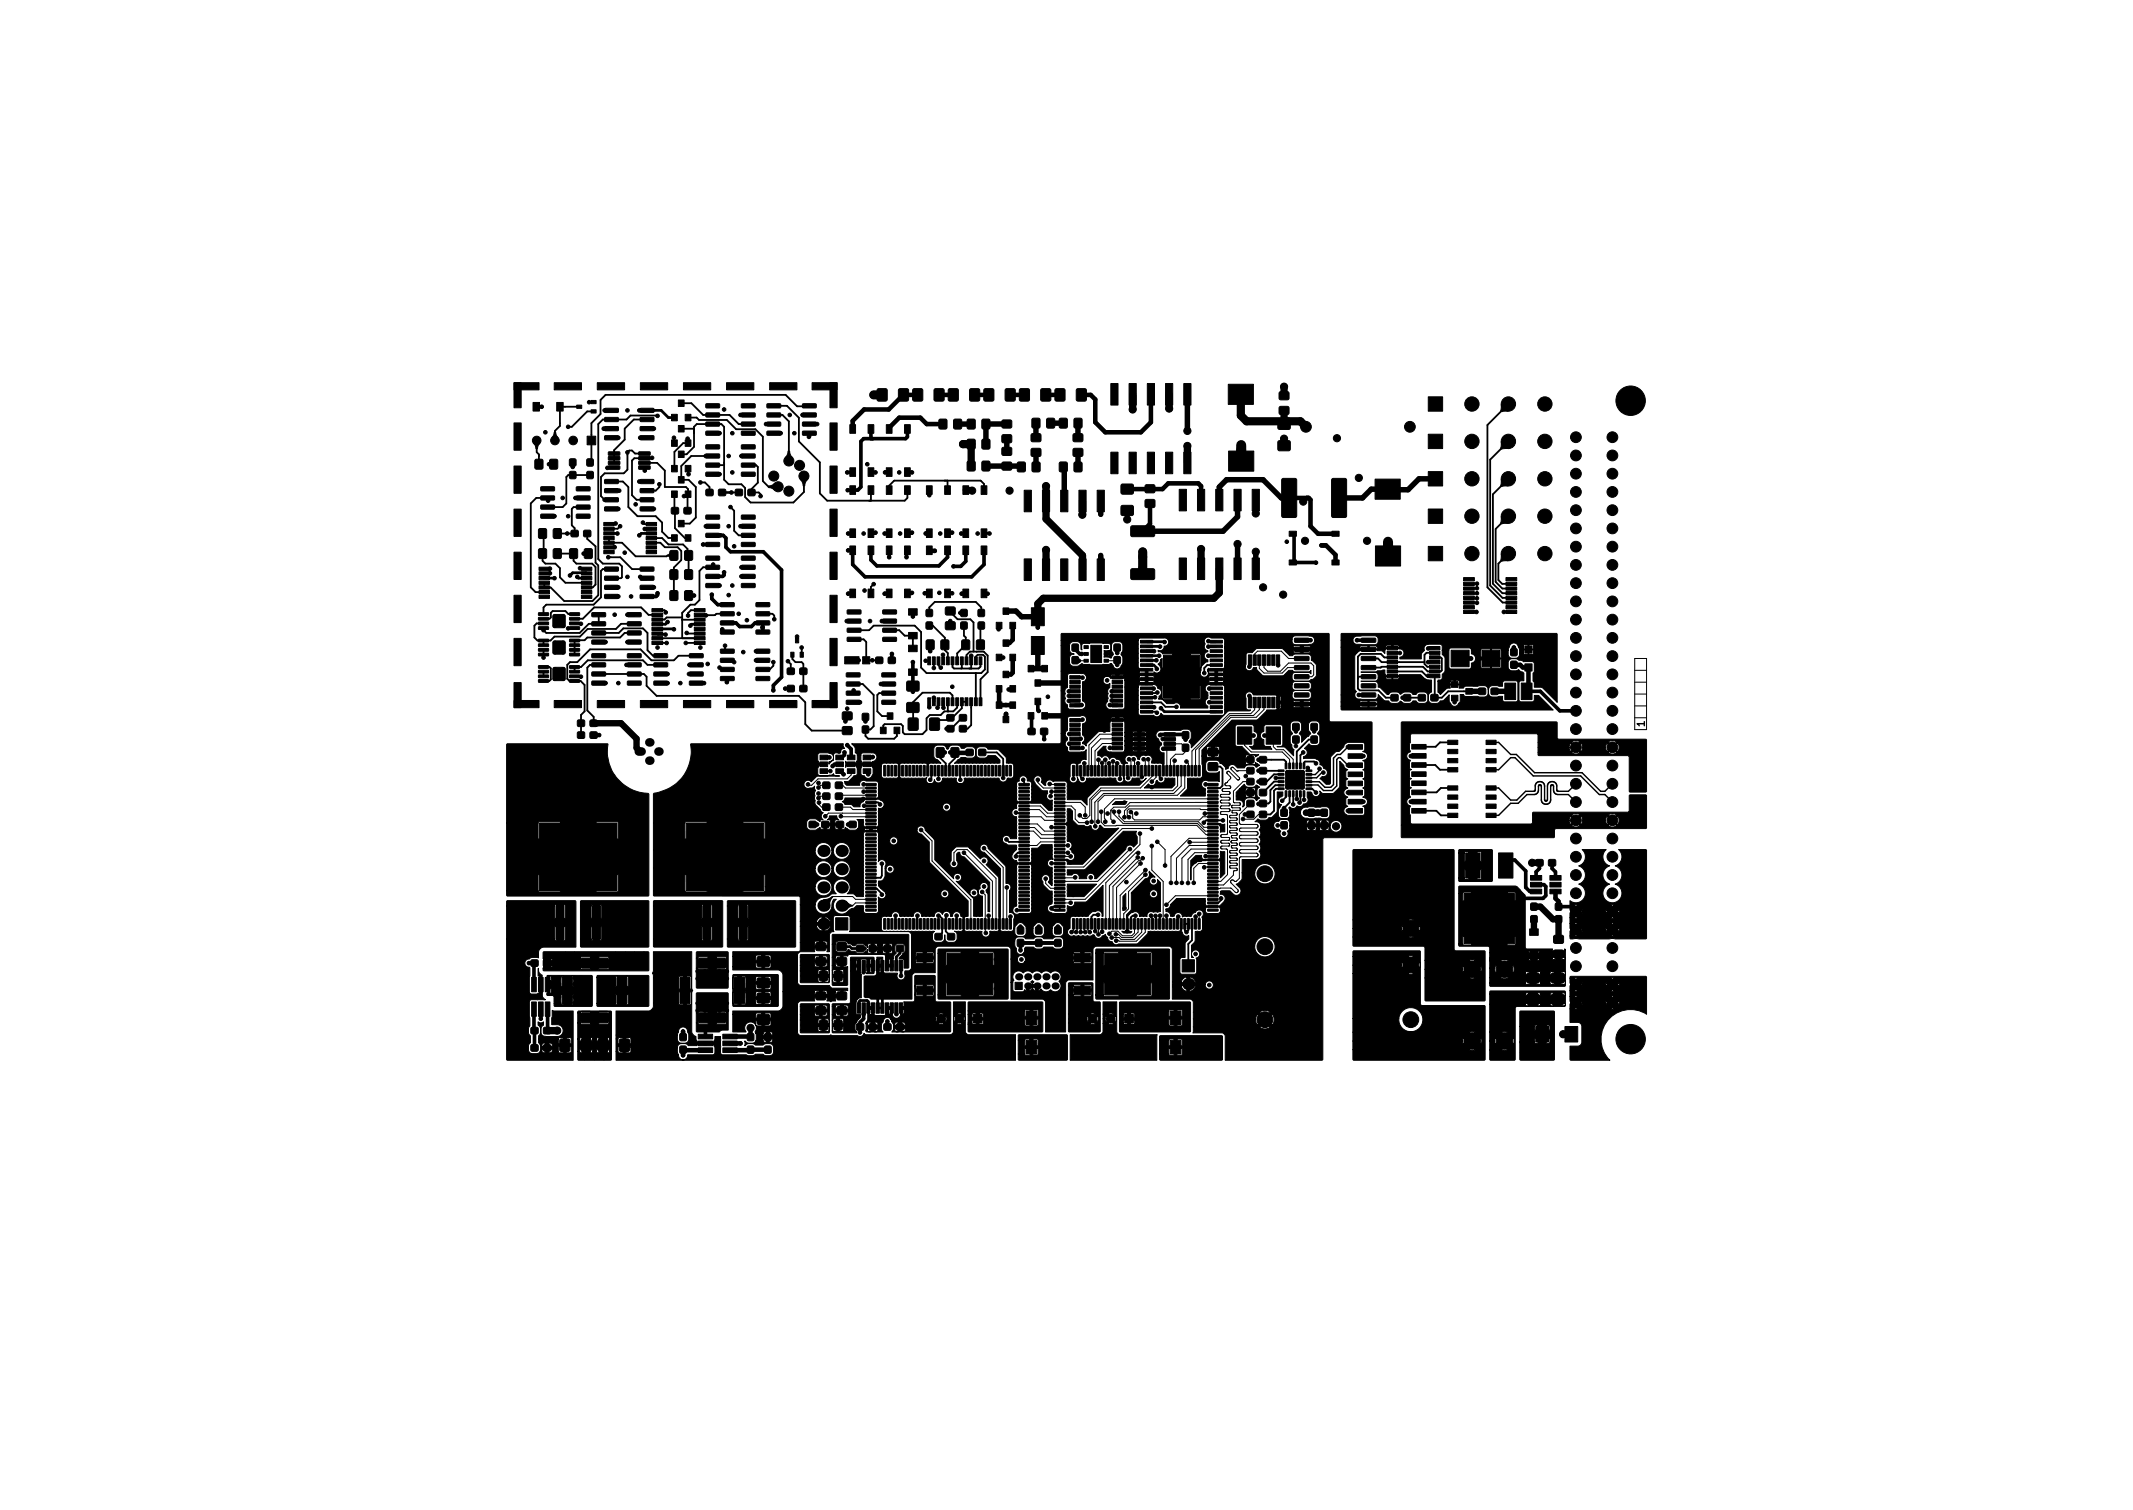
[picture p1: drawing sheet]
<svg xmlns="http://www.w3.org/2000/svg" width="297mm" height="210mm" viewBox="0 0 297 210" stroke-linecap="round" stroke-linejoin="round" font-family="sans-serif">
<defs><g id="words">
<text font-size="1.4" x="229" y="101.2" transform="rotate(-90 229 101.2)">1</text>
</g></defs>
<g fill="#000" stroke="#000" stroke-width=".14">
<path d="M71.6 53.3h1v3.5h-1zM74.2 56h.9v1.2h-.9zM71.6 53.3h3.5v1h-3.5zM77.5 56h.9v1.2h-.9zM77.2 53.3h3.8v1h-3.8zM80.3 56.4h.7v.5h-.7zM82.3 55.8h.7v.4h-.7zM82.3 57.1h.7v.4h-.7zM84.2 59.4h1.8l.1 .1v.4l-.1 .1h-1.7l-.1-.2zM84.2 58.2l1.8-.1 .1 .1v.4l-.1 .1h-1.7l-.1-.1zM84.2 56.9l1.8-.1 .1 .2v.3l-.1 .1h-1.7l-.1-.1zM83.2 53.3h3.8v1h-3.8z"/>
<path d="M89.2 56.9l1.8-.1 .1 .2v.3l-.2 .1h-1.6l-.2-.1zM89.2 58.2l1.8-.1 .1 .1v.4l-.2 .1h-1.6l-.2-.1zM89.2 59.4h1.8l.1 .1v.4l-.2 .1h-1.6l-.2-.2zM89.2 53.3h3.8v1h-3.8zM93.5 57.7h.8v.9h-.8zM94.5 55.7h.8v.9h-.8zM95.4 57.7h.8v.9h-.8zM95.2 53.3h3.8v1h-3.8zM98.3 58.8h1.8l.1 .1v.3l-.1 .1h-1.7l-.1-.1zM98.3 57.5h1.8l.1 .1v.4l-.1 .1h-1.7l-.1-.2zM98.3 56.3l1.8-.1 .1 .1v.4l-.1 .1h-1.7l-.1-.1zM101.2 53.3h3.8v1h-3.8z"/>
<path d="M103.3 56.3l1.8-.1 .1 .1v.4l-.2 .1h-1.7l-.1-.1zM103.3 57.5h1.8l.1 .1v.4l-.2 .1h-1.7l-.1-.2zM103.3 58.8h1.8l.1 .1v.3l-.2 .1h-1.7l-.1-.1zM106.8 58.8h1.8l.1 .1v.3l-.1 .1h-1.7l-.1-.1zM106.8 57.5h1.8l.1 .1v.4l-.1 .1h-1.7l-.1-.2zM106.8 56.3l1.8-.1 .1 .1v.4l-.1 .1h-1.7l-.1-.1zM107.2 53.3h3.8v1h-3.8zM111.8 56.3l1.8-.1 .1 .1v.4l-.1 .1h-1.7l-.2-.1zM111.8 57.5h1.8l.1 .1v.4l-.1 .1h-1.7l-.2-.2zM111.8 58.8h1.8l.1 .1v.3l-.1 .1h-1.7l-.2-.1zM115.6 53.3h1v3.5h-1zM113.1 53.3h3.5v1h-3.5z"/>
<path d="M122.2 54.2l1.1-.1 .2 .1 .1 1.4-.1 .2-1.1 .1-.2-.1-.1-1.4zM125.2 54.2l1.1-.1 .2 .1v1.4l-.1 .2-1 .1-.2-.1-.1-1.4zM127.2 54.2l1.1-.1 .2 .1v1.4l-.1 .2-1.1 .1-.2-.1v-1.4zM130.1 54.2l1.1-.1 .2 .1 .1 1.4-.1 .2-1.1 .1-.2-.1v-1.4zM130.8 58.4l.8-.1 .2 .1 .1 1.1-.1 .2h-.8h-.2l-.1-1.1zM132.1 54.2l1.1-.1 .2 .1 .1 1.4-.1 .2-1.1 .1-.2-.1-.1-1.4zM132.9 58.4l.8-.1 .2 .1v1.1l-.1 .2h-.8h-.2v-1.1zM134.7 58.4l.9-.1 .2 .1v1.1l-.1 .2h-.8h-.2v-1.1zM135.1 54.2l1.1-.1 .2 .1v1.4l-.1 .2-1 .1-.2-.1-.1-1.4zM136.8 58.4l.8-.1 .2 .1 .1 1.1-.1 .2h-.8h-.2l-.1-1.1zM137.1 54.2l1.1-.1 .2 .1v1.4l-.1 .2-1.1 .1-.2-.1v-1.4zM139.6 58.5h.2h1l.1 .2v.8l-.2 .1h-1.1l-.1-.2z"/>
<path d="M140 54.2l1.1-.1 .2 .1 .1 1.4-.1 .2-1.1 .1-.2-.1v-1.4zM142 54.2l1.1-.1 .2 .1 .1 1.4-.1 .2-1.1 .1-.2-.1-.1-1.4zM143.8 58.3l.8-.1 .2 .1v1.1l-.1 .2h-.8l-.2-.1v-1zM145 54.2l1.1-.1 .2 .1v1.4v.2l-1.1 .1-.2-.1-.1-1.4zM145.8 58.3l.8-.1 .2 .1 .1 1.1-.1 .2h-.8l-.2-.1-.1-1zM147 54.2l1.1-.1 .2 .1v1.4l-.1 .2-1.1 .1-.1-.1-.1-1.4zM147.6 58.3l.8-.1 .2 .1v1.1v.2h-.9l-.1-.1-.1-1zM149.6 58.3l.8-.1 .2 .1 .1 1.1-.1 .2h-.8l-.2-.1-.1-1zM149.9 54.2l1.1-.1 .2 .1 .1 1.4-.1 .2-1.1 .1-.2-.1v-1.4zM154.7 53.4h1v3h-1zM157.2 53.4h1v3h-1zM159.8 53.4h1v3h-1z"/>
<path d="M162.3 53.4h1v3h-1zM164.9 53.4h1v3h-1zM171 53.5h3.5v2.8h-3.5zM178.2 54.6l.2-.1 1 .1 .1 .2v.8l-.2 .1-1.1-.1-.1-.2zM178.2 56.7l.2-.1h1l.1 .2v.8l-.2 .1h-1.1l-.1-.2zM178 58.4h.2h1.4l.1 .2-.1 1.1-.2 .1-1.4-.1-.1-.2zM198.9 55.3h2v2h-2zM209.1 56.3l1.3-.4-.4 1.3-.9 .1-.1-.1zM71.6 58.9h1v3.8h-1zM71.6 64.9h1v3.8h-1zM71.6 70.9h1v3.8h-1zM75.1 79h1.4v.4h-1.4z"/>
<path d="M74.7 61.1l.4 .7-.2 .3v.4h-.3v-.4l-.3-.3zM74.5 64l.9-.1 .2 .1v1.1l-.1 .2h-.8l-.2-.1v-1zM75.1 73.7l.8-.1 .2 .1v1l-.1 .2-.8 .1-.2-.1v-1.1zM75.1 76.5l.8-.1 .2 .1v1l-.1 .2-.8 .1-.2-.1v-1.1zM75.3 71.6h1.8l.1 .1v.4l-.1 .1h-1.7l-.1-.2zM75.3 70.4l1.8-.1 .1 .1v.4l-.1 .1h-1.7l-.1-.1zM75.3 69.1l1.8-.1 .1 .2v.3l-.1 .1h-1.7l-.1-.1zM75.3 67.8h1.8l.1 .1v.3l-.1 .2h-1.7l-.1-.2zM77.2 60.2h.2l.1 .4 .2 .3-.4 .7-.4-.7 .2-.3zM76.6 64l.8-.1 .2 .1 .1 1.1-.1 .2h-.8l-.2-.1-.1-1zM77.1 73.7l.8-.1 .2 .1 .1 1-.1 .2-.8 .1-.2-.1-.1-1.1zM77.1 76.5l.8-.1 .2 .1 .1 1-.1 .2-.8 .1-.2-.1-.1-1.1z"/>
<path d="M79.4 63.9h.6l.2 .1v.7l-.1 .2h-.6l-.2-.1zM79.4 65.7l.6-.1 .2 .1v.7l-.1 .2-.6 .1-.2-.1zM79.4 76.5l.8-.1 .2 .1v1v.2l-.9 .1-.1-.1-.1-1.1zM79.6 73.9h.9v.2v.6l-.2 .1-.7-.1-.1-.2zM81 79h1.4v.4h-1.4zM80.3 67.8h1.8l.1 .1v.3l-.1 .2h-1.7l-.2-.2zM80.3 69.1l1.8-.1 .1 .2v.3l-.1 .1h-1.7l-.2-.1zM80.3 70.4l1.8-.1 .1 .1v.4l-.1 .1h-1.7l-.2-.1zM80.3 71.6h1.8l.1 .1v.4l-.1 .1h-1.7l-.2-.2zM81.3 73.9h.9l.1 .2-.1 .6-.1 .1-.8-.1-.1-.2zM81.4 76.5l.8-.1 .2 .1 .1 1-.1 .2-.8 .1-.2-.1-.1-1.1zM81.8 63.9h.6l.2 .1v.7v.2h-.7l-.2-.1z"/>
<path d="M81.8 65.7l.6-.1 .2 .1v.7v.2l-.7 .1-.2-.1zM81.8 60.7h1.2v1.2h-1.2zM84.1 76.6h1.4v.5h-1.4zM84.1 76h1.4v.4h-1.4zM84.1 75.3h1.4v.5h-1.4zM84.1 74.7h1.4v.4h-1.4zM84.1 74h1.4v.5h-1.4zM84.1 73.4h1.4v.4h-1.4zM84.1 72.7h1.4v.5h-1.4zM84.2 79l1.8-.1 .1 .2v.3l-.1 .1h-1.7l-.1-.1zM84.2 70.6h1.8l.1 .1v.3l-.1 .2h-1.7l-.1-.2zM84.2 69.3h1.8l.1 .1v.4l-.1 .1h-1.7l-.1-.1z"/>
<path d="M84.2 68.1l1.8-.1 .1 .1v.4l-.1 .1h-1.7l-.1-.1zM84.2 66.8h1.8l.1 .1v.3l-.1 .1h-1.7l-.1-.1zM84.2 60.7h1.8l.1 .1v.3l-.1 .2h-1.7l-.1-.2zM84.7 64.9h1.5h.1v.4l-.1 .1h-1.4l-.1-.2zM84.7 64.2h1.5l.1 .1v.3l-.1 .1h-1.4l-.1-.1zM84.7 63.6h1.5h.1v.4l-.1 .1h-1.4l-.1-.2zM84.7 62.9h1.5l.1 .1v.3l-.1 .1h-1.4l-.1-.1zM90 72.7h1.4v.5h-1.4zM90 73.4h1.4v.4h-1.4zM90 74h1.4v.5h-1.4zM90 74.7h1.4v.4h-1.4zM90 75.3h1.4v.5h-1.4z"/>
<path d="M90 76h1.4v.4h-1.4zM90 76.6h1.4v.5h-1.4zM89 62.9h1.5v.1l.1 .3-.2 .1h-1.4l-.1-.1zM89 63.6h1.5l.1 .4-.2 .1h-1.4l-.1-.2zM89 64.2h1.5v.1l.1 .3-.2 .1h-1.4l-.1-.1zM89 64.9h1.5l.1 .4-.2 .1h-1.4l-.1-.2zM89.2 79l1.8-.1 .1 .2v.3l-.2 .1h-1.6l-.2-.1zM89.2 66.8h1.8l.1 .1v.3l-.2 .1h-1.6l-.2-.1zM89.2 68.1l1.8-.1 .1 .1v.4l-.2 .1h-1.6l-.2-.1zM89.2 69.3h1.8l.1 .1v.4l-.2 .1h-1.6l-.2-.1zM89.2 70.6h1.8l.1 .1v.3l-.2 .2h-1.6l-.2-.2zM89.2 60.7h1.8l.1 .1v.3l-.2 .2h-1.6l-.2-.2z"/>
<path d="M93.3 76.7l.9-.1 .2 .1v1.1l-.1 .2h-.8l-.2-.1v-1zM93.3 79.4l.9-.1 .2 .1v1.1l-.1 .1-.8 .1-.2-.1v-1zM93.5 70.7h.9l.1 .2v.6l-.2 .1-.7-.1-.1-.1zM93.5 68.4h.8v.9h-.8zM93.5 64.8h.8v.9h-.8zM93.5 74.5h.8v.9h-.8zM93.5 61.3h.8v.9h-.8zM94.5 66.4h.8v.9h-.8zM94.5 62.8h.8v.9h-.8zM94.5 72.5h.8v.9h-.8zM94.5 59.3h.8v.9h-.8zM95.3 70.7h.9l.1 .2-.1 .6-.2 .1-.7-.1-.1-.1z"/>
<path d="M95.4 68.4h.8v.9h-.8zM95.4 64.8h.8v.9h-.8zM95.4 74.5h.8v.9h-.8zM95.4 61.3h.8v.9h-.8zM95.4 76.7l.8-.1 .2 .1 .1 1.1-.1 .2h-.8l-.2-.1-.1-1zM95.4 79.4l.8-.1 .2 .1 .1 1.1-.1 .1-.8 .1-.2-.1-.1-1zM98.4 68.2h.8l.1 .1v.7h-.2h-.7l-.1-.2zM98.3 65.8l1.8-.1 .1 .2v.3l-.1 .1h-1.7l-.1-.1zM98.3 64.5h1.8l.1 .1v.3l-.1 .2h-1.7l-.1-.2zM98.3 63.2h1.8l.1 .1v.4l-.1 .1h-1.7l-.1-.1zM98.3 62l1.8-.1 .1 .1v.4l-.1 .1h-1.7l-.1-.1zM98.3 60.1l1.8-.1 .1 .1v.4l-.1 .1h-1.7l-.1-.1z"/>
<path d="M98.3 80h1.8l.1 .1v.3l-.1 .2h-1.7l-.1-.2zM98.3 78.7h1.8l.1 .1v.4l-.1 .1h-1.7l-.1-.1zM98.3 77.5l1.8-.1 .1 .1v.4l-.1 .1h-1.7l-.1-.1zM98.3 75.6l1.8-.1 .1 .1v.4l-.1 .1h-1.7l-.1-.1zM98.3 74.3l1.8-.1 .1 .2v.3l-.1 .1h-1.7l-.1-.1zM98.3 73h1.8l.1 .1v.4l-.1 .1h-1.7l-.1-.2zM98.3 71.7h1.8l.1 .1v.4l-.1 .1h-1.7l-.1-.1zM100.1 68.2h.9l.1 .1-.1 .7h-.2h-.7l-.1-.2zM102.4 68.2h.9l.1 .1v.7h-.2h-.7l-.1-.2zM104.2 68.2h.9l.1 .1-.1 .7h-.2h-.7l-.1-.2zM103.3 62l1.8-.1 .1 .1v.4l-.2 .1h-1.7l-.1-.1zM103.3 63.2h1.8l.1 .1v.4l-.2 .1h-1.7l-.1-.1z"/>
<path d="M103.3 64.5h1.8l.1 .1v.3l-.2 .2h-1.7l-.1-.2zM103.3 65.8l1.8-.1 .1 .2v.3l-.2 .1h-1.7l-.1-.1zM103.3 60.1l1.8-.1 .1 .1v.4l-.2 .1h-1.7l-.1-.1zM103.3 77.5l1.8-.1 .1 .1v.4l-.2 .1h-1.7l-.1-.1zM103.3 78.7h1.8l.1 .1v.4l-.2 .1h-1.7l-.1-.1zM103.3 80h1.8l.1 .1v.3l-.2 .2h-1.7l-.1-.2zM103.3 71.7h1.8l.1 .1v.4l-.2 .1h-1.7l-.1-.1zM103.3 73h1.8l.1 .1v.4l-.2 .1h-1.7l-.1-.2zM103.3 74.3l1.8-.1 .1 .2v.3l-.2 .1h-1.7l-.1-.1zM103.3 75.6l1.8-.1 .1 .1v.4l-.2 .1h-1.7l-.1-.1zM106.8 60.1l1.8-.1 .1 .1v.4l-.1 .1h-1.7l-.1-.1zM107 67.7l.5-.1 .4-.3 .8 .5-.8 .5-.4-.3-.5-.1z"/>
<path d="M109.7 62.8h.3l.1 .5 .2 .4-.4 .8-.5-.8 .2-.4zM112 66l.4 .8-.2 .4-.1 .5h-.3l-.1-.5-.2-.4zM111.8 60.1l1.8-.1 .1 .1v.4l-.1 .1h-1.7l-.2-.1zM115.6 58.9h1v3.8h-1zM115.6 70.9h1v3.8h-1zM115.6 64.9h1v3.8h-1zM118.3 76h.8v1.2h-.8zM118.3 67.6h.8v1.2h-.8zM118.3 73.6h.8v1.2h-.8zM118.3 59.1h.8v1.2h-.8zM118.3 65.1h.8v1.2h-.8zM120.9 76h.8v1.2h-.8z"/>
<path d="M120.9 67.6h.8v1.2h-.8zM120.9 73.6h.8v1.2h-.8zM120.9 59.1h.8v1.2h-.8zM120.9 65.1h.8v1.2h-.8zM123.4 76h.8v1.2h-.8zM123.4 67.6h.8v1.2h-.8zM123.4 73.6h.8v1.2h-.8zM123.4 59.1h.8v1.2h-.8zM123.4 65.1h.8v1.2h-.8zM126 76h.8v1.2h-.8zM126 67.6h.8v1.2h-.8zM126 73.6h.8v1.2h-.8z"/>
<path d="M126 59.1h.8v1.2h-.8zM126 65.1h.8v1.2h-.8zM129 67.6h.8v1.2h-.8zM129 73.6h.8v1.2h-.8zM129 76h.8v1.2h-.8zM131.6 67.6h.8v1.2h-.8zM131.6 73.6h.8v1.2h-.8zM131.6 76h.8v1.2h-.8zM134.1 67.6h.8v1.2h-.8zM134.1 73.6h.8v1.2h-.8zM134.1 76h.8v1.2h-.8zM134.7 61.2l.9-.1 .2 .1v1.1l-.1 .2h-.8h-.2v-1.1z"/>
<path d="M134.7 64.3l.9-.1 .2 .1v1l-.1 .2-.8 .1-.2-.1v-1.1zM136.6 67.6h.8v1.2h-.8zM136.6 73.6h.8v1.2h-.8zM136.6 76h.8v1.2h-.8zM136.8 61.2l.8-.1 .2 .1 .1 1.1-.1 .2h-.8h-.2l-.1-1.1zM136.8 64.3l.8-.1 .2 .1 .1 1-.1 .2-.8 .1-.2-.1-.1-1.1zM139.6 60.6l.2-.1 1 .1 .1 .2v.8l-.2 .1-1.1-.1-.1-.2zM139.6 64.4l.2-.1 1 .1 .1 .2v.8l-.2 .1-1.1-.1-.1-.2zM139.6 62.3h.2h1l.1 .2v.8l-.2 .1h-1.1l-.1-.2zM141.7 64.4l.9-.1 .1 .1 .1 1.1-.1 .2h-.8l-.2-.1v-1zM142.6 77.8h1v3h-1zM142.6 68.3h1v3h-1z"/>
<path d="M143.8 64.4l.8-.1 .2 .1 .1 1.1-.1 .2h-.8l-.2-.1-.1-1zM143.6 60.4h.2h1.1l.1 .2-.1 .8-.2 .1h-1l-.1-.2zM143.6 62.5l.2-.1 1.1 .1 .1 .2-.1 .8-.2 .1-1-.1-.1-.2zM145.2 77.8h1v3h-1zM145.2 68.3h1v3h-1zM147.6 64.4l.8-.1 .2 .1v1.1v.2h-.9l-.1-.1-.1-1zM147.7 77.8h1v3h-1zM147.7 68.3h1v3h-1zM149.6 64.4l.8-.1 .2 .1 .1 1.1-.1 .2h-.8l-.2-.1-.1-1zM149.5 62.5l.2-.1 1 .1 .1 .2v.8l-.2 .1-1.1-.1-.1-.2zM149.5 60.4h.2h1l.1 .2v.8l-.2 .1h-1.1l-.1-.2zM150.2 77.8h1v3h-1z"/>
<path d="M150.2 68.3h1v3h-1zM152.8 77.8h1v3h-1zM152.8 68.3h1v3h-1zM154.7 63h1v3h-1zM156.2 67.5l.1-.1h1.5v.2v1.1l-.2 .1h-1.4l-.1-.2zM156.2 70.4h.1h1.5v.2v1.1l-.2 .1-1.4-.1-.1-.2zM157.2 63h1v3h-1zM157.5 79.3l.2-.1h3l.1 .2v1.2l-.2 .1h-3l-.1-.2zM157.5 73.3l.2-.1h3l.1 .2v1.2l-.2 .1h-3l-.1-.2zM159.5 69.6l.2-.1 1.1 .1v.2v.8l-.2 .1-1.1-.1-.1-.2zM159.5 67.6l.2-.1h1.1v.2v.8l-.2 .1h-1.1l-.1-.2zM159.8 63h1v3h-1z"/>
<path d="M162.3 63h1v3h-1zM164.2 77.7h1v3h-1zM164.2 68.1h1v3h-1zM164.9 63h1v3h-1zM166.8 77.7h1v3h-1zM166.8 68.1h1v3h-1zM169.3 77.7h1v3h-1zM169.3 68.1h1v3h-1zM171.1 62.8h3.5v2.8h-3.5zM171.8 77.7h1v3h-1zM171.8 68.1h1v3h-1zM174.4 77.7h1v3h-1z"/>
<path d="M174.4 68.1h1v3h-1zM178 61.4l.2-.1 1.4 .1 .1 .2-.1 1.1-.2 .1-1.4-.1-.1-.2zM179.5 78h1v.7h-1zM179.5 74h1v.7h-1zM178.6 66.7l1.8-.1 .2 .2v5l-.2 .3h-1.7l-.2-.2v-5zM185.5 74h1v.7h-1zM185.5 78h1v.7h-1zM185.5 66.7l1.8-.1 .2 .2v5l-.1 .3h-1.7l-.3-.2v-5zM191.5 66.7h3.5v2.8h-3.5zM191.5 76h3.5v2.8h-3.5zM198.9 76.1h2v2h-2zM198.9 70.9h2v2h-2z"/>
<path d="M198.9 65.7h2v2h-2zM198.9 60.5h2v2h-2zM209.1 61.5l1.3-.4-.4 1.3-.9 .1-.1-.1zM209.1 66.7l1.3-.4-.4 1.4h-.9l-.1-.1zM209.1 71.9l1.3-.4-.4 1.4h-.9l-.1-.1zM209.1 77.1l1.3-.4-.4 1.4-.9 .1-.1-.2zM71.6 95h1v3.5h-1zM71.6 82.9h1v3.8h-1zM71.6 88.9h1v3.8h-1zM71.6 76.9h1v3.8h-1zM75.1 82.9h1.4v.4h-1.4zM75.1 82.2h1.4v.5h-1.4z"/>
<path d="M75.1 81.6h1.4v.4h-1.4zM75.1 80.9h1.4v.5h-1.4zM75.1 80.3h1.4v.4h-1.4zM75.1 79.6h1.4v.5h-1.4zM71.6 97.5h3.5v1h-3.5zM75 91l1.3-.1 .1 .4h-.1h-1.2zM75 90.3h1.3l.1 .3-.1 .1h-1.2zM75 89.7l1.3-.1 .1 .4h-.1h-1.2zM75 89h1.3l.1 .3-.1 .1h-1.2zM75 94.7l1.3-.1 .1 .3-.1 .1h-1.2zM75 94h1.3l.1 .3-.1 .1h-1.2zM75 93.4l1.3-.1 .1 .3-.1 .1h-1.2z"/>
<path d="M75 92.7h1.3l.1 .3-.1 .1h-1.2zM75 87.3h1.3l.1 .3-.1 .1h-1.2zM75 86.6h1.3l.1 .3-.1 .1h-1.2zM75 86h1.3l.1 .3-.1 .1h-1.2zM75 85.3h1.3l.1 .3-.1 .1h-1.2zM77.1 89.3l.1-.1 1.4 .1 .1 .2-.1 1.5-.1 .1-1.4-.1-.1-.2zM77.1 93l.1-.1 1.4 .1 .1 .2-.1 1.5-.1 .1-1.4-.1-.1-.2zM77.1 85.6h.1h1.4l.1 .2-.1 1.5-.1 .1-1.4-.1-.1-.1zM79.3 89h1.3l.1 .3-.1 .1h-1.2zM79.3 89.7l1.3-.1 .1 .4h-.1h-1.2zM79.3 90.3h1.3l.1 .3-.1 .1h-1.2zM79.3 91l1.3-.1 .1 .4h-.1h-1.2z"/>
<path d="M79.3 92.7h1.3l.1 .3-.1 .1h-1.2zM79.3 93.4l1.3-.1 .1 .3-.1 .1h-1.2zM79.3 94h1.3l.1 .3-.1 .1h-1.2zM79.3 94.7l1.3-.1 .1 .3-.1 .1h-1.2zM79.3 85.3h1.3l.1 .3-.1 .1h-1.2zM79.3 86h1.3l.1 .3-.1 .1h-1.2zM79.3 86.6h1.3l.1 .3-.1 .1h-1.2zM79.3 87.3h1.3l.1 .3-.1 .1h-1.2zM81 79.6h1.4v.5h-1.4zM81 80.3h1.4v.4h-1.4zM81 80.9h1.4v.5h-1.4zM81 81.6h1.4v.4h-1.4z"/>
<path d="M81 82.2h1.4v.5h-1.4zM81 82.9h1.4v.4h-1.4zM77.2 97.5h3.8v1h-3.8zM82.4 89.1h1.8l.1 .1v.4l-.1 .1h-1.7l-.1-.1zM82.4 87.9l1.8-.1 .1 .2v.3l-.1 .1h-1.7l-.1-.1zM82.4 86.6h1.8l.1 .1v.3l-.1 .2h-1.7l-.1-.2zM82.4 85.3h1.8l.1 .1v.4l-.1 .1h-1.7l-.1-.1zM82.4 94.9l1.8-.1 .1 .1v.4l-.1 .1h-1.7l-.1-.1zM82.4 93.6h1.8l.1 .1v.3l-.1 .1h-1.7l-.1-.1zM82.4 92.3h1.8l.1 .1v.4l-.1 .1h-1.7l-.1-.2zM82.4 91.1l1.8-.1 .1 .1v.4l-.1 .1h-1.7l-.1-.1zM84.2 82.8h1.8l.1 .1v.3l-.1 .2-1.7-.1-.1-.1z"/>
<path d="M84.2 81.5h1.8l.1 .1v.4l-.1 .1h-1.7l-.1-.2zM84.2 80.3l1.8-.1 .1 .1v.4l-.1 .1h-1.7l-.1-.1zM83.2 97.5h3.8v1h-3.8zM87.4 85.3h1.8l.1 .1v.4l-.1 .1h-1.7l-.1-.1zM87.4 86.6h1.8l.1 .1v.3l-.1 .2h-1.7l-.1-.2zM87.4 87.9l1.8-.1 .1 .2v.3l-.1 .1h-1.7l-.1-.1zM87.4 89.1h1.8l.1 .1v.4l-.1 .1h-1.7l-.1-.1zM87.4 91.1l1.8-.1 .1 .1v.4l-.1 .1h-1.7l-.1-.1zM87.4 92.3h1.8l.1 .1v.4l-.1 .1h-1.7l-.1-.2zM87.4 93.6h1.8l.1 .1v.3l-.1 .1h-1.7l-.1-.1zM87.4 94.9l1.8-.1 .1 .1v.4l-.1 .1h-1.7l-.1-.1zM90.8 89.3h1.5v.4h-1.5z"/>
<path d="M90.8 88.6h1.5v.5h-1.5zM90.8 88h1.5v.4h-1.5zM90.8 87.3h1.5v.5h-1.5zM90.8 86.7h1.5v.4h-1.5zM90.8 86h1.5v.5h-1.5zM90.8 85.4h1.5v.4h-1.5zM90.8 84.7h1.5v.5h-1.5zM89.2 80.3l1.8-.1 .1 .1v.4l-.2 .1h-1.6l-.2-.1zM89.2 81.5h1.8l.1 .1v.4l-.2 .1h-1.6l-.2-.2zM89.2 82.8h1.8l.1 .1v.3l-.2 .2-1.6-.1-.2-.1zM91.1 94.9l1.8-.1 .1 .1v.4l-.1 .1h-1.7l-.2-.1zM91.1 93.6h1.8l.1 .1v.3l-.1 .1h-1.7l-.2-.1z"/>
<path d="M91.1 92.3h1.8l.1 .1v.4l-.1 .1h-1.7l-.2-.2zM91.1 91.1l1.8-.1 .1 .1v.4l-.1 .1h-1.7l-.2-.1zM89.2 97.5h3.8v1h-3.8zM93.3 82.3l.9-.1 .2 .1v1.1l-.1 .2h-.8l-.2-.1v-1zM95.4 82.3l.8-.1 .2 .1 .1 1.1-.1 .2h-.8l-.2-.1-.1-1zM96.7 84.7h1.5v.5h-1.5zM96.7 85.4h1.5v.4h-1.5zM96.7 86h1.5v.5h-1.5zM96.7 86.7h1.5v.4h-1.5zM96.7 87.3h1.5v.5h-1.5zM96.7 88h1.5v.4h-1.5zM96.7 88.6h1.5v.5h-1.5z"/>
<path d="M96.7 89.3h1.5v.4h-1.5zM96 91.1l1.8-.1 .1 .1v.4l-.1 .1h-1.7l-.1-.1zM96 92.3h1.8l.1 .1v.4l-.1 .1h-1.7l-.1-.2zM96 93.6h1.8l.1 .1v.3l-.1 .1h-1.7l-.1-.1zM96 94.9l1.8-.1 .1 .1v.4l-.1 .1h-1.7l-.1-.1zM95.2 97.5h3.8v1h-3.8zM98.3 81.3l1.8-.1 .1 .1v.4l-.1 .1h-1.7l-.1-.1zM100.4 87.7h1.7l.2 .1v.4l-.2 .1h-1.7l-.1-.1zM100.4 86.5l1.7-.1 .2 .2v.3l-.2 .1h-1.7l-.1-.1zM100.4 85.2h1.7l.2 .1v.3l-.2 .2h-1.7l-.1-.2zM100.4 83.9h1.7l.2 .1v.4l-.2 .1h-1.7l-.1-.1zM100.4 94.2h1.7l.2 .1v.4l-.2 .1h-1.7l-.1-.2z"/>
<path d="M100.4 93l1.7-.1 .2 .1v.4l-.2 .1h-1.7l-.1-.1zM100.4 91.7l1.7-.1 .2 .2v.3l-.2 .1h-1.7l-.1-.1zM100.4 90.4h1.7l.2 .1v.4l-.2 .1h-1.7l-.1-.2zM101.2 97.5h3.8v1h-3.8zM103.3 81.3l1.8-.1 .1 .1v.4l-.2 .1h-1.7l-.1-.1zM105.3 83.9h1.8l.1 .1v.4l-.1 .1h-1.7l-.1-.1zM105.3 85.2h1.8l.1 .1v.3l-.1 .2h-1.7l-.1-.2zM105.3 86.5l1.8-.1 .1 .2v.3l-.1 .1h-1.7l-.1-.1zM105.3 87.7h1.8l.1 .1v.4l-.1 .1h-1.7l-.1-.1zM105.3 90.4h1.8l.1 .1v.4l-.1 .1h-1.7l-.1-.2zM105.3 91.7l1.8-.1 .1 .2v.3l-.1 .1h-1.7l-.1-.1zM105.3 93l1.8-.1 .1 .1v.4l-.1 .1h-1.7l-.1-.1z"/>
<path d="M105.3 94.2h1.8l.1 .1v.4l-.1 .1h-1.7l-.1-.2zM110.1 90.8h.5v.7h-.5zM109.7 93.1l.9-.1v.2v.7h-.2h-.7l-.1-.2zM109.7 95.5h.9v.1v.7l-.2 .1-.7-.1-.1-.2zM110.8 88.8h.4v.7h-.4zM107.2 97.5h3.8v1h-3.8zM111.4 90.8h.5v.7h-.5zM111.4 93.1l.9-.1 .1 .2-.1 .7h-.1h-.8l-.1-.2zM111.4 95.5h.9l.1 .1-.1 .7-.1 .1-.8-.1-.1-.2zM115.6 82.9h1v3.8h-1zM115.6 76.9h1v3.8h-1zM115.6 88.9h1v3.8h-1z"/>
<path d="M115.6 95h1v3.5h-1zM113.1 97.5h3.5v1h-3.5zM117.6 91.4h2v1h-2zM118.3 82h.8v1.2h-.8zM117.4 99.2l.1-.1 1.1 .1 .1 .2-.1 .8-.2 .1-1-.1-.1-.2zM117.9 97.5h1.8l.1 .1v.4l-.2 .1h-1.6l-.2-.2zM117.9 96.3l1.8-.1 .1 .1v.4l-.2 .1h-1.6l-.2-.1zM117.9 95l1.8-.1 .1 .2v.3l-.2 .1h-1.6l-.2-.1zM117.9 93.7h1.8l.1 .1v.4l-.2 .1h-1.6l-.2-.2zM118 88.8l1.8-.1 .1 .1v.4l-.1 .1h-1.7l-.1-.1zM118 87.5h1.8l.1 .1v.3l-.1 .2-1.7-.1-.1-.1zM118 86.2h1.8l.1 .1v.4l-.1 .1h-1.7l-.1-.2z"/>
<path d="M118 85l1.8-.1 .1 .1v.4l-.1 .1h-1.7l-.1-.1zM120.1 91.4h1v1h-1zM120.1 99.4l.7-.1 .1 .1 .1 .7-.1 .2-.6 .1-.2-.1zM120.9 82h.8v1.2h-.8zM122 91.5h.9l.1 .2-.1 .6-.2 .1h-.7l-.1-.2zM123.4 82h.8v1.2h-.8zM123.7 91.5h.9l.1 .2v.6l-.2 .1h-.7l-.1-.2zM122.8 93.7h1.8l.1 .1v.4l-.1 .1h-1.7l-.1-.2zM122.8 95l1.8-.1 .1 .2v.3l-.1 .1h-1.7l-.1-.1zM122.8 96.3l1.8-.1 .1 .1v.4l-.1 .1h-1.7l-.1-.1zM122.8 97.5h1.8l.1 .1v.4l-.1 .1h-1.7l-.1-.2zM123 85l1.7-.1 .2 .1v.4l-.2 .1h-1.7l-.1-.1z"/>
<path d="M123 86.2h1.7l.2 .1v.4l-.2 .1h-1.7l-.1-.2zM123 87.5h1.7l.2 .1v.3l-.2 .2-1.7-.1-.1-.1zM123 88.8l1.7-.1 .2 .1v.4l-.2 .1h-1.7l-.1-.1zM126 82h.8v1.2h-.8zM126.5 88.1h1.2v.9h-1.2zM126.5 84.8h1.2v.9h-1.2zM126.5 100h1.1h.2l.1 1.5-.1 .2h-1.1l-.2-.1v-1.4zM126.5 89.8h1.2v.9h-1.2zM126.5 93.1h1.2v.9h-1.2zM126.3 97.9l.2-.1 1.4 .1 .1 .1-.1 1.1-.1 .1h-1.5v-.2zM126.3 94.9l.2-.1 1.4 .1 .1 .2-.1 1.1h-.1h-1.5v-.2zM129 82h.8v1.2h-.8z"/>
<path d="M129.2 91.5h.4v1.1h-.4zM129.2 97.2h.4v1.1h-.4zM129 84.9l.7-.1 .1 .1 .1 .7-.1 .2-.6 .1-.2-.1zM129 86.6h.7l.1 .1 .1 .7-.1 .2h-.6l-.2-.1zM129 89.2l.9-.1 .1 .1 .1 1-.1 .2-.8 .1-.2-.1v-1.1zM129.8 91.5h.4v1.1h-.4zM129.8 97.2h.4v1.1h-.4zM129.5 100h1.1h.2l.1 1.5-.1 .2h-1.1l-.2-.1-.1-1.4zM130.5 91.5h.4v1.1h-.4zM130.5 97.2h.4v1.1h-.4zM131.1 91.5h.4v1.1h-.4zM131.1 97.2h.4v1.1h-.4z"/>
<path d="M131.6 82h.8v1.2h-.8zM131.1 89.2l.8-.1 .2 .1 .1 1-.1 .2-.8 .1-.2-.1-.1-1.1zM131.8 91.5h.4v1.1h-.4zM131.8 97.2h.4v1.1h-.4zM131.9 99.5h.9l.1 .2-.1 .6-.2 .1h-.7l-.1-.2zM131.7 84.6l.2-.1 1 .1 .1 .2v.8l-.2 .1-1.1-.1-.1-.2zM131.7 86.6h.2h1l.1 .2v.8l-.2 .1-1.1-.1-.1-.1zM132.4 91.5h.4v1.1h-.4zM132.4 97.2h.4v1.1h-.4zM133.1 91.5h.4v1.1h-.4zM133.1 97.2h.4v1.1h-.4zM134.1 82h.8v1.2h-.8z"/>
<path d="M133.7 91.5h.4v1.1h-.4zM133.7 97.2h.4v1.1h-.4zM133.6 99.5h.9l.1 .2v.6l-.2 .1h-.7l-.1-.2zM133.8 84.9l.7-.1 .2 .1v.7l-.1 .2-.6 .1-.2-.1zM133.8 86.6h.7l.2 .1v.7l-.1 .2h-.6l-.2-.1zM134.4 91.5h.4v1.1h-.4zM134.4 97.2h.4v1.1h-.4zM134 89.2l.8-.1 .2 .1 .1 1-.1 .2-.8 .1-.2-.1-.1-1.1zM135 91.5h.4v1.1h-.4zM135 97.2h.4v1.1h-.4zM135.7 91.5h.4v1.1h-.4zM135.7 97.2h.4v1.1h-.4z"/>
<path d="M136.6 82h.8v1.2h-.8zM136.3 91.5h.4v1.1h-.4zM136.3 97.2h.4v1.1h-.4zM136 89.2l.9-.1 .2 .1v1l-.1 .2-.8 .1-.2-.1v-1.1zM136.2 86.6h.7l.2 .1v.7l-.1 .2h-.6l-.2-.1zM136.2 84.9l.7-.1 .2 .1v.7l-.1 .2-.6 .1-.2-.1zM138.7 97.7h.8v.9h-.8zM138.7 86.7h.8v.9h-.8zM138.7 91.1h.8v.9h-.8zM138.7 95.5h.8v.9h-.8zM139.7 99.7h.8v.9h-.8zM139.7 84.7h.8v.9h-.8z"/>
<path d="M139.7 89.1h.8v.9h-.8zM139.7 93.5h.8v.9h-.8zM140.6 97.7h.8v.9h-.8zM140.6 86.7h.8v.9h-.8zM140.6 91.1h.8v.9h-.8zM140.6 95.5h.8v.9h-.8zM143.2 92.7h.8v.9h-.8zM144.1 94.7h.8v.9h-.8zM144.1 97.2h.8v.9h-.8zM145.1 92.7h.8v.9h-.8zM143.6 84.6h1.8v2.5h-1.8zM143.6 88.6h1.8v2.5h-1.8z"/>
<path d="M149.3 91.5l.7-.1 .2 .1v.7l-.1 .2-.6 .1-.2-.1zM149.3 89.7h.7h.2v.8l-.1 .1-.6 .1-.2-.1zM149 98h1.4v.4h-1.4zM149 97.3h1.4v.5h-1.4zM149 96.7h1.4v.4h-1.4zM149 96h1.4v.5h-1.4zM149 95.4h1.4v.4h-1.4zM149 94.7h1.4v.5h-1.4zM149 94.1h1.4v.4h-1.4zM151 91.8h.6v.4h-.6zM151 90.9h.6v.4h-.6zM151 89.9h.6v.4h-.6z"/>
<path d="M151.9 89.9h1.5v2.4h-1.5zM153.8 89.9h.6v.4h-.6zM153.8 90.9h.6v.4h-.6zM153.8 91.8h.6v.4h-.6zM155.2 91.5l.6-.1 .2 .1v.7v.2l-.7 .1-.1-.1zM155.2 89.7h.6h.2v.8v.1l-.7 .1-.1-.1zM154.9 94.1h1.4v.4h-1.4zM154.9 94.7h1.4v.5h-1.4zM154.9 95.4h1.4v.4h-1.4zM154.9 96h1.4v.5h-1.4zM154.9 96.7h1.4v.4h-1.4zM154.9 97.3h1.4v.5h-1.4z"/>
<path d="M154.9 98h1.4v.4h-1.4zM158.8 98.9h1.7v.4h-1.7zM158.8 98.3h1.7v.3h-1.7zM158.8 97.6h1.7v.4h-1.7zM158.8 97h1.7v.3h-1.7zM158.8 96.3h1.7v.4h-1.7zM158.8 95.7h1.7v.3h-1.7zM158.8 95h1.7v.4h-1.7zM158.8 94.4h1.7v.3h-1.7zM158.8 93.7h1.7v.4h-1.7zM158.8 93.1h1.7v.3h-1.7zM158.8 92.4h1.7v.4h-1.7z"/>
<path d="M158.8 91.8h1.7v.3h-1.7zM158.8 91.1h1.7v.4h-1.7zM158.8 90.5h1.7v.3h-1.7zM158.8 89.8h1.7v.4h-1.7zM158.8 89.2h1.7v.3h-1.7zM162 91.2h5v6h-5zM168.5 97.6h1.7v.4h-1.7zM168.5 91.1h1.7v.4h-1.7zM168.5 89.2h1.7v.3h-1.7zM168.5 95.7h1.7v.3h-1.7zM168.5 96.3h1.7v.4h-1.7zM168.5 98.9h1.7v.4h-1.7z"/>
<path d="M168.5 91.8h1.7v.3h-1.7zM168.5 90.5h1.7v.3h-1.7zM168.5 98.3h1.7v.3h-1.7zM168.5 97h1.7v.3h-1.7zM168.5 93.1h1.7v.3h-1.7zM168.5 94.4h1.7v.3h-1.7zM168.5 92.4h1.7v.4h-1.7zM168.5 93.7h1.7v.4h-1.7zM168.5 89.8h1.7v.4h-1.7zM168.5 95h1.7v.4h-1.7zM173.8 91.2h.5v1.4h-.5zM173.8 97.1h.5v1.4h-.5z"/>
<path d="M174.5 91.2h.4v1.4h-.4zM174.5 97.1h.4v1.4h-.4zM175.1 91.2h.5v1.4h-.5zM175.1 97.1h.5v1.4h-.5zM175.8 91.2h.4v1.4h-.4zM175.8 97.1h.4v1.4h-.4zM176.4 91.2h.5v1.4h-.5zM176.4 97.1h.5v1.4h-.5zM177.1 91.2h.4v1.4h-.4zM177.1 97.1h.4v1.4h-.4zM177.7 91.2h.5v1.4h-.5zM177.7 97.1h.5v1.4h-.5z"/>
<path d="M180.3 97.8l1.9-.1 .1 .2v.3l-.1 .1h-1.8l-.1-.1zM180.3 96.5h1.9l.1 .1v.3l-.1 .2h-1.8l-.1-.2zM180.3 95.2h1.9l.1 .1v.4l-.1 .1h-1.8l-.1-.1zM180.3 94l1.9-.1 .1 .1v.4l-.1 .1h-1.8l-.1-.1zM180.3 92.7h1.9l.1 .1v.3l-.1 .2h-1.8l-.1-.2zM180.3 91.4h1.9l.1 .1v.4l-.1 .1h-1.8l-.1-.1zM180.3 90.2l1.9-.1 .1 .1v.4l-.1 .1h-1.8l-.1-.1zM180.3 88.9h1.9l.1 .1v.3l-.1 .1h-1.8l-.1-.1zM96.2 103.6h21.2v.3l.2 .3a.57 .57 0 0 0-.6 .6l-.8 .1-.1 .2v.8l-.7 .5 .1-.4a.6 .6 0 0 0 .6-.6 .6 .6 0 0 0-.7-.5l-1.3-.1-.2 .2v.8l.1 .4h.9v.4l-.9 .1-.1 .3v.8l.2 .2h1.2l.5-.1 .3-.2 .2 .3 .6 .1h-3.1l-.8 .8a.57 .57 0 0 0-.8-.2 .57 .57 0 0 0-.2 .8 .57 .57 0 0 0 .8 .2h.4l.3-.2-.1 .3 .2 .3a.67 .67 0 0 0-.1 .8l-.1 .3 .1 .3a.62 .62 0 0 0 .3 .8l.4 .4 .2 .3 .3 .2a.57 .57 0 0 0-.1 .9l-.3 .1-.1 .2-.6-.4h-.7a.56 .56 0 0 0-.6 .6l.1 .7 .4 .3h.8l.6-.4 .1 .2 .4 .1v-.5h.4l.1 .5h.3l.1-.2h.7l.1 .2h.3l.1-.5h-.5v.3h-.7v-.3h-.9v-.4h.9v-.4l-.4-.1 .2-.2 .1-.3h1l.1 .3 .2 .3h-.5v.4h.9v.9l.4-.1 .1-.2 .7 .4h.7l.4-.2h.9v.2h.7v-.3h.4v.3h.7v-.1h5.5a.57 .57 0 0 0 .6 .6l1.1 1.1 .1 2.9 5.3 5.3v2.2h-.4l-.2 .3 .1 1.6 .3 .2h1.9h.2a.57 .57 0 0 0 .6 .8 .57 .57 0 0 0 .5-.8h1.1l.3-.3-.1-7.1-.1-.3-1.7-1.6a.57 .57 0 0 0 .1-.9 .57 .57 0 0 0-.9 .1l-1.5-1.6h1.5a.57 .57 0 0 0 .6 .7l2.2 2.2-.1 8.5 .4 .3h1a.45 .45 0 0 0 .6-.4h.1v.5a.56 .56 0 0 0 .6 .6h.6l.2-.2 .2-.3v-.6h1v.5a.56 .56 0 0 0 .5 .6h.6l.3-.2 .1-.3v-.6h1.1v.5a.56 .56 0 0 0 .6 .6h.6l.3-.2 .1-.3v-.6a.83 .83 0 0 0-1.1-.7l-.4 .4-.1 .3h-1.1a.83 .83 0 0 0-1.1-.7l-.3 .4-.1 .3h-1a.83 .83 0 0 0-1.1-.7l-.4 .4-.1 .3h-.1v-1.3a.57 .57 0 0 0 0-.7 .57 .57 0 0 0-.6-.2v-.4h.4a.57 .57 0 0 0 .3 .5 .57 .57 0 0 0 .7 0h1.4a.61 .61 0 0 0 .3-.8v-5.7l-.1-.3-.3-.1h-1.4l-.3 .3v5.6a.57 .57 0 0 0-.6 .5h-.4v-2.7a.57 .57 0 0 0 .1-.7 .57 .57 0 0 0-.6-.3v-2.4l-2.5-2.6a.57 .57 0 0 0-.6-.5 .57 .57 0 0 0-.5 .5h-1.5l-.3-.1h-1.6l-.6 .7v1.2a.57 .57 0 0 0-.1 .9 .57 .57 0 0 0 .9 0 .57 .57 0 0 0-.1-.9v-.9l.2-.2h.3a.57 .57 0 0 0 .6 .6l3.5 3.6v4.1l-.2-.1v-2.3l-.1-.2a.38 .38 0 0 1 0-.7 .57 .57 0 0 0-.5-.8 .57 .57 0 0 0-.5 .8 .58 .58 0 0 0-.3 .7 .58 .58 0 0 0 .6 .4v2.8h-1.2v-2.4l-.9-.9h.4v.1a.57 .57 0 0 0 .8 .4 .57 .57 0 0 0 0-1 .57 .57 0 0 0-.8 .5h-.4l-1.5-1.6a.57 .57 0 0 0 .7-.5 .57 .57 0 0 0-.6-.6 .57 .57 0 0 0-.5 .8l-2.6-2.7v-2.6l-.1-.3h9.5v.1a.99 .99 0 0 0 .6 .7l.3 .1h1.1v.6l-.4 .4a.67 .67 0 0 0-.3 .7 .67 .67 0 0 0 .7 .5l.3 .3 1.6-.1 .2-.3v-1.7h.8l.6-.5h1.4l.1 2.1a.57 .57 0 0 0-.7 .5 .57 .57 0 0 0 .6 .6v2.5l-.5-.5a.57 .57 0 0 0 0-.9 .57 .57 0 0 0-.8 0 .57 .57 0 0 0 0 .9l.1 .5 .8 .7 .4 .1 .1 1.4a.36 .36 0 0 1-.4 .5 .6 .6 0 0 0-.3 .6 .6 .6 0 0 0 .5 .5l.5 .1h1.4a.61 .61 0 0 0 .3-.8l.1-.3a.57 .57 0 0 0 .7 .1 .57 .57 0 0 0 .3-.6l1.6-.1 2.3-2.2v4.3h-.2a.57 .57 0 0 0-.2-.7 .57 .57 0 0 0-.6 0l-.5 .1-.4 .4a.47 .47 0 0 1-.6 .2h-1.5a.45 .45 0 0 0-.6 .4v1.3a.59 .59 0 0 0-.2 .8 .59 .59 0 0 0 .8 .2l.3 .1 .3-.1 .4 .1 .2-.1 .4 .1 .2-.1a.71 .71 0 0 0 .9-.1h.1a.59 .59 0 0 0 .5 .5 .59 .59 0 0 0 .6-.4l.4-.2 .3 .4a.65 .65 0 0 0 .7 .6 .68 .68 0 0 0 1 .3h2.5l1.4-1.3 .1-.4h4.3l.3-.3v-1v1a.77 .77 0 0 0 1 .9v.4l-.5 .7v1.9h-.5l-.2 .3v1.7l.1 .3 .2 .1h1.7l.3-.1 .1-.3v-1.7l-.1-.2a.57 .57 0 0 0 .4-.8 .57 .57 0 0 0-.9-.2 .57 .57 0 0 0 .1 .9h-.3v-1.6h8.8v.3a1.42 1.42 0 0 0 2.2 1 1.42 1.42 0 0 0 0-2.4 1.42 1.42 0 0 0-2.2 1.1h-8.8l.5-.7v-1.3h.4a.47 .47 0 0 0 .7-.4l-.1-1.5a.61 .61 0 0 0 .1-.8 .61 .61 0 0 0-.8-.3l-.2 .4a.59 .59 0 0 0-.6 .5h-1l-.2 .1a.57 .57 0 0 0-.6-.6 .57 .57 0 0 0-.6 .5h-.5a.57 .57 0 0 0-.6-.7v-.2h5.4a.43 .43 0 0 0 .4 .5h1.4a.48 .48 0 0 0 .4-.5 .48 .48 0 0 0-.4-.4h-1.4l-.3 .1-.1 .3h-5.4v-.2a.57 .57 0 0 0 .6-.6l.8-.8h4.1v.9l.1 .1 .2 .1h1.4l.3-.1 .5-.5a.64 .64 0 0 0 .2-.7 .64 .64 0 0 0-.7-.4l.1-.4 .1-.1h1.2l.6 .6h.6l.3-.3v-.4l-.7-.8 .4-.1 .4-.6 .1-.9h1.7v.3a1.42 1.42 0 0 0 2.2 1.1 1.42 1.42 0 0 0 0-2.4 1.42 1.42 0 0 0-2.2 1h-1.7v-1.8l2.2-.1 .4-.4-.1-.5a.19 .19 0 0 1-.2-.2 .19 .19 0 0 1 .2-.1l.1-.4-.1-.3a.28 .28 0 0 1 0-.5v-.5a.28 .28 0 0 1 0-.5v-.5a.28 .28 0 0 1 0-.5l.1-.3h1.8v.1a.64 .64 0 0 0 .7 .5l.3 .2a.57 .57 0 0 0 0 .8 .57 .57 0 0 0 .8 0 .57 .57 0 0 0 .1-.8l.3-.3h2.4l.1 .2h.3v-.5h.4l.1 .5h.3l.1-.2h.4l.2 .2h.3v-.5h.4v.5h.4l.1-.2-.1-.3h-1.2l-.1 .3h-.4l-.1-.3h-1.2v.3h-2.4v-.4h5.6a.82 .82 0 0 0 1.1 .8 .82 .82 0 0 0 .3-1.3 .82 .82 0 0 0-1.3 .3l-.1 .2h-5.6v-.6h2.4v.3h.4v-.5h.4v.5h.4l.1-.3h.4l.1 .3h.4v-.5h.4v.5h.4l.1-.3-.2-.2h-1l-.2 .2h-.4l-.2-.2h-1l-.1 .2h-2.4l-.3-.3h-.7l-.6 .3a.57 .57 0 0 0-.6 .5h-1.8l-.4-.4-.4-.1 .4-.4 .3 .2h.8l.4-.4 .5-.1 .7-.7v-2.7h.7v.5l-.2 .2a.57 .57 0 0 0-.4 .5 .57 .57 0 0 0 .5 .6l-.5 .7v.8l.4 .4h.7a.63 .63 0 0 0 .5-.8h1.5v.1a.92 .92 0 0 0 1.1 .7l1.7-.1 .7 .1a.56 .56 0 0 0 .6-.5v-.8l-.3-.3-2.5-.1-.3 .1a.8 .8 0 0 0-1 .8h-1.5v-.4l-.1-.3 .1-.1a.57 .57 0 0 0 1-.2 .61 .61 0 0 0 .9-.3 .57 .57 0 0 0 .6-.3 .57 .57 0 0 0-.1-.6v-.7h.5l.2 .2a.57 .57 0 0 0 .8 .4 .57 .57 0 0 0 .3-.8l.4 .4h1.4l.9-.8 .1-3.7 .5 .6 .2 .3 .4 .3-.2 .1-.1 .2v.7l.3 .3-.3 .2v.8l.3 .2a.64 .64 0 0 0-.6 .7 .64 .64 0 0 0 .6 .6l-.2 .1-.1 .2v.7l.3 .3a.64 .64 0 0 0-.6 .6 .64 .64 0 0 0 .6 .6h2.2l.1-.2v-.8l-.2-.2a.64 .64 0 0 0 .6-.7 .64 .64 0 0 0-.6-.6l.2-.1 .1-.2-.1-.7-.2-.3 .2-.1 .1-.2-.1-.7-.2-.2 .2-.3v-.8l-.2-.2 .2-.3 .1-.7-.1-.2-.2-.1a.64 .64 0 0 0 .6-.6 .64 .64 0 0 0-.6-.7l.2-.2v-.8l-.1-.2h-2.3l-.3 .2-.2 .4-.6 .6-.5 .1-.7 .7v3.7l-.1 .1h-.5l-.9-.8 .3-.3a.58 .58 0 0 0 .8-.4 .58 .58 0 0 0-.6-.7 .57 .57 0 0 0-.5-.5 .64 .64 0 0 0-.5-.8l-.3-.1h-1.5v-.3a.58 .58 0 0 0 .6-.5 .58 .58 0 0 0-.5-.6l.7-.6 .4 .2h.5a.56 .56 0 0 0 .6-.5l-.1-.9a.29 .29 0 0 1-.2-.3 .29 .29 0 0 1 .2-.3l.1-.9a.56 .56 0 0 0-.6-.5h-.5l-.4 .2-.1 1 .3 .6-1.2 1.2-.1-1a.29 .29 0 0 1-.2-.3 .29 .29 0 0 1 .2-.3l.1-.9a.56 .56 0 0 0-.6-.5h-.7l-.3 .4v.8l.3 .6-.2 .2-.1 .3v.7l.2 .3a.56 .56 0 0 0 .3 .7l-.1 .8-1.1-1.1-1.2-.2h.6l.2-.2v-2.5l-.1-.2-2.3-.1-.2 .3v.7a.57 .57 0 0 0-.5 .5 .57 .57 0 0 0 .5 .6l.1 .8 .8 .1 .2 .4h-2.7l-.4-.4h.4l.2-.1 .1-.8a.57 .57 0 0 0 .4-.6 .57 .57 0 0 0-.5-.5v-.7l-.2-.3-2.3 .1-.1 .2v2.5l.3 .2h.7l1.1 1.2h1.2l-.5 .3-.1-.3-.4 .1v1.2h.4l.1-.2 .6 .3-.1 .1a.29 .29 0 0 1-.3 .2 .29 .29 0 0 1-.3-.2l-1-.1-.3 .2-.1 .2h-.9l-.4-.3-.4-.2-.3 .2-.2 .2a.25 .25 0 0 1-.3 .3h-.1l-.1-.3-.3-.4-.4-.1h3.5l.1 .1 .4 .1v-.5h-.4l-.1 .3h-3.5l-.1-.3-.3-.1h-1.2l-.4 .3v.9a.57 .57 0 0 0 .6 .5h1l.3-.2v1.4h-1.6a.58 .58 0 0 0-.8 .2 .58 .58 0 0 0 .4 .8l.1 1h-3.5l.9-1 .1-1.4h1.4a.45 .45 0 0 0 .7-.4l-.1-2.7h.6l.2 .2h.5v-.6h.4v.6h.5l.2-.2h3.6l.1 .3h.4v-.5h-.4l-.1 .2h-3.6v-.4h-1.7l-.1 .4h-.6v-.8l.3-.4h.3l.1 .4h.6v-.5h.4v.5h.7v-.4l-.2-.2h-1.4l-.2 .2h-.3l3.9-3.8 3.5-.1 1.2-1.1 .1-.2 1.3-.1 .2-.2v-.6h.2l.1 .7 .2-.1v-.3h1.7l.2 .2h.7l.1-.3h.4v.3h.8l.2-.1-.1-.2-4 .1v-.2l-.5-.1v-.3h2.2v.1h1v-.2h.4v.2h.9l.1-.1-.2-.2h-2l-.2 .2h-2.2l-.1-.8h.3v.7h.3v-.5l-.1-.2h-.5l-.3-.1h-3v-.2h5.4v.3a.47 .47 0 0 0 .5 .5h1.9l.3-.3v-.5a.47 .47 0 0 0-.4-.5l-1.9 .1-.2 .1-.2 .3h-5.4a.57 .57 0 0 0-.8-.2 .57 .57 0 0 0-.2 .8v1.4l.2 .2 .5 .1-.2 .1-3 .1-5.1 5-.1-.6a.28 .28 0 0 1-.2-.3 .28 .28 0 0 1 .2-.2l.1-.9a.56 .56 0 0 0-.6-.6h-.5l-.3 .2h-2.9a.66 .66 0 0 0-.6 .5 .66 .66 0 0 0 .4 .8l.1 .3 .3 .1v.3a.59 .59 0 0 0-.4 .7 .59 .59 0 0 0 .7 .4l-.1 2.7v-.9l-.2-.2-.2-.1h-1.2v-.3a.6 .6 0 0 0-.2-.7 .6 .6 0 0 0-.7-.1 .57 .57 0 0 0-.8 .6l-.3-.1a.63 .63 0 0 0-.9-.5 .57 .57 0 0 0-.8 .3 .57 .57 0 0 0 .3 .8h-.3l-.2 .3v1.5a.62 .62 0 0 0 .5 .8 .62 .62 0 0 0 .7-.6l.8 .1a.58 .58 0 0 0 .5 .4 .58 .58 0 0 0 .6-.4l-.9 .9-5.5 .1-1.8 1.7v1l-.9-.7-1.9-.1v-1.9a.45 .45 0 0 0-.4-.6h-1.3h-.2a.57 .57 0 0 0-.8-.1 .57 .57 0 0 0-.3 .6h-.1l-.5-.4a.59 .59 0 0 0-.2-.8 .59 .59 0 0 0-.8 .2 .59 .59 0 0 0 .2 .8l.9 .9 .8 .1v.3a.61 .61 0 0 0-.1 .8 .61 .61 0 0 0 .7 .2v1.4h-.5l-1-.9-1.5-.1h-.2h-1.6l-.1 .3-.1 .5a.57 .57 0 0 0-.6 .6 .57 .57 0 0 0 .7 .5v3.1h-.9a.57 .57 0 0 0-.6-.5 .57 .57 0 0 0-.5 .5h-9.5l-1.3-1.2a.57 .57 0 0 0-.5-.6 .57 .57 0 0 0-.6 .5h-5.5v-.2l-2.7 .1 .1-.3v-.5l-.3-.5h.9v.8l.3 .3h1.5l.2-.1 .1-.3v-2.3a.56 .56 0 0 0 .7-.2h8.3v.1a.57 .57 0 0 0 .8 .5 .57 .57 0 0 0 0-1 .57 .57 0 0 0-.8 .4h-8.2a.67 .67 0 0 0-.6-.9l-.5-.1h-1.4l-.3 .1-.1 .2a.56 .56 0 0 0-.4 .7h-.9l-.4-.3h-.9l-.3-.4 .3-.2 .1-.3h4.5l.1-.3v-1.6h19.3v2.2l.1 .2 .3 .1h1.4l.2-.2v-2a.49 .49 0 0 0 0-.6 .49 .49 0 0 0-.5-.1 .58 .58 0 0 0-.6-.8 .58 .58 0 0 0-.5 .8l-.3 .1-.1 .3h-19.3a.39 .39 0 0 0-.3-.4h-1.4a.57 .57 0 0 0-.6-.1 .57 .57 0 0 0-.3 .6h-1.8l-.2-.2-.1-.3h.6l.7-.8 .4-.1 .1-.9h.5v.8a.37 .37 0 0 0 .5 .2 .61 .61 0 0 0 .6 .4 .61 .61 0 0 0 .5-.5l.1-.9-.2-.3h1.3v1.4a.61 .61 0 0 0 .9 .3h1.3l.2-.2 .1-1.5v1.4l.3 .2 3.3 .1 .3-.2-.1 .1a.58 .58 0 0 0 .4 .8 .58 .58 0 0 0 .7-.5 .57 .57 0 0 0 .7 .4 .57 .57 0 0 0 .4-.6l1.8-.1 .2 .1a.57 .57 0 0 0 .6 .7 .57 .57 0 0 0 .5-.7l4.6-.1a.2 .2 0 0 1 .2 .1 .2 .2 0 0 1 .1 .2 .58 .58 0 0 0 .6 .3 .58 .58 0 0 0 .5-.5l.2-.1a.47 .47 0 0 0 .7-.3v-1.4a.61 .61 0 0 0-.8-.3h-.3v-.9l-1.2-1.1h-1.3l-.4-.3h-.8l-.4 .3-.1 .7a.56 .56 0 0 0 .6 .6l.8-.1 .3-.3h1l.7 .6v.5h-6.4l.9-.8 1.5 .1a.56 .56 0 0 0 .6-.6l-.1-.7-.3-.3h-.9l-.3 .2h-.4l-.4-.4h-.8a.61 .61 0 0 0-.6 .5 .23 .23 0 0 1-.3-.1 .23 .23 0 0 1-.1-.2l-.3-.2h-.8a.57 .57 0 0 0-.6 .5v1a.72 .72 0 0 0 .6 .5l.4 .5h-1.4l-.3 .1-.1 1.1v-.9l-.3-.3h-3.3l-.3 .1-.1 .3-.3-.4h-1.5a.47 .47 0 0 0-.7 .4l-2.6-.1-.2 .4h-.5l-.2-.4h-1.3l-.1 .2v-.8l.1 .2h1.4l.1-.3v-.8h.5v.8l.2 .3h1.3l.1-.2a.63 .63 0 0 0 .6-.7 .63 .63 0 0 0-.8-.5h-1.2l-.2 .2v.1h-.5l-.1-.2-.2-.1v-.7l-.5-.5h29l.2-.2v-1.2h.5l.1 .3 .3 .2-.1 .4a.57 .57 0 0 0-.3 .5 .57 .57 0 0 0 .4 .5v.4l.2 .2h1.7a.56 .56 0 0 0 .7-.3v1.4l-.1-.1a.59 .59 0 0 0-.8 .6l-.3 .2-.1 1v-.8a.47 .47 0 0 0-.5-.5 .47 .47 0 0 0-.5 .5v1.4a.58 .58 0 0 0 .4 .9 .58 .58 0 0 0 .6-.8l.1 .1a.75 .75 0 0 0 1 .6l.2-.3v-.2h3.8a.22 .22 0 0 1 .2 0 .22 .22 0 0 1 .1 .2 .6 .6 0 0 0 .9 .3 .6 .6 0 0 0 .2-.8v-1.5l-.4-.3a.57 .57 0 0 0-.6-.6 .58 .58 0 0 0-1 0 .57 .57 0 0 0-.4-.5 .57 .57 0 0 0-.7 .3l-.2-.2-.3-.1v-.5l.8-.8h.3a.63 .63 0 0 0 .2 .7 .63 .63 0 0 0 .6 .1h1.6l.2-.2h1.1l.1 .2h.6l.1-.3h.4v.3l.7-.1v-.2l-3 .1v-.7h1.1v.2h.8v-.2h.4v.2h.8l-.1-.2h-3v-.6h1.1v.2h.8v-.3h.4v.3h.7l.1-.2h-3.1v-.6l1.1-.1v.2h.8v-.2h.4v.2h.7v-.2h-3v-.5l1.9 .1v-.2h.4v.2h.7v-.2l-.1-.1h-1.6l-.2 .2h-1.1v-1.3v-.2l-.3-.1h-1.5l-.2 .2v1.2l-1.7 .1-1.5 1.6-.1 .4-.3-.3h-.3v-.2a.57 .57 0 0 0 .4-.5 .57 .57 0 0 0-.4-.5l.1-1.6a.59 .59 0 0 0 .5-.7h4.1v-.2h.4v.2h.7l-.2-.2h-1.5l-.1 .2h-3.4a.57 .57 0 0 0-.9-.4h-1.4l-.2 .1-.1 .3v1.6l-.2 .1-.2 .4h-.5v-6h.5l.1 .4-.1 .4 .1 .2a.57 .57 0 0 0 .3 .9v.5l.2 .1 1.7 .1a.6 .6 0 0 0 .6-.5 .6 .6 0 0 0-.5-.7v-2.7l.5-.2h2.4a.57 .57 0 0 0 .3 .5 .57 .57 0 0 0 .7 0v.6a.64 .64 0 0 0-.3 .8l-.1 .4 .1 .2-.1 .5a.61 .61 0 0 0-.2 .7 .61 .61 0 0 0 .6 .4h1.7l.3-.2v-2.9h1.9l.1 3.8 .2 .1h1.9a.57 .57 0 0 0 .6 .2 .57 .57 0 0 0 .4-.5l.5 .3h8.2l.1-.3v-3.6l-.1-.4h9.5l.1 .5 .2 .3h2a.47 .47 0 0 0 .4-.5v-.4l-.3-.3h-1.9a.47 .47 0 0 0-.5 .4h-11.4a.57 .57 0 0 0-.7 .5 .57 .57 0 0 0 .4 .6v.8a.57 .57 0 0 0-.4 .6 .57 .57 0 0 0 .4 .5v.3h-3.8a.57 .57 0 0 0-.2-.6 .57 .57 0 0 0-.7 0h-1l-.6-.6h-.6l.1-.2h.4l.2 .2h1.3v-2h2.4v2h1.4l.1-.2v-1.7l-5.3-.1-.1 1.8h-.4v-.3a.59 .59 0 0 0 .3-.6 .59 .59 0 0 0-.5-.5 .57 .57 0 0 0-.7-.5h-1.8l-.2 .4h-1.9v-1h2l.1 .4h.8v-.4h.4v.4h.8v-.4h7.6l.1 .4h.8v-.4h.4v.4h.8v-.4h-13.8v-.1l-.2-.2-1.7 .1a.57 .57 0 0 0-.6-.3 .57 .57 0 0 0-.5 .5h-2.4l.1-.3v-.3h4.1v-.2h.4v.2h2.8l.1 .3h.8v-.4h.4v.4h.8v-.3h-4.2l-.1-.2h-1.5l-.2 .2h-3.4l-.5-.3h-1.9l-.2 .2v1.7l-.3 .2-.1 .3h-.5v-2.8h10.8l.1 .4h.8v-.4h-11.7v-3.5h1.1v.6a.69 .69 0 0 0 .7 .6 .57 .57 0 0 0-.7 .5l.1 .8 .4 .4h.7l.6-.4 .2 .1h.8l.2 .1 2.6-.1a.31 .31 0 0 1 .4-.1 .31 .31 0 0 1 .1 .3 .61 .61 0 0 0 .7 .4 .61 .61 0 0 0 .5-.5l.2-.4-.1-.9a.38 .38 0 0 1 0-.6l.1-.8-.1-.3-.4-.3h-.6a.56 .56 0 0 0-.5 .6l.1 .9a.39 .39 0 0 1-.1 .6v.2l-.4-.1h-.7l.2-.1v-.2h.3l.1 .2 .2-.1v-.1h-.7l.1-.5h.3v.2h.3v-.2h-.8l.7-.1 .2-.1 .1-.7-.2-.2h-3.6l-.3 .2 .1 .7-.2-.1v-.5a.56 .56 0 0 0-.5-.6l-.8 .1-.3 .5h-1.1v-.7h10.7v3.7l.2 .2h1.2v.7h.8v-.3l.3 .2h6.1v.1a.57 .57 0 0 0 .4 .5 .57 .57 0 0 0 .6-.2h.2l.1 .3h.8v-.4h.4v.4h.8v-.4l-2.3 .1 .2-.3-.1-.4h.1l.1 .4h.8v-.4h.4v.4l.8-.1v-.3h-2.2l-.1-.2 .2-.2 .1 .1h2l.1-.3h2.9v.1a.57 .57 0 0 0 .6 .5 .57 .57 0 0 0 .5-.4h.5l.1 .3 .7 .7 .2 .1h2.6l.9-.8h.5l.4 .3h1.8l.4-.3-.1 .5-.3-.2h-1.8a.47 .47 0 0 0-.5 .5l.1 .5 .4 .2h1.8l.4-.2 .3-.1 .4-.3v-1.6l-.5-.5-.2-.2v-.5l-.2-.3h-2l-.4 .2h-.4l-.6-.6h1.1l.1 .2h.8l.1-.3h.4v.3h.8l.2-.1-.1-.2h-2.3v.1h-1.1l-.5-.4h-3.5l-.6 .6h-.6l-.2 .1-.1 1.5-.1 .3h-2.9v-2.7h9.6v.1h1v-.2h.4v.2h.9v-.2l-2.1-.1-.2 .2h-9.6v-1.1h9.4l.1 .5 .2 .2h2.1a.6 .6 0 0 0 .8-.6 .6 .6 0 0 0-.8-.5l-2-.1-.2 .2-.2 .3h-9.4l-.3-.2h-1.6a.58 .58 0 0 0-.7 .1 .58 .58 0 0 0-.1 .8 .57 .57 0 0 0 .4 .9v.1l-.1 .1a.57 .57 0 0 0-.4 .6 .57 .57 0 0 0 .5 .5v.3h-.3l-.6 .6-.2 .9h-5.7a.63 .63 0 0 0 0-1.1l-.1-.1 .2-.3 .1-.4 .2-.1 .1 1.3h1.4v-1.9h2.4v1.9h1.5v-1.8l-.2-.2-5.1 .1-.2-.3h-.4v-.3a.57 .57 0 0 0 .6 0 .57 .57 0 0 0 .2-.5 .57 .57 0 0 0 .6-.6 .57 .57 0 0 0-.6-.6h-3.3l-.2 .1-.1 .3h-10.7v-.9l.1-.1h37.1l.1 .1v12l.2 .2h5.7l.1 .1v16h-.1h-6.6l-.2 .2v30.7l-.1 .1h-13.5v-3.3l-.2-.4-.2-.1h-4.1l.1-.8h9.2a1.08 1.08 0 0 0 1.5 0l-.8-.8-.7 .8h-9.2v-1.1h8.7v.5l.2 .3 .8-.7h.5l.8 .7a1.08 1.08 0 0 0 0-1.5l-.8 .8h-.5l-.8-.8-.1 .2-.1 .5h-8.7v-.9h9.2l.7 .7 .8-.7-.2-.2-.4-.1a.99 .99 0 0 0-.9 .3h-9.2v-1.5l-.3-.3-2.6-.1v-1.7h1.2l.3 .4 .3 .2h.2v-.8h.4v.8l.5-.2 .3-.4v-.2h-2v.2h-1.2v-.3h4.5v.1a.57 .57 0 0 0 .9 .4 .57 .57 0 0 0 0-.9 .57 .57 0 0 0-.9 .4h-4.5v-.4h1.2v.1h.8v-.7h.4v.7h.8v-.1a1.07 1.07 0 0 0-1-.7 1.07 1.07 0 0 0-1 .7h-1.2v-4.5l-.4-.4h-10.4l-.3 .4v4.3h-3.4l-.4 .3v6.9h-2.8v-4.1l-.3-.4-4.5-.1v-2.3h.2v1l.3 .3h1.2l.2-.3 .2 .1v-.4h.4v.4h.2l.3-.3 .2 .3h.2v-.4h-.4v.1l-.1-.1h-.8v-.4h.8l-.2-.4 .3-.2 .2 .2-.2 .4h.8v.8l.4-.2v.1a.82 .82 0 0 0 1.3 0 .82 .82 0 0 0 1.2 .1 .82 .82 0 0 0 0-1.3 .82 .82 0 0 0 0-1.2 .82 .82 0 0 0-1.2 .1 .82 .82 0 0 0-1.3 0 .82 .82 0 0 0-1.2 0 .82 .82 0 0 0-1.3 0 .82 .82 0 0 0-1.1-.1 .82 .82 0 0 0-.2 1.1l-.2 .3h-.2v-3.3h.9v.2a.57 .57 0 0 0 .4 .4 .57 .57 0 0 0 .6-.1h6.7l.2 .1h.9v-.6h.4l.1 .6h.8l.2-.1v-.4l-2.5-.1-.1 .5h-6.7a.57 .57 0 0 0-.2-.9 .57 .57 0 0 0-.8 .4h-.9v-1.4l-.4-.3h-9.8l-.4 .4v3.2h-2.8l-.4 .4v3.3h-5.7l-.3-.3h-.7v-2.9h1.5a.56 .56 0 0 0 .3-.6v-.7h.3v.7h.3v-.7h-.6v-1h.3v.7h.3v-.7h-.6v-.3h.8v1.4l.2 .7 .2 .1h1.7v.1a.57 .57 0 0 0 .5 .9 .57 .57 0 0 0 .5-.9v-.4h.6l.3-.3v-.9h.6l.1 .1h.9l.1-.6h.4v.6h.9l.1-.1v-.5h-2.5v.5h-.6v-1.2h.6v.4h1.1v-.6h.4v.6h1v-.5l-.1-.1h-2.2l-.2 .2h-.6v-2.7l-.3-.4h-8.3l.1-.2v-1.5h4.3v1.4a.61 .61 0 0 0 .9 .3h6.4h.2l-.3 .3v.7a.56 .56 0 0 0 .5 .5h.7l.3-.1 .1-.3 .1-.6v.5a.56 .56 0 0 0 .6 .5h.6l.4-.2h8.1v.7l.2 .3v.4a.57 .57 0 0 0 .4 .5 .57 .57 0 0 0 .6-.1h6.9l.1 .4h1v-.6h.4v.6l1.1-.1v-.4l-.2-.1h-2.2l-.2 .2h-6.9l.2-.4v-.4l.1-.1h1.1l.2 .1 .3 .1h.6l.4-.2h1.2l.4 .2h.8l.3-.3v-.8a.56 .56 0 0 0-.5-.5h-.6l-.4 .2h-1.2l-.2-.2h-.3h-.6l-.4 .2h-1.1l-.3-.2h-.6l-.4 .1-.2 .4h-8.1l.1-.2v-.7l-.4-.4h1l.3-.3v-1.5l-.1-.2-.3-.1a.57 .57 0 0 0-.6-.7 .57 .57 0 0 0-.5 .7h-.3a.57 .57 0 0 0-.5-.7 .57 .57 0 0 0-.6 .4 .58 .58 0 0 0-.7-.4 .58 .58 0 0 0-.5 .7h-1.8a.57 .57 0 0 0-.5-.7 .57 .57 0 0 0-.6 .7h-1.9a.57 .57 0 0 0-.6-.7 .57 .57 0 0 0-.5 .7h-.8a.47 .47 0 0 0-.7 .4h-4.3v-.3l-.3-.2h-1.9l-.1 .3v1.7l.1 .2-.4 .1-.3 .3v2.4h-.4v-.5h-1.6v.5h-2.1l-.3 .3v4l.2 .4h4.2l.4 .4h2.1v.4h-.6v.9h-1v.5h-.5a.22 .22 0 0 1-.4 0h-.4v-.5h-1.6v.5h-2l-.3 .2-.1 .2v4l.1 .2 .3 .2h3.9l.3-.1 .3 .1 3.5 .1a.57 .57 0 0 0 .8-.4l.3 .2h11.9l.3-.4v-1.2h.4l.4 .1 .4-.1-.4-.4-.4 .4h-.4v-.6l.2 .3 .3-.3h.6l.3 .3 .2-.4-.2-.3-.3 .4h-.6l-.3-.4-.2 .4v-.7h.4l.4 .4 .4-.4-.4-.1-.4 .1h-.4v-1.7h1.6v4.1l.1 .3 .4 .2h6.5v3.5h-55.6v-1.2h.3l.1 .2h.5l.1-.9h.3l.1 .9 .6-.1 .1-.6h6.4v.7l.2 .2a.64 .64 0 0 0 .6 .8 .64 .64 0 0 0 .7-.7h3.5l.3-.3v-.8l-.2-.3h-2.3l-.1 .1h-1.2l-.3-.3h-.6l-.4 .2-.2 .4h-6.4l-.1-.2h-1.7v.7h-.3v-1.7h.3v.6h.7v-.8h.3v.8h.7l.1-.6-.2-.2h-1.5l-.1 .2h-.3v-.6h8.5v.6a.56 .56 0 0 0 .6 .6l.6-.1 .3-.2 .1-.9-.1-.4a.64 .64 0 0 0-.7-.7 .64 .64 0 0 0-.6 .7l-.2 .4h-8.5v-3.3h4.5a.79 .79 0 0 0 .7-.7v-.4h3.5l.1 .2h.5l.1-1.8h.4v1.8h.5l.2-.2-.1-1.6h-1.7v1.6h-3.5v-3.6h3.5v1.6h.7v-1.7h.4v1.7h.6l.1-1.6-.2-.2h-1.5l-.1 .2h-3.5v-.3l-.2-.3 .2-.4v-2.6h5.3v5l.2 .4-.2 .4v5.3l.2 .4 .4 .3 .1 .7 2.4 .1 .2-.4v-.4h.7v2.3l.2 .3h3.4l.3 .1h.6l.4-.2h1.1l.3 .2h.6a.56 .56 0 0 0 .5-.6v-.7l-.4-.4h-.7l-.3 .2h-1.1l-.3-.2h-.6l-.6 .3 .1-.3-.1-.3 .6 .3 .7-.1 .3-.3h1l.1 .2h.3v-.5h.4l.1 .5 .4-.1v-.4h-1.3v.3h-1v-1h1v.3h.4v-.5h.4v.5h.5v-.3l-.1-.2h-1.1l-.1 .2h-1l-.1-.2a.96 .96 0 0 0 0-1l.2 .1h.7v-.7h.4v.7h.7l.2-.1v-.5l-2.1-.1-.1 .6a.84 .84 0 0 0-1.2-.2 .84 .84 0 0 0-.1 1.2h-1.9v-2.5h3.2l.1 .6h.8v-.7h.4v.7h.8v-.7l-.1-.1h-1.8l-.2 .2h-3.2v-.4h6.4a.82 .82 0 0 0 .6-.7v-2h4.4l.1 .4h.6v-.5h.4v.5h.6l.1-.4h1.1l.1 .4h.6v-.6h-.5l-.2 .2h-1.1l-.2-.2h-1.4l-.2 .2h-4.4v-2.3a.79 .79 0 0 0-.7-.7h-6.3v-.5h3.2l.2 .2h.7v-.7h.4v.7h.7l.2-.2-.1-.5h-2l-.1 .5h-3.2v-1.4h3.2l.1 .5h.8v-.7h.4v.7h.8l.1-.5-.2-.2h-1.8l-.2 .2h-3.2v-.7h9.3l.1-.2v-1.1h2l.1 .4h.6v-.5h.4v.5h.6l.1-.4-.2-.2h-1.4l-.2 .2h-2v-2.2h2.3l.3 .4 .5 .2v-.8h.4v.8h.1l.5-.3 .2-.5h-2v.2h-2.3v-.7h2.3v.2h.8v-.8h.4v.8h.8a1.02 1.02 0 0 0-1-.9 1.02 1.02 0 0 0-1 .7h-2.3v-2.3h2.1v.2a1.19 1.19 0 0 0 1.4 1.1 1.19 1.19 0 0 0 1-1.4l.2-.7h.4a1.2 1.2 0 0 0 0 1.8 1.2 1.2 0 0 0 1.8-.3l.7-.3 .3-.3h.9l.1 .4a.47 .47 0 0 0 .3 .7h1.4a.61 .61 0 0 0 .3-.8l.1-1.5a.57 .57 0 0 0 .7 .2 .57 .57 0 0 0 .2-.7h7.7v.1a.57 .57 0 0 0 .9 .4 .57 .57 0 0 0 0-.9 .57 .57 0 0 0-.9 .4h-7.7l-1-1v-.4v-.3l.5-.1 .3-.2 .2-.5v-.9h.1a.57 .57 0 0 0 .8 .6 .57 .57 0 0 0 .1-1 .57 .57 0 0 0-.9 .3v.1h-.1v-.5a.57 .57 0 0 0-.2-.7 .57 .57 0 0 0-.8 .2v-3h1.6v.1a.57 .57 0 0 0 .9 .5 .57 .57 0 0 0 0-1 .57 .57 0 0 0-.9 .4h-1.6v-.9l-.2-.3h-1.5l-.3 .1-.1 8.9h-.9l-.5-.3h-.8a1.17 1.17 0 0 0 .1-1.7 1.17 1.17 0 0 0-1.7 0 1.17 1.17 0 0 0 .1 1.7h-.7a1.81 1.81 0 0 1-1.5 .5l-.5 .4-.3 .6h-2.1v-1.1l-.1-.1h-20.2l-.1-.1v-.7h4.4l.2 .2h2.8l.1-2.4h4.9l.1 2.4h2.9l.2-.2v-.5h6.9a1.17 1.17 0 0 0 1.6 1.2 1.17 1.17 0 0 0 .4-2 1.17 1.17 0 0 0-1.9 .5l-.1 .3h-6.9l-.1-1.7h-11.1v2.2h-4.4v-3.1h22.5a1.17 1.17 0 0 0 1.2 1.3 1.17 1.17 0 0 0 1.1-1.3h.3v.2a1.17 1.17 0 0 0 1.7 .9 1.17 1.17 0 0 0 0-2 1.17 1.17 0 0 0-1.7 .9h-.3v-.2a1.17 1.17 0 0 0-1.2-.8 1.17 1.17 0 0 0-1.1 1h-22.5v-2.5h22.5v.2a1.17 1.17 0 0 0 1.3 1.1 1.17 1.17 0 0 0 1-1.3h.3v.2a1.17 1.17 0 0 0 1.7 .9 1.17 1.17 0 0 0 0-2 1.17 1.17 0 0 0-1.7 .9h-.3v-.3a1.17 1.17 0 0 0-1.2-.8 1.17 1.17 0 0 0-1.1 1.1h-22.5v-3.8h4.4v2.2h3.1v-2.3h4.9v2.3h3.2v-2.2l-.2-.2h-10.8l-.2 .2h-4.4v-4.1l1.7-.5 .8-.4 .7-.6 1-1 .5-1 .4-1.1 .2-1.1zM189.6 88.9h1.9l.1 .1v.3l-.1 .1h-1.8l-.1-.1zM189.6 90.2l1.9-.1 .1 .1v.4l-.1 .1h-1.8l-.1-.1zM189.6 91.4h1.9l.1 .1v.4l-.1 .1h-1.8l-.1-.1z"/>
<path d="M189.6 92.7h1.9l.1 .1v.3l-.1 .2h-1.8l-.1-.2zM189.6 94l1.9-.1 .1 .1v.4l-.1 .1h-1.8l-.1-.1zM189.6 95.2h1.9l.1 .1v.4l-.1 .1h-1.8l-.1-.1zM189.6 96.5h1.9l.1 .1v.3l-.1 .2h-1.8l-.1-.2zM189.6 97.8l1.9-.1 .1 .2v.3l-.1 .1h-1.8l-.1-.1zM193.2 93.9h1.4v.5h-1.4zM193.2 93.3h1.4v.4h-1.4zM193.2 92.6h1.4v.5h-1.4zM193.2 92h1.4v.4h-1.4zM193.2 91.3h1.4v.5h-1.4zM193.2 90.7h1.4v.4h-1.4zM193.2 90h1.4v.5h-1.4z"/>
<path d="M193.7 96.7h.9l.1 .2v.6l-.2 .1h-.7l-.1-.2zM195.5 96.7h.9l.1 .2-.1 .6-.2 .1h-.7l-.1-.2zM197.6 96.7h.8l.1 .2v.6l-.2 .1h-.7l-.1-.2zM199.1 90h1.4v.5h-1.4zM199.1 90.7h1.4v.4h-1.4zM199.1 91.3h1.4v.5h-1.4zM199.1 92h1.4v.4h-1.4zM199.1 92.6h1.4v.5h-1.4zM199.1 93.3h1.4v.4h-1.4zM199.1 93.9h1.4v.5h-1.4zM199.3 96.7h.9l.1 .2-.1 .6-.2 .1h-.7l-.1-.2zM202.1 90.5h2.5v2.3h-2.5z"/>
<path d="M202.1 96.8h.9v.8h-.9zM202.1 94.9h.9v.8h-.9zM203.8 85h1.5v.4h-1.5zM203.8 84.3h1.5v.5h-1.5zM203.8 83.7h1.5v.4h-1.5zM203.8 83h1.5v.5h-1.5zM203.8 82.4h1.5v.4h-1.5zM203.8 81.7h1.5v.5h-1.5zM203.8 81.1h1.5v.4h-1.5zM203.8 80.4h1.5v.5h-1.5zM204.1 95.9h.9v.8h-.9zM206.4 90.5h2.5v2.3h-2.5z"/>
<path d="M205.9 95.9l.9-.1 .1 .2v.6l-.2 .1h-.7l-.1-.2zM207.7 95.9l.9-.1 .1 .2-.1 .6-.2 .1h-.7l-.1-.2zM209.7 80.4h1.5v.5h-1.5zM209.7 81.1h1.5v.4h-1.5zM209.7 81.7h1.5v.5h-1.5zM209.7 82.4h1.5v.4h-1.5zM209.7 83h1.5v.5h-1.5zM209.7 83.7h1.5v.4h-1.5zM209.7 84.3h1.5v.5h-1.5zM209.7 85h1.5v.4h-1.5zM209.6 95.1h1.5v2.3h-1.5zM210.4 90.4l.7-.1 .1 .1 .1 .7-.1 .2h-.6h-.2z"/>
<path d="M210.4 92.1l.7-.1 .1 .1 .1 .8-.1 .1-.6 .1-.2-.1zM211.8 95.1h1.5v2.3h-1.5zM212.4 89.9h1v1h-1zM212.4 92.4h1v1h-1zM186.8 88.3v-.1h30l.1 .1v9.5l-2.1-2-.3-.1h-.8v-.7l-.2-.2v-1.1l.2-.3v-1l-.2-.2h-1.3l-1-.5h-.7l-.4 .4-.1 .8a.56 .56 0 0 0 .6 .5h.6l.3-.2 .7 .5v1.1h-.5l-.2 .2v2.4l.1 .2 .2 .1h1.7l.2-.2v-.7h.6l2 2.1h-29.5v-.1v-.5h2.6l.1 .2h1v-.4h.1l.1 .4h.9l.2-.1-.1-.3h-2.3v.2h-2.6v-.6h2.6v.3h1.1v-.4h.1v.4l1.2-.1v-.2l-.2-.2h-2l-.2 .2h-2.6v-.9h1.9a.63 .63 0 0 0 .8 .5l2 .1a.51 .51 0 0 0 .4-.7l.9 .9h.6l.4 .3 1-.1a.29 .29 0 0 1 .3-.1 .29 .29 0 0 1 .3 .1l.9 .1 .5-.3h.4l.3 .3h.8a.56 .56 0 0 0 .6-.5l-.1-.7-.4-.3h-.8l-.4 .3h-.4l-.5-.3h-.7l-.6 .3-.3-.3h-.8h-.3l-.2 .3h-.2l-1-.9-.3-.1v-.4a.47 .47 0 0 0-.4-.4h-2v-.1h2a.47 .47 0 0 0 .4-.4h1.1l.1 .2h.7v-.4h.2v.4h.6l.2-.1v-.2l-1.8-.1v.2h-1.1v-.5l-.3-.3h-2.1v-.1l2 .1 .3-.2 1.1-.1v.5l.1 .3h1.8l.1-.2h2.9l.8 .7 .8 .1v1.7l-.4 .2-.1 .3v.6l.2 .3 .3 .1h.9l.3-.3 .4-.1 .8-.8v1l.2 .2a.62 .62 0 0 0 .5 .5 .62 .62 0 0 0 .7-.5l.1-.2v-1h.5l.3 .3 2.6 .1 .4-.3 .1-.8 .1 .5a.56 .56 0 0 0 .6 .6l1.3-.1 .1 .5 .2 .2h1.7l.2-.3-.1-2.5-.2-.1h-1.6l-.2 .2-.1 .6-1.5-.1-.2 .1-.3 .4a.56 .56 0 0 0-.5-.5h-2.6l-.3 .3h-.6v-.4h-1.2v.4l-.6 .1-.8 .8-.4-.3v-1.5h1.7l.1 .3h.5v-.4h.1v.4h.6v-.4l-.2-.1h-.9l-.2 .2h-1.7v-.2h.4l.2-.2v-.6l.4-.5v-1.8l-.4-.5v-.6h1v2.4l.2 .3h2.6l.2-.1 .1-.3h1.3l.1 .2h1.2l.1-1.2h.1v1.2h1.2l.2-.1-.1-1.1h-2.8v1h-1.3v-.5a.63 .63 0 0 0 .6-.6 .63 .63 0 0 0-.6-.6v-.6h1.3v1.1h1.4v-1.2h.1v1.2h1.3l.1-1.1h.9v.6a.56 .56 0 0 0 .6 .6l.6-.1a.59 .59 0 0 0 .4-.7h.6l.1 .2h.4l.1-.6h.1v.6h.6v-.2v-.4h-1.3v.4h-.6v-.5l-.2-.5h.8v.5h.6v-.6h.1v.6h.6v-.5l-.1-.1-1-.1-.2 .2h-.8a.68 .68 0 0 0-.7-.4 .68 .68 0 0 0-.6 .7l-.1 .3h-.9l-.2-.2h-2.5l-.2 .2h-1.3l-.1-.2-.2-.1h-2.5l-.2 .1-.1 .2h-1v-.5l-.2-.3h-1.5a.67 .67 0 0 0-.8 .9l-.3 .4-.1 .8h-3l.1-.3a.57 .57 0 0 0 .5-.7 .57 .57 0 0 0-.7-.4l-1.8-.1-.1 .3v.4l-.4-.4h-.7l-.1-.1h-2.3l-.7 .7v.2v4.5l.2 .4-.2 .5h-1.9v-6.7h2.6v.3h1.1v-.4h.1v.4h1.1l.1-.4h1.2v.2h.8v-.3h.2v.3h.8v-.2l-.1-.2h-1.5l-.2 .2-3.4-.1-.2 .2h-2.6v-1h1.6l.2 .5 .3 .1 2.6 .1a.47 .47 0 0 0 .4-.5v-.5l-.4-.3-2.6 .1a.57 .57 0 0 0-.5 .5h-1.6zM80.5 100.3h.9v.2v.6l-.2 .1-.7-.1-.1-.2zM80.5 102l.9-.1v.2v.6l-.2 .1h-.7l-.1-.2zM82.2 100.3h.9l.1 .2-.1 .6-.1 .1-.8-.1-.1-.2zM82.2 102l.9-.1 .1 .2-.1 .6-.1 .1h-.8l-.1-.2zM70.5 103.7l.1-.1h14v1.4l.2 1.3 .5 1.1 .7 1 .9 .8 1.2 .8 1 .3 1.2 .2 .1 .1v14.1l-.1 .1h-19.7l-.1-.1v-.7h4.4l.2 .2h2.9v-2.4h5v2.4h2.9l.2-.2v-2.2h-11.1l-.1 2.2h-4.4v-9.4h4.4l.1 2.2h3v-2.3h5v2.3h3.1v-2.2l-.2-.2h-10.8l-.2 .2h-4.4zM112.7 114.4h.9l.1 .2-.1 .6-.1 .1-.8-.1-.1-.2zM114.2 107h1.1v.7h-1.1z"/>
<path d="M114.2 106.1h1.1v.6h-1.1zM114.2 105.1h1.1v.7h-1.1zM114.5 114.4h.9v.2v.6l-.2 .1-.7-.1-.1-.2zM114.6 112h.9l.1 .2-.1 .6-.1 .1-.8-.1v-.2zM114.6 110.5l.9-.1 .1 .2-.1 .7h-.1h-.8v-.2zM114.6 108.9h.9l.1 .2-.1 .6-.1 .1h-.8v-.2zM116.4 106.1h1.1v.6h-1.1zM116.4 105.1h1.1v.7h-1.1zM116.4 107h1.1v.7h-1.1zM116.4 112h.9l.1 .2-.1 .6-.2 .1-.7-.1-.1-.2zM116.4 110.5l.9-.1 .1 .2-.1 .7h-.2h-.7l-.1-.2zM116.4 108.9h.9l.1 .2-.1 .6-.2 .1h-.7l-.1-.2z"/>
<path d="M116.5 114.4h.9l.1 .2v.6l-.2 .1-.8-.1v-.2zM118 107h1.1v.7h-1.1zM118 106.1h1.1v.6h-1.1zM118 105.1h1.1v.7h-1.1zM117.4 101.2h.1h1.1l.1 .2-.1 .8-.2 .1-1-.1-.1-.1zM118.3 114.4h.9l.1 .2-.1 .6-.2 .1-.7-.1-.1-.2zM120.2 106.1h1.1v.6h-1.1zM120.2 105.1h1.1v.7h-1.1zM120.2 107h1.1v.7h-1.1zM120.1 101.1h.7h.1l.1 .8-.1 .2h-.6l-.2-.1zM120.6 109.1h1.4v.2l-1.4 .1zM120.6 109.6h1.4v.2l-1.4 .1z"/>
<path d="M120.6 110.1h1.4v.2l-1.4 .1zM120.6 110.6h1.4v.2l-1.4 .1zM120.6 111.1h1.4v.2l-1.4 .1zM120.6 111.6h1.4v.2l-1.4 .1zM120.6 112.1h1.4v.2l-1.4 .1zM120.6 112.6h1.4v.2l-1.4 .1zM120.6 113.1h1.4v.2l-1.4 .1zM120.6 113.6h1.4v.2l-1.4 .1zM120.6 114.1h1.4v.2l-1.4 .1zM120.6 114.6h1.4v.2l-1.4 .1zM120.6 115.1h1.4v.2l-1.4 .1zM120.6 115.6h1.4v.2l-1.4 .1z"/>
<path d="M120.6 116.1h1.4v.2l-1.4 .1zM120.6 116.6h1.4v.2l-1.4 .1zM120.6 117.1h1.4v.2l-1.4 .1zM120.6 117.6h1.4v.2l-1.4 .1zM120.6 118.1h1.4v.2l-1.4 .1zM120.6 118.6h1.4v.2l-1.4 .1zM120.6 119.1h1.4v.2l-1.4 .1zM120.6 119.6h1.4v.2l-1.4 .1zM123.1 106.6h.3l-.1 1.5-.2-.1zM122.6 101.3h.8v.9h-.8zM123.6 106.6h.3l-.1 1.5-.2-.1zM124.1 106.6h.3l-.1 1.5-.2-.1z"/>
<path d="M123.6 99.3h.8v.9h-.8zM124.6 106.6h.3l-.1 1.5-.2-.1zM125.1 106.6h.3l-.1 1.5-.2-.1zM124.5 101.3h.8v.9h-.8zM125.6 106.6h.3l-.1 1.5-.2-.1zM126.1 106.6h.3l-.1 1.5-.2-.1zM126.6 106.6h.3l-.1 1.5-.2-.1zM127.1 106.6h.3l-.1 1.5-.2-.1zM127.6 106.6h.3l-.1 1.5-.2-.1zM128.1 106.6h.3l-.1 1.5-.2-.1zM128.6 106.6h.3l-.1 1.5-.2-.1zM129.1 106.6h.3l-.1 1.5-.2-.1z"/>
<path d="M129.6 106.6h.3l-.1 1.5-.2-.1zM130.1 106.6h.3l-.1 1.5-.2-.1zM130.6 106.6h.3l-.1 1.5-.2-.1zM130.4 104.1h.9l.1 .1 .1 1-.1 .2-.8 .1-.2-.1v-1.1zM131.1 106.6h.3l-.1 1.5-.2-.1zM131.6 106.6h.3l-.1 1.5-.2-.1zM132.1 106.6h.3l-.1 1.5-.2-.1zM131.9 101.1l.9-.1 .1 .2-.1 .7h-.2h-.7l-.1-.2zM132.6 106.6h.3l-.1 1.5-.2-.1zM133.1 106.6h.3l-.1 1.5-.2-.1zM132.5 104.1h.8l.2 .1 .1 1-.1 .2-.8 .1-.2-.1-.1-1.1zM133.6 106.6h.3l-.1 1.5-.2-.1z"/>
<path d="M134.1 106.6h.3l-.1 1.5-.2-.1zM133.6 101.1l.9-.1 .1 .2v.7h-.2h-.7l-.1-.2zM134.6 106.6h.3l-.1 1.5-.2-.1zM135.1 106.6h.3l-.1 1.5-.2-.1zM134.6 104.4l.9-.1 .1 .2-.1 .7h-.2h-.7l-.1-.2zM135.6 106.6h.3l-.1 1.5-.2-.1zM136.1 106.6h.3l-.1 1.5-.2-.1zM136.6 106.6h.3l-.1 1.5-.2-.1zM136.3 104.4l.9-.1 .1 .2v.7h-.2h-.8v-.2zM137.1 106.6h.3l-.1 1.5-.2-.1zM137.6 106.6h.3l-.1 1.5-.2-.1zM138.1 106.6h.3l-.1 1.5-.2-.1z"/>
<path d="M138.6 106.6h.3l-.1 1.5-.2-.1zM139.1 106.6h.3l-.1 1.5-.2-.1zM139.6 106.6h.3l-.1 1.5-.2-.1zM140.1 106.6h.3l-.1 1.5-.2-.1zM140.6 106.6h.3l-.1 1.5-.2-.1zM141.9 119.6h1.4l.1 .2-1.5 .1zM141.9 119.1h1.4l.1 .2-1.5 .1zM141.9 118.6h1.4l.1 .2-1.5 .1zM141.9 118.1h1.4l.1 .2-1.5 .1zM141.9 117.6h1.4l.1 .2-1.5 .1zM141.9 117.1h1.4l.1 .2-1.5 .1zM141.9 116.6h1.4l.1 .2-1.5 .1z"/>
<path d="M141.9 116.1h1.4l.1 .2-1.5 .1zM141.9 115.6h1.4l.1 .2-1.5 .1zM141.9 115.1h1.4l.1 .2-1.5 .1zM141.9 114.6h1.4l.1 .2-1.5 .1zM141.9 114.1h1.4l.1 .2-1.5 .1zM141.9 113.6h1.4l.1 .2-1.5 .1zM141.9 113.1h1.4l.1 .2-1.5 .1zM141.9 112.6h1.4l.1 .2-1.5 .1zM141.9 112.1h1.4l.1 .2-1.5 .1zM141.9 111.6h1.4l.1 .2-1.5 .1zM141.9 111.1h1.4l.1 .2-1.5 .1zM141.9 110.6h1.4l.1 .2-1.5 .1z"/>
<path d="M141.9 110.1h1.4l.1 .2-1.5 .1zM141.9 109.6h1.4l.1 .2-1.5 .1zM141.9 109.1h1.4l.1 .2-1.5 .1zM143.2 101.4h.9l.1 .2-.1 .6-.2 .1h-.7l-.1-.2zM143.2 99.2h.8v.9h-.8zM144.9 101.4h.9l.1 .2v.6l-.2 .1h-.7l-.1-.2zM145.1 99.2h.8v.9h-.8zM146.9 109.1h1.4v.2l-1.4 .1zM146.9 109.6h1.4v.2l-1.4 .1zM146.9 110.1h1.4v.2l-1.4 .1zM146.9 110.6h1.4v.2l-1.4 .1zM146.9 111.1h1.4v.2l-1.4 .1z"/>
<path d="M146.9 111.6h1.4v.2l-1.4 .1zM146.9 112.1h1.4v.2l-1.4 .1zM146.9 112.6h1.4v.2l-1.4 .1zM146.9 113.1h1.4v.2l-1.4 .1zM146.9 113.6h1.4v.2l-1.4 .1zM146.9 114.1h1.4v.2l-1.4 .1zM146.9 114.6h1.4v.2l-1.4 .1zM146.9 115.1h1.4v.2l-1.4 .1zM146.9 115.6h1.4v.2l-1.4 .1zM146.9 116.1h1.4v.2l-1.4 .1zM146.9 116.6h1.4v.2l-1.4 .1zM146.9 117.1h1.4v.2l-1.4 .1z"/>
<path d="M146.9 117.6h1.4v.2l-1.4 .1zM146.9 118.1h1.4v.2l-1.4 .1zM146.9 118.6h1.4v.2l-1.4 .1zM146.9 119.1h1.4v.2l-1.4 .1zM146.9 119.6h1.4v.2l-1.4 .1zM148.6 112.6h.4l.4 .3v1.3l.6 .6 .2 .1h.8a.68 .68 0 0 0 .9 .1h.1a.57 .57 0 0 0 .5 .6 .57 .57 0 0 0 .6-.6l.1-.1 .6 .5 2-.1-5 5h-2.2v-.3l-.1-.2h-1.1l.9-.1a.47 .47 0 0 1 .6 .1 .58 .58 0 0 0 .7-.4 .58 .58 0 0 0-.3-.7l-.3-.5a.57 .57 0 0 0 .3-.6 .57 .57 0 0 0-.7-.4v-2.2l-.3-.2h-.9l.9-.1 .3-.2zM149.4 106.6h.2v1.5l-.3-.1zM149.9 106.6h.2v1.5l-.3-.1zM149 104h1.4v.4h-1.4zM149 103.3h1.4v.5h-1.4zM149 102.7h1.4v.4h-1.4zM149 102h1.4v.5h-1.4z"/>
<path d="M149 101.4h1.4v.4h-1.4zM149 100.7h1.4v.5h-1.4zM149 100.1h1.4v.4h-1.4zM150.4 106.6h.2v1.5l-.3-.1zM150.9 106.6h.2v1.5l-.3-.1zM151.4 106.6h.2v1.5l-.3-.1zM151.9 106.6h.2v1.5l-.3-.1zM152.4 106.6h.2v1.5l-.3-.1zM152.9 106.6h.2v1.5l-.3-.1zM153.4 106.6h.2v1.5l-.3-.1zM153.9 106.6h.2v1.5l-.3-.1zM154.4 106.6h.2v1.5l-.3-.1z"/>
<path d="M154.9 106.6h.2v1.5l-.3-.1zM155.4 106.6h.2v1.5l-.3-.1zM155.9 106.6h.2v1.5l-.3-.1zM154.9 100.1h1.4v.4h-1.4zM154.9 100.7h1.4v.5h-1.4zM154.9 101.4h1.4v.4h-1.4zM154.9 102h1.4v.5h-1.4zM154.9 102.7h1.4v.4h-1.4zM154.9 103.3h1.4v.5h-1.4zM154.9 104h1.4v.4h-1.4zM154.9 112.1l.5-.5h1.6l-.4 .4zM156.4 106.6h.2v1.5l-.3-.1z"/>
<path d="M156.9 106.6h.2v1.5l-.3-.1zM157.4 106.6h.2v1.5l-.3-.1zM157.9 106.6h.2v1.5l-.3-.1zM148.6 121.1l2.5-.1 5.3-5.2h1.9a.56 .56 0 0 0 .1 .7v.9l-.5 .6a.57 .57 0 0 0-.7-.3 .57 .57 0 0 0-.4 .6l-4.1 4h-.3a.57 .57 0 0 0-.5-.7 .57 .57 0 0 0-.5 .7h-1.1a.57 .57 0 0 0-.3-.6 .57 .57 0 0 0-.7 .1h-.7zM158.4 106.6h.2v1.5l-.3-.1zM158.9 106.6h.2v1.5l-.3-.1zM157.9 104h1.5l.1 .1v.3l-.1 .1h-1.4l-.1-.1zM157.9 103.4l1.5-.1 .1 .1v.3l-.1 .1h-1.4l-.1-.1zM157.9 102.7h1.5l.1 .1v.3l-.1 .1h-1.4l-.1-.1zM157.9 102.1l1.5-.1 .1 .1v.3l-.1 .1h-1.4l-.1-.1zM159.4 106.6h.2v1.5l-.3-.1zM159.9 106.6h.2v1.5l-.3-.1z"/>
<path d="M160.4 106.6h.2v1.5l-.3-.1zM160.9 106.6h.2v1.5l-.3-.1zM161.4 106.6h.2v1.5l-.3-.1zM161.9 106.6h.2v1.5l-.3-.1zM159.9 109.2a.57 .57 0 0 0 .7 .2 .57 .57 0 0 0 .4-.6l.1-.2a.57 .57 0 0 0 .7 .4 .57 .57 0 0 0 .4-.7l1.4 .1v.9l-.4 .4h-3.8zM162.4 106.6h.2v1.5l-.3-.1zM162.9 106.6h.2v1.5l-.3-.1zM163.4 106.6h.2v1.5l-.3-.1zM162.1 102.1l1.5-.1 .1 .1v.3l-.1 .1h-1.4l-.1-.1zM162.1 102.7h1.5l.1 .1v.3l-.1 .1h-1.4l-.1-.1zM162.1 103.4l1.5-.1 .1 .1v.3l-.1 .1h-1.4l-.1-.1zM162.1 104h1.5l.1 .1v.3l-.1 .1h-1.4l-.1-.1z"/>
<path d="M163.9 106.6h.2v1.5l-.3-.1zM164.4 106.6h.2v1.5l-.3-.1zM164.9 106.6h.2v1.5l-.3-.1zM164.7 103.7l.6-.1 .2 .1 .1 .7-.1 .2h-.6h-.2zM164.7 101.9l.6-.1 .2 .1 .1 .8-.1 .1-.6 .1-.2-.1zM165.4 106.6h.2v1.5l-.3-.1zM165.9 106.6h.2v1.5l-.3-.1zM166.4 106.6h.2v1.5l-.3-.1zM166.9 106.6h.2v1.5l-.3-.1zM165.8 119.8l.7-.7h.8a.65 .65 0 0 0 .7 .7l-1.2 .1-.9 .8-.1 1.8zM168.3 104.2l.2-.1 1 .1 .1 .2v.8l-.2 .1-1.1-.1-.1-.2zM168.3 106.2h.2h1l.1 .2v.8l-.2 .1h-1.1l-.1-.2z"/>
<path d="M168.2 119.6h1.4v.2l-1.4 .1zM168.2 119.1h1.4v.2l-1.4 .1zM168.2 118.6h1.4v.2l-1.4 .1zM168.2 118.1h1.4v.2l-1.4 .1zM168.2 117.6h1.4v.2l-1.4 .1zM168.2 117.1h1.4v.2l-1.4 .1zM168.2 116.6h1.4v.2l-1.4 .1zM168.2 116.1h1.4v.2l-1.4 .1zM168.2 115.6h1.4v.2l-1.4 .1zM168.2 115.1h1.4v.2l-1.4 .1zM168.2 114.6h1.4v.2l-1.4 .1zM168.2 114.1h1.4v.2l-1.4 .1z"/>
<path d="M168.2 113.6h1.4v.2l-1.4 .1zM168.2 113.1h1.4v.2l-1.4 .1zM168.2 112.6h1.4v.2l-1.4 .1zM168.2 112.1h1.4v.2l-1.4 .1zM168.2 111.6h1.4v.2l-1.4 .1zM168.2 111.1h1.4v.2l-1.4 .1zM168.2 110.6h1.4v.2l-1.4 .1zM168.2 110.1h1.4v.2l-1.4 .1zM168.2 109.6h1.4v.2l-1.4 .1zM168.2 109.1h1.4v.2l-1.4 .1zM168.7 119.7l1.1-.1 .2-.2-.1-.9 .7 .1v3l-.6 .6-.1-2.2-.3-.2zM168.7 114.7h1.9v1.1l-.6 .1v-.8l-.2-.3z"/>
<path d="M172.6 109.9h.8l.1 .3h.4v-.5h.4v.5h.5v-.4l-.1-.1h-1.1l-.2 .2h-.8l.7-.7 .4 .4 1-.1a.29 .29 0 0 1 .3-.2 .29 .29 0 0 1 .3 .2l.1 .1-.3 .3-.1 .7 .1 .3 .3 .2-.5 .4-.3-.4h-.8a.56 .56 0 0 0-.5 .5v.6l-.2 .2v-.7l-.4-.3h-.6v-.6h1.3l.1 .2h.4v-.5h.4v.5h.4l.1-.1v-.3l-1.3-.1-.1 .3h-1.3v-.5zM172.3 101.2h2v2.4h-2zM173.7 113h.9l.1 .2-.1 .6-.2 .1-.7-.1-.1-.2zM173.7 111.5h.9l.1 .1-.1 .7-.2 .1-.7-.1-.1-.2zM173.7 110l.9-.1 .1 .2-.1 .6-.2 .1h-.7l-.1-.2zM173.7 106.9h.9l.1 .2-.1 .6-.2 .1-.7-.1-.1-.2zM173.7 108.4h.9l.1 .2-.1 .6-.2 .1h-.7l-.1-.2zM173.7 105.4h.9l.1 .1-.1 .7-.2 .1-.7-.1-.1-.2zM175.4 113h.9l.1 .2v.6l-.2 .1-.8-.1v-.2zM175.4 111.5h.9l.1 .1v.7l-.2 .1-.8-.1v-.2zM175.4 110l.9-.1 .1 .2v.6l-.2 .1h-.8v-.2zM175.4 106.9h.9l.1 .2v.6l-.2 .1-.8-.1v-.2z"/>
<path d="M175.4 108.4h.9l.1 .2v.6l-.2 .1h-.8v-.2zM175.4 105.4h.9l.1 .1v.7l-.2 .1-.8-.1v-.2zM176.3 101.2h2v2.4h-2zM178 109.7h.8v.2l-.8 .1zM178 109.2h.8v.2l-.8 .1zM178 108.7h.8v.2l-.8 .1zM178 108.2h.8v.2l-.8 .1zM178 107.7h.8v.2l-.8 .1zM178 107.2h.8v.2l-.8 .1zM178.4 114.5l.7-.1 .1 .1 .1 .7-.1 .2h-.6h-.2zM178.4 112.7l.7-.1 .1 .1 .1 .8-.1 .1-.6 .1-.2-.1zM179 110.1l.2 .1v.7h-.2z"/>
<path d="M179 106.2l.2 .1v.8l-.2-.1zM179.5 110.1l.2 .1v.7h-.2zM179.5 106.2l.2 .1v.8l-.2-.1zM180 110.1l.2 .1v.7h-.2zM180 106.2l.2 .1v.8l-.2-.1zM180.5 110.1l.2 .1v.7h-.2zM180.5 106.2l.2 .1v.8l-.2-.1zM180.1 102.5h.6h.2v.8v.1l-.7 .1-.2-.1zM180.1 100.8l.6-.1 .2 .1v.7v.2l-.7 .1-.2-.1zM181 110.1l.2 .1v.7h-.2zM181 106.2l.2 .1v.8l-.2-.1zM179.1 107.4l.2-.1 2.3 .1v.1v2.3l-.2 .1-2.3-.1-.1-.2z"/>
<path d="M181.5 110.1l.2 .1v.7h-.2zM181.5 106.2l.2 .1v.8l-.2-.1zM181.9 107.2h.7l.1 .2-.8 .1zM181.9 107.7h.7l.1 .2-.8 .1zM181.9 108.2h.7l.1 .2-.8 .1zM181.9 108.7h.7l.1 .2-.8 .1zM181.9 109.2h.7l.1 .2-.8 .1zM181.9 109.7h.7l.1 .2-.8 .1zM182.2 114.5l.7-.1 .1 .1 .1 .7-.1 .2h-.6h-.2zM182.2 112.7l.7-.1 .1 .1 .1 .8-.1 .1-.6 .1-.2-.1zM182.6 102.5h.6h.2l.1 .8-.1 .1-.6 .1-.2-.1zM182.6 100.8l.6-.1 .2 .1 .1 .7-.1 .2-.6 .1-.2-.1z"/>
<path d="M184 114.5l.6-.1 .2 .1 .1 .7-.1 .2h-.6h-.2zM184 112.7l.6-.1 .2 .1 .1 .8-.1 .1-.6 .1-.2-.1zM187.7 112.6h2v.6h-2zM187.7 103.7h2v.6h-2zM187.7 105h2v.6h-2zM187.7 106.2h2v.7h-2zM187.7 107.5h2v.6h-2zM187.7 108.8h2v.6h-2zM187.7 110h2v.7h-2zM187.7 111.3h2v.6h-2zM196.6 112.6h2v.6h-2zM196.6 111.3h2v.6h-2z"/>
<path d="M196.6 110h2v.7h-2zM196.6 108.7h2v.7h-2zM196.6 107.5h2v.6h-2zM196.6 106.2h2v.6h-2zM196.6 104.9h2v.7h-2zM196.6 103.7h2v.6h-2zM201.6 109.4h1.4v.6h-1.4zM201.6 110.7h1.4v.6h-1.4zM201.6 112h1.4v.6h-1.4zM201.6 113.2h1.4v.6h-1.4zM201.6 103.1h1.4v.6h-1.4zM201.6 104.3h1.4v.6h-1.4z"/>
<path d="M201.6 105.6h1.4v.6h-1.4zM201.6 106.9h1.4v.6h-1.4zM188.4 118.4l.1-.1h13.9l.1 .1v13.8l.2 .2h4l.1 .1v6.8l-.1 .1h-8.2l-.1-.1v-3.1h6.2a.81 .81 0 0 0 .8 0l-.4-.4-.4 .4h-6.2v-1.2h5.3l.1 .4 .4-.5h1.6l.4 .5a.81 .81 0 0 0 0-.9l-.4 .4h-1.6l-.4-.4-.1 .5h-5.3v-1.3h6.2l.4 .4 .4-.4a.81 .81 0 0 0-.8 0h-6.2v-1.8l-.1-.1h-9.8l-.1-.1v-1.2h7.7a.73 .73 0 0 0 .8 0l-.4-.4-.4 .4h-7.7v-1.2h6.8l.1 .4 .4-.4h1.6l.4 .4a.73 .73 0 0 0 0-.8l-.4 .4h-1.6l-.4-.4-.1 .4h-6.8v-1.2h7.7l.4 .4 .4-.4a.73 .73 0 0 0-.8 0h-7.7zM204.1 118.8h2v3.5h-2zM206.9 109.4h1.4v.6h-1.4zM206.9 110.7h1.4v.6h-1.4zM206.9 112h1.4v.6h-1.4zM206.9 113.2h1.4v.6h-1.4zM206.9 103.1h1.4v.6h-1.4zM206.9 104.3h1.4v.6h-1.4zM206.9 105.6h1.4v.6h-1.4zM206.9 106.9h1.4v.6h-1.4z"/>
<path d="M203.1 118.4l.1-.1h4.5l.1 .1v4.2l-.1 .1h-4.5l-.1-.1v-.3h.8l.2 .2 .4-.1v-1.3h1.2v1.3h.5l.1-.1v-1.2h-2.3l-.1 1.2h-.8v-3.5h.8l.1 1.1h.5v-1.3h1.2v1.3h.6v-1.1l-.2-.2h-2l-.2 .2h-.8zM208.7 118.8h2v3.5h-2zM213.9 119.7h.9l.1 .2v.6l-.2 .1h-.7l-.1-.2zM215.7 119.7h.9l.1 .2-.1 .6-.2 .1h-.7l-.1-.2zM195.1 100.6l.1-.1h21.6l.1 .1v2.1l.1 .2h12.2l.1 .1v7.2l-.1 .1h-2.2l-.1-.1v-4.8l-.2-.2h-12.4l-.1-.1v-.4h4.7l.2 .2 .4 .1 .3-.1 .2-.2h4a.78 .78 0 0 0 1.1 0l-.6-.6-.5 .6h-4l-.5-.6-.6 .6h-4.7v-.6h4.3l.1 .3 .2 .2 .6-.5h.1l.6 .5 .2-.2 .1-.3h3.2l.1 .3 .2 .2 .6-.5h.1l.6 .5 .3-.4-.1-.5-.2-.2-.6 .6h-.1l-.6-.6-.2 .2-.1 .4h-3.2l-.1-.4-.2-.2-.6 .6h-.1l-.6-.6-.2 .2-.1 .4h-4.3v-.7h4.7l.6 .6 .5-.6h4l.5 .6 .6-.6-.2-.2-.4-.1-.3 .1-.2 .2h-4a.78 .78 0 0 0-1.1 0h-4.7v-1.1l-.2-.1h-17.4l-.2 .1v1.1l-.1 .3v.7l.1 .3a.59 .59 0 0 0-.5 .6 .59 .59 0 0 0 .5 .5l-.1 .3v.8l.3 .3h-.2l-.1 .3v.7l.3 .2-.2 .1-.1 .2v.7l.3 .3-.3 .2v.8l.1 .4a.58 .58 0 0 0-.5 .5 .58 .58 0 0 0 .5 .6l-.1 .3v.7l.1 .3v1.1l.2 .1h16.6l.2-.1v-.4h5.1l.1 .4 .2 .2 .6-.6h.1l.6 .6 .2-.2 .1-.4h3.2l.1 .4 .2 .2 .6-.6h.1l.6 .6 .3-.4-.1-.6-.2-.2-.6 .6h-.1l-.6-.6-.2 .3-.1 .3h-3.2l-.1-.4-.2-.2-.6 .6h-.1l-.6-.6-.2 .3-.1 .3h-5.1v-.7h5.5l.6 .6 .5-.6h4l.5 .6 .6-.6-.2-.2h-.4l-.3 .1-.2 .1h-4a.78 .78 0 0 0-1.1 0h-5.5v-.3l.1-.1h13.2l.2-.2v-2.1l.1-.1h2.2l.1 .1v4.5l-.1 .1h-12.5l-.2 .2v1h-.1h-21.2h-.1v-1.7h23.8l.2 .2 .4 .1 .3-.1 .2-.2h4a.78 .78 0 0 0 1.1 0l-.6-.6-.5 .6h-4l-.5-.6-.6 .6h-23.8zM220.3 118.3h3.4a1.33 1.33 0 0 0 .5 2.3 1.33 1.33 0 0 0-1 1.2 1.33 1.33 0 0 0 1 1.3 1.33 1.33 0 0 0-.7 2.1 1.33 1.33 0 0 0 2.1 0 1.33 1.33 0 0 0-.7-2.1 1.33 1.33 0 0 0 1-1.3 1.33 1.33 0 0 0-1-1.2 1.33 1.33 0 0 0 .5-2.3h3.8l.1 .1v12.3h-.1h-10.5l-.1-.4 .9 .1 .2-.1h4.6l.3 .1 .2-.1-.3-.2-.2 .2h-4.6l-.2-.2-.3 .2h-.6v-.6l.2-.2h1.3l.2 .2 .1-.2h3.2l.1 .2 .2-.2h1.3l.2 .2 .1-.3-.1-.2-.2 .3h-1.3l-.2-.3-.1 .3h-3.2l-.1-.3-.2 .3h-1.3l-.2-.2v-.7h.6l.3 .2 .2-.2h4.6l.2 .2 .3-.2-.3-.1-.2 .1h-4.6l-.3-.1-.8 .1v-.8l.9 .1 .2-.1h4.6l.3 .1 .2-.1-.3-.3-.2 .3h-4.6l-.2-.3-.3 .3h-.6v-.7l.2-.2h1.3l.2 .3 .1-.2h3.2l.1 .2 .2-.3h1.3l.2 .3 .1-.3-.1-.2-.2 .2h-1.3l-.2-.2-.1 .3h-3.2l-.1-.3-.2 .2h-1.3l-.2-.2v-.6h.6l.3 .2 .2-.2h4.6l.2 .2 .3-.2-.3-.1-.2 .1h-4.6l-.3-.1-.8 .1v-.7a1.33 1.33 0 0 0 2-.4 1.33 1.33 0 0 0-.8-1.9 1.33 1.33 0 0 0 1-1.3 1.33 1.33 0 0 0-1-1.2 1.33 1.33 0 0 0 .5-2.3zM74 139.5h.7v2h-.7zM74 136.1h.7v2h-.7zM74 133.7h.9l.1 .2-.1 .6-.2 .1-.7-.1-.1-.2zM75 139.5h.6v2h-.6zM75 136.1h.6v2h-.6zM75.9 139.5h.7v2h-.7z"/>
<path d="M75.9 136.1h.7v2h-.7zM75.7 133.7h.9l.1 .2v.6l-.2 .1-.8-.1v-.2zM78.3 136.1h1.4v3.6h-1.4zM77.4 126.2h1.1v4.6h-1.1zM70.5 125.5l.1-.1h9.5l.1 .1v6.4h-4.6a.82 .82 0 0 0-.6 .7v.8l-1-.1-.3 .2a.6 .6 0 0 0-.6 .7 .6 .6 0 0 0 .7 .5l-.1 3.4 .1 .2 .2 .1h.7l.4-.2v-2.2l-.2-.1 .1-1.1a.83 .83 0 0 0 .5 1v2.9l.5 .5h-2l-.3 .3 .1 3.3-.2 .4v.5l.1 .4 .2 .1v1l-.3 .4v.6a.56 .56 0 0 0 .5 .5h.7l.4-.3h.3l.1 .2h.3l.1-.5h.4v.5h.4l.1-.2h.8l.2 .2h.5l.1-.9h.3l.1 .9h.5l.1-.2v-.7h-1.7l-.1 .7h-.8v-.3h-1.4v.3h-.3v-1h.3v.3h.5v-.4h.4v.4h.5v-.3l-.2-.1h-1l-.2 .1h-.3l-.2-.2v-.5h2.7l.1 .6h.7v-.8h.3v.8h.7l.1-.6-.2-.2h-1.5l-.2 .2h-2.7v-.5l.3-.3v-.6l-.1-.3-.3-.2v-.5a.56 .56 0 0 0 .8 0v.5l-.3 .4v.7a.7 .7 0 0 0 .7 .4h1.7a.83 .83 0 0 0 .6-.9 .83 .83 0 0 0-.8-.7h-.8l.1-2 .3 .1h2.6v6.8h-9.2l-.1-.1v-16.7h6.7l.2 .1 .1-1.9h1v1.9h.1l.1-.1v-1.8l-1.5 .1v1.7h-6.7v-4.6h6.7l.1 1.7h.2v-1.9h1v1.9l.2-.1v-1.6l-.2-.2h-1.1l-.2 .2h-6.7zM76.2 135.9l6.2-.1 .1 .1v4.1l-.1 .1h-5.2v-.4h.9l.1 .2h.2v-1.4h1.2v1.4h.2l.1-.2v-1.2h-1.7l-.1 1.2h-.9l-.1-.9-.1-.2h-.8l-.1-.1 .1-.8h.3l.1 .6 .2-.2-.1-.4h-.5v-1.7h.3v.5h.3v-.4h1.3l.1 1.2h.2v-1.3h1.2v1.3h.2l.1-1.2-.2-.2h-1.4l-.2 .2h-1.3l-.1-.2-.5 .1zM82.5 126.2h1.1v4.6h-1.1zM81 133.4h3.6v1.4h-3.6zM85.9 136.1h1.4v3.6h-1.4zM75.1 114.6h10.8v9.4h-10.8zM80.8 125.5l.1-.1h9.4l.1 .1v6.3l-.1 .1h-9.4l-.1-.1v-1h1.5l.1 .1h.2v-1.9h.9v1.9h.2l.1-1.8-1.4-.1-.1 1.8h-1.5v-4.6h1.5l.1 1.7h.2v-1.9h.9v1.9l.3-.1v-1.6l-.2-.2h-1.1l-.2 .2h-1.5zM83.1 135.9l.1-.1h7.1l.1 .1v4.1l-.1 .1h-7.1l-.1-.4h2.6l.1 .2h.2v-1.4h1.2v1.4h.2l.1-.2v-1.2h-1.7l-.1 1.2h-2.6v-3.6h2.6l.1 1.2h.2v-1.3h1.2v1.3h.2l.1-1.2-.2-.2h-1.4l-.2 .2h-2.6z"/>
<path d="M75.7 132.5h14.6l.1 .1v2.5l-.1 .1h-14.6l-.1-.4h5.2l.2 .2h1.2v-.3h1.2v.3h1.2l.2-.2-.1-.1h-3.8l-.1 .1h-5.2l.1-.3h.9l.1 .3 .2-.2-1.2-.1v-1h.9v.2l.3-.1-.2-.2-1 .1-.1-.1h5.2l.1 .1h1.3v-.2h1.2v.2h1.4v-.2l-.2-.1h-3.6l-.2 .2h-5.2v-.8zM94.7 136.1h1.4v3.6h-1.4zM97.4 133.4h3.6v1.4h-3.6zM97.9 126.2h1.1v4.6h-1.1zM91 125.5l.1-.1h9.5v.1v6.3v.1h-9.5l-.1-.1v-1h6.7l.2 .1v-1.9h1v1.9h.1l.2-.1v-1.7h-1.5v1.7h-6.7v-4.6h6.7v1.7h.2v-1.9h1v1.9l.3-.1v-1.6l-.2-.2h-1.2l-.1 .2h-6.7zM97.1 132.5h4.2l.1 .1v4.9l-.1 .1h-4.2l-.1-.1v-2.7h.2l.2 .2h1.2v-.3h1.2v.3h1.2l.2-.2-.1-.1h-3.9v.1h-.2v-1.4h.2v.1h1.4v-.2h1.2v.2h1.4l-.1-.2-.1-.1h-3.6l-.2 .2h-.2v-.8zM97.1 138.2h4.2l.1 .1v5.1h-.9l-.3 .3h-3.1l-.1-.1v-1.2h.2l.2 .2h1.2v-.3h1.2v.3h1.2l.2-.2-.1-.1h-3.9v.1h-.2v-1.4h.2v.1h1.4v-.2h1.2v.2h1.4l-.1-.2-.1-.1h-3.6l-.2 .2h-.2v-2.7zM102.3 136.1h1.4v3.6h-1.4zM103 126.2h1.1v4.6h-1.1zM95.6 114.6h10.8v9.4h-10.8zM105.5 138.3h.2h1.4l.1 .2-.1 1.1-.2 .1-1.4-.1-.1-.2zM105.5 133.2h.2h1.4l.1 .2-.1 1.1-.2 .1-1.4-.1-.1-.1z"/>
<path d="M105.5 136.2h.2h1.4l.1 .2-.1 1.1-.2 .1-1.4-.1-.1-.2zM102.1 135.7h6.2l.1 .1v4.2l-.1 .1h-6.2l-.1-.4 .2 .2h.6v-1.8h.4v1.8h.6l.1-.2h1.3l.2 .2h.7v-.7h.4v.7h.7l.2-.2-.1-.5h-2l-.1 .5h-1.3v-1.4h1.3l.1 .5h.8v-.7h.4v.7l.9-.1v-.5l-.2-.1h-1.8l-.2 .2h-1.3l-.1-.2h-1.7l-.1 1.6v-3.6l.1 1.6h.7v-1.7h.4v1.7h.6l.1-.1h1.3l.2 .2h.7v-.7h.4v.7h.7l.2-.2-.1-.5h-2l-.1 .5h-1.3v-1.4h1.3l.1 .5h.8v-.7h.4v.7h.8l.1-.5-.2-.2h-1.8l-.2 .2h-1.3l-.2-.3h-1.4l-.3 .2zM101.3 125.5l.1-.1h9.3l.1 .1v6.3l-.1 .1h-9.3l-.1-.1v-1h1.5v.1h.2v-1.9h1v1.9h.2v-1.8l-1.4-.1v1.8h-1.5v-4.6h1.5v1.7h.2v-1.9h1v1.9l.2-.1v-1.6l-.1-.2h-1.2l-.1 .2h-1.5zM113.7 138.2l.1-.1 1.1 .1 .1 .1-.1 .9h-.1h-1.1l-.1-.2zM113.7 131.3l.1-.1 1.1 .1 .1 .2-.1 .8-.1 .1-1.1-.1-.1-.2zM113.7 133.4l.1-.1h1.1l.1 .2-.1 .8-.1 .1h-1.1l-.1-.2zM114.2 135.3l.8-.1 .2 .1v1v.2l-.9 .1-.1-.1-.1-1.1zM111.5 132.9h3.9l.1 .1v3.7l-.1 .1h-3.9l-.1-.2h2.5l.1 .2h.4l.1-.7h.4v.7h.4l.1-.2v-.5h-1.4l-.1 .5h-2.5v-1.4h2.5l.1 .5h.5v-.7h.4v.7l.5-.1v-.5l-.1-.1h-1.2l-.2 .2h-2.5v-.8h2l.2 .2h.5v-.5h.4v.5h.5l.2-.2-.1-.3h-1.6l-.1 .3h-2v-1.1h2l.1 .4h.6v-.6h.4v.6l.7-.1v-.4l-.2-.1h-1.4l-.2 .2h-2zM111.5 139.8h3.9h.1v3.9l-.1 .1h-3.9l-.1-.1v-.3h2.5l.1 .2h.4l.1-.7h.4v.7h.4l.1-.2v-.5h-1.4l-.1 .5h-2.5v-1.4h2.5l.1 .6h.5v-.7h.4v.7l.5-.1v-.5l-.1-.1h-1.2l-.2 .1h-2.5v-.7h2l.2 .2h.5v-.6h.4v.6h.5l.2-.2-.1-.4h-1.6l-.1 .4h-2v-1.2h2l.1 .4h.6v-.5h.4v.5h.7v-.4l-.2-.1h-1.4l-.2 .1h-2zM114.7 125.3l.7-.1 .5-.4 .1 .1-.4 .5-.1 .7-1.1 .3zM116.2 135.3l.8-.1 .2 .1 .1 1-.1 .2-.8 .1-.2-.1-.1-1.1zM116.6 138.2l.2-.1 1 .1 .1 .1v.9h-.2h-1.1l-.1-.2z"/>
<path d="M116.6 131.3l.2-.1 1 .1 .1 .2v.8l-.2 .1-1.1-.1-.1-.2zM116.6 133.4l.2-.1h1l.1 .2v.8l-.2 .1h-1.1l-.1-.2zM116.8 126.1l1-.6 .5 .4 .4 .2v.1l-.4 .1-.5 .4zM116.4 127.8h1.7v1.7h-1.7zM119.4 139.6h.5v1.5h-.5zM119.4 133.7h.5v1.5h-.5zM120.1 139.6h.4v1.5h-.4zM120.1 133.7h.4v1.5h-.4zM119.3 131.7h.9l.1 .1-.1 .7h-.1h-.8l-.1-.2zM120.5 135.9h4.2v3h-4.2zM120.7 139.6h.5v1.5h-.5zM120.7 133.7h.5v1.5h-.5z"/>
<path d="M121.4 139.6h.4v1.5h-.4zM121.4 133.7h.4v1.5h-.4zM118.5 133.3h3.1l.1 .1v2.1l-.1 .1h-.9l.1-.3v-.7h.3v.7h.3v-.7h-.7l.1-1h.3v.7h.3v-.8l-1.6 .1v1.7l.2 .4v3.2l-.5 .1-.2 .3-.1 .3v1.6l.2 .1h.4v.4l-.4 .4-.3 .6v.6l.2 .3v.2h-3.3l-.1-.4 .2 .2h.4v-.7h.4l.1 .7 .5-.1v-.5l-1.5-.1-.1 .5v-1.4l.1 .6h.5v-.7h.4v.7h.5l.1-.6-.2-.1h-1.2l-.2 .1v-.7h.4l.2 .2h.5v-.6h.4l.1 .6h.5l.1-.2v-.4h-1.7l-.1 .4h-.4v-1.2h.4l.1 .4h.6v-.5h.4v.5h.7v-.4l-.2-.1h-1.4l-.2 .1h-.4v-.3h.1h2.2l.2-.2v-4.4h.8l.1 .1h.2v-.7l-.3 .1v.5h-.8v-1.5h.8v.5l.3 .1v-.7h-.2l-.1 .1h-.8v-.3zM121.1 131.7h.9l.1 .1-.1 .7h-.2h-.7l-.1-.2zM120.6 120.1h1.4v.2l-1.4 .1zM120.6 120.6h1.4v.2l-1.4 .1zM120.6 121.1h1.4v.2l-1.4 .1zM120.6 121.6h1.4v.2l-1.4 .1zM120.6 122.1h1.4v.2l-1.4 .1zM120.6 122.6h1.4v.2l-1.4 .1zM120.6 123.1h1.4v.2l-1.4 .1zM120.6 123.6h1.4v.2l-1.4 .1z"/>
<path d="M120.6 124.1h1.4v.2l-1.4 .1zM120.6 124.6h1.4v.2l-1.4 .1zM120.6 125.1h1.4v.2l-1.4 .1zM120.6 125.6h1.4v.2l-1.4 .1zM120.6 126.1h1.4v.2l-1.4 .1zM120.6 126.6h1.4v.2l-1.4 .1zM122 139.6h.5v1.5h-.5zM122 133.7h.5v1.5h-.5zM122.7 139.6h.4v1.5h-.4zM122.7 133.7h.4v1.5h-.4zM123.1 127.9l.3 .1-.1 1.4-.2-.1zM123.3 139.6h.5v1.5h-.5z"/>
<path d="M123.3 133.7h.5v1.5h-.5zM123.6 127.9l.3 .1-.1 1.4-.2-.1zM123.1 131.7h.9l.1 .1v.7h-.2h-.8v-.2zM124 139.6h.4v1.5h-.4zM124 133.7h.4v1.5h-.4zM124.1 127.9l.3 .1-.1 1.4-.2-.1zM124.6 139.6h.5v1.5h-.5zM124.6 133.7h.5v1.5h-.5zM124.6 127.9l.3 .1-.1 1.4-.2-.1zM125.3 139.6h.4v1.5h-.4zM125.3 133.7h.4v1.5h-.4zM125.1 127.9l.3 .1-.1 1.4-.2-.1z"/>
<path d="M124.9 131.7h.9l.1 .1-.1 .7h-.2h-.7l-.1-.2zM125.6 127.9l.3 .1-.1 1.4-.2-.1zM126.1 127.9l.3 .1-.1 1.4-.2-.1zM116 130.1h10.5l.1 .1v4.5l-.1 .1h-.6l-.1-1.2-.6-.1v-.1l.8-.9v-.8l-.3-.3h-.7a.43 .43 0 0 0-.4 .4v.6l.2 .3-.3 .3-.1 .5-.1 .1v1.1l-1-.1 .1-1h.3v.7h.3v-.7h-.6l-.1-.5-.2-.2h-4.9l-.2 .2h-.5l-.1 1.5h.6v2.5v.1h-2l-.1-.1v-.5l.2 .2h.4v-.7h.4l.1 .7 .5-.1v-.6h-1.5l-.1 .5v-1.4l.1 .5h.5v-.7h.4v.7h.5l.1-.5-.2-.2h-1.2l-.2 .2v-.8h.4l.2 .2h.5v-.5h-.6l-.1 .3h-.4v-1.1h.4l.1 .4h.6v-.6h-.5l-.2 .2h-.4v-1.8h.4v.7l.2 .3 1.2 .1a.44 .44 0 0 0 .4-.4l.4 .2 .6 .1 .1 .2h.3h.7l.6-.5v.4l.2 .1h.3v-.4h.4l.1 .4h.3l.1-.2h.7l.1 .2h.3l.1-.4h.4v.4h.3l.2-.1v-.3h-1.4v.2h-.7v-.2h-.9v-.8h.4v.4h.5v-.3h.7v.3h.5v-.4h.4v.4h.5v-.3l-.2-.2h-1.1l-.1 .2h-.7l-.1-.2h-1.1l-.2 .1v.4l-.1-.2-.6-.3h-.7l-.3 .3h-.3l-.3-.2-.4-.1-.3-.3-1-.1a.44 .44 0 0 0-.5 .5h-.4v-1.3zM126.6 127.9l.3 .1-.1 1.4-.2-.1zM127.1 127.9l.3 .1-.1 1.4-.2-.1zM127.7 137.3h2.2v1.2h-2.2zM127.7 132.8h2.2v1.2h-2.2zM127.6 127.9l.3 .1-.1 1.4-.2-.1zM128.1 127.9l.3 .1-.1 1.4-.2-.1zM128.6 127.9l.3 .1-.1 1.4-.2-.1zM129.1 127.9l.3 .1-.1 1.4-.2-.1z"/>
<path d="M129.6 127.9l.3 .1-.1 1.4-.2-.1zM120.8 140.1h.9v1l.1 .2 .2 .1 1.3-.1 .1-.2v-.6h.3v.7l.3 .1v-.8h-.6v-.4h.9v1a.57 .57 0 0 0 .6 .7 .57 .57 0 0 0 .5-.8v-.5h.2l.1 .8 5-.1 .4 .4 .3-.4-.3-.1-.4 .1h-4.9l.1-.6-.5-.1v-.4h.5l-.1-.6h1.4l.2-.1v-.9l.2 .2h.9l.1-.6h.4v.6l1-.1v-.5h-2.5v.4h-.1v-1.2h.1v.4h1.1v-.5h.4v.5h1l.1-.4-.2-.2h-2.2l-.3 .2v-1.4l.1-.1h2.6l.1 .1v3.4l.2 .2h1.9l.1 .1v4l-.1 .1h-8.1l.2-.2h.2l.2 .2h.3v-.5h.4l.1 .5 .4-.1v-.4h-1.3l-.1 .3h-.2v-1h.2l.1 .3h.4v-.4h.4v.4h.5v-.3h4.7l.4 .1 .3-.1-.3-.4-.4 .4h-4.7l-.1-.2h-1.1l-.2 .2h-.2l-.2-.2-.2-.4h6.3l.1 .3 .4-.3h.5l.4 .3 .2-.4-.2-.3-.4 .4h-.5l-.4-.4-.1 .4h-6.3a.58 .58 0 0 0-.7-.2 .58 .58 0 0 0-.3 .6l-.3 .5 .1 .5 .2 .4h-2.3l-.1-.2h.2l.2 .2h.3v-.5h.4l.1 .5 .3-.1 .1-.1v-.3h-1.3l-.1 .3h-.2v-1h.2l.1 .3h.4v-.4h.4v.4h.5v-.4l-.1-.1h-1.1l-.2 .2h-.2v-.2l.2-.3v-1.5h.3v.7h.3v-.7h-.6zM130.1 127.9l.3 .1-.1 1.4-.2-.1zM130.6 127.9l.3 .1-.1 1.4-.2-.1zM130.2 130h.9l.1 .2v.6l-.2 .1-.7-.1-.1-.1zM131.1 127.9l.3 .1-.1 1.4-.2-.1zM131.6 127.9l.3 .1-.1 1.4-.2-.1zM131.9 132.7h6.4v5.8h-6.4zM132.1 127.9l.3 .1-.1 1.4-.2-.1zM132 130h.9l.1 .2-.1 .6-.2 .1-.7-.1-.1-.1zM132.6 127.9l.3 .1-.1 1.4-.2-.1zM133.1 127.9l.3 .1-.1 1.4-.2-.1z"/>
<path d="M133.6 127.9l.3 .1-.1 1.4-.2-.1zM134.1 127.9l.3 .1-.1 1.4-.2-.1zM134.6 127.9l.3 .1-.1 1.4-.2-.1zM135.1 127.9l.3 .1-.1 1.4-.2-.1zM135.6 127.9l.3 .1-.1 1.4-.2-.1zM136.1 127.9l.3 .1-.1 1.4-.2-.1zM136.6 127.9l.3 .1-.1 1.4-.2-.1zM137.1 127.9l.3 .1-.1 1.4-.2-.1zM137.6 127.9l.3 .1-.1 1.4-.2-.1zM138.1 127.9l.3 .1-.1 1.4-.2-.1zM138.6 127.9l.3 .1-.1 1.4-.2-.1zM139.1 127.9l.3 .1-.1 1.4-.2-.1z"/>
<path d="M139.6 127.9l.3 .1-.1 1.4-.2-.1zM140.1 127.9l.3 .1-.1 1.4-.2-.1zM130.7 132.1h9.6l.1 .1v6.8l-.1 .1h-9.6l-.1-.1v-.5h1.1l.2 .2h1.9l.1-1.9h2.4v1.9h2l.2-.2-.1-1.7h-6.7v1.7h-1.1v-5.8h1.1v1.7h2.2v-1.8h2.4v1.8h2.2v-1.7l-.2-.2h-6.4l-.2 .2h-1.1v-.5zM140.6 127.9l.3 .1-.1 1.4-.2-.1zM141.4 136.8h1v1h-1zM141.7 130.8h.7l.1 .1 .1 .7-.1 .2h-.6l-.2-.1zM141.7 129.1l.7-.1 .1 .1 .1 .7-.1 .2-.6 .1-.2-.1zM141.9 126.6h1.4l.1 .2-1.5 .1zM141.9 126.1h1.4l.1 .2-1.5 .1zM141.9 125.6h1.4l.1 .2-1.5 .1zM141.9 125.1h1.4l.1 .2-1.5 .1zM141.9 124.6h1.4l.1 .2-1.5 .1z"/>
<path d="M141.9 124.1h1.4l.1 .2-1.5 .1zM141.9 123.6h1.4l.1 .2-1.5 .1zM141.9 123.1h1.4l.1 .2-1.5 .1zM141.9 122.6h1.4l.1 .2-1.5 .1zM141.9 122.1h1.4l.1 .2-1.5 .1zM141.9 121.6h1.4l.1 .2-1.5 .1zM141.9 121.1h1.4l.1 .2-1.5 .1zM141.9 120.6h1.4l.1 .2-1.5 .1zM141.9 120.1h1.4l.1 .2-1.5 .1zM144.2 130.8h.7l.2 .1v.7l-.1 .2h-.6l-.2-.1zM144.2 129.1l.7-.1 .2 .1v.7l-.1 .2-.6 .1-.2-.1zM134.9 139.5h10.2l.1 .1v4l-.1 .1h-10.2l-.1-.1v-.9h7.9l.1 .1h.6v-.9h.4l.1 .9h.5l.2-.1-.1-.8h-1.8v.8h-7.9v-.2h.6l.1 .1h.4l.1-.6h.3l.1 .6h.4l.1-.1v-.5h-1.5v.5h-.6v-1.2h.6v.4h.6v-.6h.3v.6h.6v-.4l-.2-.2h-1.2l-.1 .2h-.6v-.5h7.9v.7h.7v-.9h.4v.9h.8v-.8l-.2-.1h-1.6l-.1 .2h-7.9v-1.2z"/>
<path d="M146.9 130.8h.7l.1 .1 .1 .7-.1 .2h-.6l-.2-.1zM146.9 129.1l.7-.1 .1 .1 .1 .7-.1 .2-.6 .1-.2-.1zM146.9 120.1h1.4v.2l-1.4 .1zM146.9 120.6h1.4v.2l-1.4 .1zM146.9 121.1h1.4v.2l-1.4 .1zM146.9 121.6h1.4v.2l-1.4 .1zM146.9 122.1h1.4v.2l-1.4 .1zM146.9 122.6h1.4v.2l-1.4 .1zM146.9 123.1h1.4v.2l-1.4 .1zM146.9 123.6h1.4v.2l-1.4 .1zM146.9 124.1h1.4v.2l-1.4 .1zM146.9 124.6h1.4v.2l-1.4 .1z"/>
<path d="M146.9 125.1h1.4v.2l-1.4 .1zM146.9 125.6h1.4v.2l-1.4 .1zM146.9 126.1h1.4v.2l-1.4 .1zM146.9 126.6h1.4v.2l-1.4 .1zM149.4 127.9l.2 .1v1.4l-.3-.1zM149.6 137.3h2.2v1.2h-2.2zM149.6 132.8h2.2v1.2h-2.2zM149.9 127.9l.2 .1v1.4l-.3-.1zM150.4 127.9l.2 .1v1.4l-.3-.1zM148.6 123.1h4.1l-1.7 1.7h-2.4zM150.9 127.9l.2 .1v1.4l-.3-.1zM151.4 127.9l.2 .1v1.4l-.3-.1z"/>
<path d="M151.9 127.9l.2 .1v1.4l-.3-.1zM148.9 136.8h3.2l.1 .1v2.4l.2 .2h.7l.1 .1v4l-.1 .1h-4.2l-.1-.1v-1.1h3l.4 .1 .3-.1-.4-.4-.3 .4h-3v-.6h2.6l.1 .3 .4-.3h.5l.4 .3 .1-.4-.1-.3-.4 .4h-.5l-.4-.4-.1 .4h-2.6v-.7h3l.3 .4 .4-.4-.4-.1-.3 .1h-3v-2.7h.6l.2 .2h.9v-.6h.4l.1 .6h.9l.1-.2v-.4h-2.5l-.1 .4h-.6v-1.2h.6l.1 .4h1v-.5h.4v.5h1.1v-.4l-.1-.2h-2.3l-.2 .2h-.6v-.4zM152.4 127.9l.2 .1v1.4l-.3-.1zM152.9 127.9l.2 .1v1.4l-.3-.1zM153.4 127.9l.2 .1v1.4l-.3-.1zM153.8 132.7h6.4v5.8h-6.4zM153.9 127.9l.2 .1v1.4l-.3-.1zM154.4 127.9l.2 .1v1.4l-.3-.1zM154.9 127.9l.2 .1v1.4l-.3-.1zM149 144.1l4.3-.1 .3-.3v-1.2h.7l.4 .1 .4-.1-.4-.4-.4 .4h-.7v-.6h.3l.1 .3 .4-.3h.6l.3 .3 .2-.4-.2-.3-.3 .4h-.6l-.4-.4-.1 .4h-.3v-.7h.7l.4 .4 .4-.4-.4-.1-.4 .1h-.7v-1.7h1.9l.1 4.3 .4 .3h5.2l-.1 3.5h-12.1zM155.4 127.9l.2 .1v1.4l-.3-.1zM155.9 127.9l.2 .1v1.4l-.3-.1z"/>
<path d="M156.4 127.9l.2 .1v1.4l-.3-.1zM156.8 124.4v2l-.4 .4v-2zM156.9 127.9l.2 .1v1.4l-.3-.1zM157.4 127.9l.2 .1v1.4l-.3-.1zM157.9 127.9l.2 .1v1.4l-.3-.1zM158.4 127.9l.2 .1v1.4l-.3-.1zM158.9 127.9l.2 .1v1.4l-.3-.1zM159.4 127.9l.2 .1v1.4l-.3-.1zM159.9 127.9l.2 .1v1.4l-.3-.1zM160.1 121.3l.8 .8a.57 .57 0 0 0-.8 .5 .57 .57 0 0 0 .6 .6 .57 .57 0 0 0 .5-.7l.4 .4v4l-1 .1a.59 .59 0 0 0-.6 0 .59 .59 0 0 0-.3 .6h-1a.68 .68 0 0 0-.3-.6 .68 .68 0 0 0-.8 .1l-.5 .4-.1 .5 .1 1.5 .1 .1 .4 .2-.2 .1h-.9l-.3-.2h.5l.3-.3-.1-2 .6-.8v-2.2h2.6a.57 .57 0 0 0 .8 .6 .57 .57 0 0 0 .1-1 .57 .57 0 0 0-.9 .3v.1h-2.6v-.1l2-1.9a.62 .62 0 0 0 .5-1zM160.4 127.9l.2 .1v1.4l-.3-.1zM160.9 127.9l.2 .1v1.4l-.3-.1z"/>
<path d="M161.4 127.9l.2 .1v1.4l-.3-.1zM161.9 127.9l.2 .1v1.4l-.3-.1zM162.4 127.9l.2 .1v1.4l-.3-.1zM152.7 132.1h10.1l.1 .1v6.8l-.1 .1h-10.1l-.1-.1v-.5h1l.2 .2h2v-1.9h2.4l.1 1.9h1.9l.2-.2v-1.7h-6.7l-.1 1.7h-1v-5.8h1l.1 1.7h2.1v-1.8h2.4v1.8h2.2v-1.7l-.1-.2h-6.5l-.2 .2h-1v-.5zM162.9 127.9l.2 .1v1.4l-.3-.1zM163.4 127.9l.2 .1v1.4l-.3-.1zM163.9 127.9l.2 .1v1.4l-.3-.1zM164.4 127.9l.2 .1v1.4l-.3-.1zM164.6 133.6h1.7v1.7h-1.7zM164.9 127.9l.2 .1v1.4l-.3-.1zM165.4 127.9l.2 .1v1.4l-.3-.1zM156 139.5h9.7l.1 .1v4l-.1 .1h-9.7l-.1-.1v-.9h6.9l.1 .1h.6v-.9h.4v.9h.6l.1-.1v-.8h-1.8v.8h-6.9v-.2h.5l.2 .1h.4v-.6h.4l.1 .6h.4l.1-.1v-.5h-1.5l-.1 .5h-.5v-1.2h.5l.1 .4h.5v-.6h.4v.6h.6v-.4l-.2-.2h-1.2l-.2 .2h-.5v-.5h6.9v.7h.7v-.9h.4v.9h.7v-.8l-.1-.1h-1.6l-.1 .2h-6.9v-1.2z"/>
<path d="M165.9 127.9l.2 .1v1.4l-.3-.1zM166.4 127.9l.2 .1v1.4l-.3-.1zM166.9 127.9l.2 .1v1.4l-.3-.1zM168.2 126.6h1.4v.2l-1.4 .1zM168.2 126.1h1.4v.2l-1.4 .1zM168.2 125.6h1.4v.2l-1.4 .1zM168.2 125.1h1.4v.2l-1.4 .1zM168.2 124.6h1.4v.2l-1.4 .1zM168.2 124.1h1.4v.2l-1.4 .1zM168.2 123.6h1.4v.2l-1.4 .1zM168.2 123.1h1.4v.2l-1.4 .1zM168.2 122.6h1.4v.2l-1.4 .1z"/>
<path d="M168.2 122.1h1.4v.2l-1.4 .1zM168.2 121.6h1.4v.2l-1.4 .1zM168.2 121.1h1.4v.2l-1.4 .1zM168.2 120.6h1.4v.2l-1.4 .1zM168.2 120.1h1.4v.2l-1.4 .1zM188.5 132.4h9.2l.1 .1v7.3l.1 .2h8.8l.1 .1v7.4l-.1 .1h-18.2l-.1-.1v-1.3h16.2a.81 .81 0 0 0 .8 0l-.4-.4-.4 .4h-16.2v-1.2h15.3l.1 .4 .4-.5h1.6l.4 .5a.81 .81 0 0 0 0-.9l-.4 .4h-1.6l-.4-.4-.1 .5h-15.3v-1.3h16.2l.4 .4 .4-.4a.81 .81 0 0 0-.8 0h-16.2v-1.9h6.4a1.68 1.68 0 0 0 2.3 1.8 1.68 1.68 0 0 0 .5-2.8 1.68 1.68 0 0 0-2.7 .7l-.1 .3h-6.4v-6.3h7.7a.73 .73 0 0 0 .8 0l-.4-.3-.4 .3h-7.7v-1.1h6.8l.1 .3 .4-.3h1.6l.4 .3a.73 .73 0 0 0 0-.7l-.4 .4h-1.6l-.4-.4-.1 .4h-6.8v-1.2h7.7l.4 .4 .4-.4a.73 .73 0 0 0-.8 0h-7.7v-.7zM203.9 124.4h7v7h-7zM203.1 123.5l.1-.1h7.9l.2 .1 1.1 1.2v7.3l.2 .1h3.6v.3h1.7v-.3l.1 .1v5.1h-.1h-10.4v-.4h4.9l.1 .2h.5v-.5h.9l.1 .5h.4l.2-.2h1.2l.2 .2h.4l.1-.5h.9v.5h.5l.1-.2-.1-.3h-2l-.1 .3h-1.2l-.1-.3h-2l-.1 .3h-4.9v-.8h1.5a.96 .96 0 0 0 1.1 0l-.6-.5-.5 .5h-1.5v-1.3h.7v.5l.1 .2 .6-.6h1.2l.6 .6h1.7l.1 .2h.5v-.4h.9v.4h.6l.1-.2h1.2l.1 .2h.6v-.4h.9v.4h.6v-.3l-.2-.1h-1.8l-.2 .2h-1.2l-.2-.2h-1.8l-.2 .2h-1.7l.1-.2a1.04 1.04 0 0 0-.1-.9l-.6 .5h-1.2l-.6-.5-.1 .4h-.7v-1h1.5l.5 .5 .6-.5a.96 .96 0 0 0-1.1 0h-1.5v-.3h5.3l.2 .2h.2v-.2h.9v.2h.2l.1-.2h-6.9v-.1h8.7l.1 .2h.3v-.3h.9v.3h.2l.2-.1v-.2l-10.4 .1v-.8l5.7 .1v-.2h.9v.2h.3v-.1l-.1-.1-1.3-.1-.2 .2h-5.3v-.7l-.2-.1h-4.1l-.1-.4h.6l.2 .2h1v-1.2h5v1.2h1l.2-.1v-1.1h-7.4v1h-.6v-7h.6v1h1.2v-1.1h5v1.1h1.1l.1-1-.2-.2h-7l-.2 .2h-.6zM213.1 123.8h1.6v.7h-1.6zM213.1 122.9h1.6v.6h-1.6zM213.1 121.9h1.6v.7h-1.6zM213.2 125.8l.7-.1 .1 .1 .1 .7-.1 .2-.6 .1-.2-.1z"/>
<path d="M213.2 127.5h.7l.1 .1 .1 .7-.1 .2h-.6l-.2-.1zM212.7 138.5l.2-.1 1.4 .1 .1 .2-.1 1.1-.2 .1-1.4-.1-.1-.2zM212.7 135.5h.2h1.4l.1 .2-.1 1.1-.2 .1-1.4-.1-.1-.2zM213 129.3h1.2v.9h-1.2zM213 132.6h1.2v.9h-1.2zM215.8 122.9h1.6v.6h-1.6zM215.8 121.9h1.6v.7h-1.6zM215.8 123.8h1.6v.7h-1.6zM216.6 127.5h.7l.2 .1v.7l-.1 .2h-.6l-.2-.1zM216.6 125.8l.7-.1 .2 .1v.7l-.1 .2-.6 .1-.2-.1zM216.4 130.3l.2-.1 1.1 .1v.2v.8l-.2 .1-1.1-.1-.1-.2zM216.4 132.3h.2h1.1v.2v.8l-.2 .1h-1.1l-.1-.2z"/>
<path d="M216.1 138.5l.2-.1 1.4 .1 .1 .2-.1 1.1-.2 .1-1.4-.1-.1-.2zM216.1 135.5h.2h1.4l.1 .2-.1 1.1-.2 .1-1.4-.1-.1-.2zM207.5 138h10.4l.1 .1v1.9l-.1 .1-6.7 .1-.2 .1v7.2l-.1 .1h-3.4v-.1v-1.3h1.6a.81 .81 0 0 0 .8 0l-.4-.4-.4 .4h-1.6v-1.2h.7l.1 .4 .4-.5h1.6l.4 .5a.81 .81 0 0 0 0-.9l-.4 .4h-1.6l-.4-.4-.1 .5h-.7v-1.3h1.6l.4 .4 .4-.4a.81 .81 0 0 0-.8 0h-1.6v-3.8h4.9l.1 .1 .4 .1v-.4h1.2v.4l.3-.1 .2-.1h1.2l.2 .1 .3 .1v-.4h1.2v.3l.3 .1 .2-.1v-.2l-2.1-.1-.1 .2h-1.2l-.1-.2h-2l-.1 .2h-4.9v-1.5h4.9l.1 .2h.4v-.3h1.2v.3h.4l.1-.2h1.2l.1 .2h.4v-.3h1.2v.3h.4l.1-.2-.2-.2h-1.8l-.2 .2h-1.2l-.2-.2h-1.8l-.2 .2h-4.9v-.3zM218.7 135.9h10.5l.1 .1v5.2a4.1 4.1 0 0 0-5.5 .9 4.1 4.1 0 0 0 .4 5.5h-5.5l-.1-.1v-1.8h1.1a.57 .57 0 0 0 .6-.6v-2.2a.57 .57 0 0 0-.6-.5h-1.1v-1.9l.9 .1 .2-.1h4.6l.3 .1 .2-.1-.3-.3-.2 .3h-4.6l-.2-.3-.3 .3h-.6v-.7l.2-.2h1.3l.2 .3 .1-.2h3.2l.1 .2 .2-.3h1.3l.2 .3 .1-.4-.1-.1-.2 .2h-1.3l-.2-.2-.1 .3h-3.2l-.1-.3-.2 .2h-1.3l-.2-.2v-.6h.6l.3 .2 .2-.2h4.6l.2 .2 .3-.2-.3-.1-.2 .1h-4.6l-.3-.1-.8 .1v-.9l.9 .1 .2-.1h4.6l.3 .1 .2-.1-.3-.2-.2 .2h-4.6l-.2-.2-.3 .2h-.6v-.6l.2-.2h1.3l.2 .2 .1-.2h3.2l.1 .2 .2-.2h1.3l.2 .2 .1-.4-.1-.1-.2 .3h-1.3l-.2-.3-.1 .3h-3.2l-.1-.3-.2 .3h-1.3l-.2-.2v-.7h.6l.3 .2 .2-.2h4.6l.2 .2 .3-.2-.3-.1-.2 .1h-4.6l-.3-.1-.8 .1zM74 145.5h.9l.1 .2-.1 .6-.2 .1-.7-.1-.1-.1zM74 143.1h.9l.1 .2-.1 .6-.2 .1-.7-.1-.1-.2zM75.7 145.5h.9l.1 .2v.6l-.2 .1-.8-.1v-.1zM75.7 143.1h.9l.1 .2v.6l-.2 .1-.8-.1v-.2zM78 144.7h1.1l.2 .1 .1 1.4-.1 .2h-1.1l-.2-.1-.1-1.4zM81 144.7h1.1l.2 .1v1.4l-.1 .2h-1l-.2-.1-.1-1.4zM83.3 144.7h1.1l.2 .1 .1 1.4-.1 .2h-1.1l-.2-.1v-1.4zM81 141h3.6v1.4h-3.6z"/>
<path d="M80.5 140.9v-.1h4.6l.1 .1v6.6l-.1 .1h-4.6v-.1v-1.1h.2l.1 .2h.2l.1-.5h1.1v.5h.2l.1-.2h.6l.1 .2h.2v-.5h1.2v.5h.2l.1-.2-.1-.3h-1.7v.3h-.6v-.3h-1.7l-.1 .3h-.2v-1.7h.2l.1 .3h.3v-.5h1.1v.5h.3v-.3h.6v.3h.3v-.5h1.2v.5h.2l.1-.3-.2-.2h-1.5l-.1 .2h-.6l-.2-.2h-1.4l-.2 .2h-.2v-2.3h.3l.2 .2h1.2v-.3h1.2v.3h1.2l.2-.2-.1-.1h-3.8l-.1 .1h-.3v-1.4h.3l.1 .1h1.3v-.2h1.2v.2h1.3l.1-.1-.2-.2h-3.6l-.2 .2h-.3zM86.3 144.7h1.1l.2 .1 .1 1.4-.1 .2h-1.1l-.2-.1-.1-1.4zM94.7 145.7l.7-.1 .1 .1 .1 .7-.1 .2-.6 .1-.2-.1zM94.7 144l.7-.1 .1 .1 .1 .7-.1 .2h-.6l-.2-.1zM97.2 145.9h2v.7h-2zM97.2 145h2v.6h-2zM97.2 144h2v.7h-2zM97.4 141h3.6v1.4h-3.6zM100.7 144h2v.7h-2zM100.7 145h2v.6h-2zM100.7 145.9h2v.7h-2zM104.1 145.7l.7-.1 .1 .1 .1 .7-.1 .2-.6 .1-.2-.1z"/>
<path d="M104.1 144l.7-.1 .1 .1 .1 .7-.1 .2h-.6l-.2-.1zM105.5 141.3l.2-.1 1.4 .1 .1 .2-.1 1.1-.2 .1-1.4-.1-.1-.2zM106.5 144l.7-.1 .2 .1v.7l-.1 .2h-.6l-.2-.1zM106.5 145.7l.7-.1 .2 .1v.7l-.1 .2-.6 .1-.2-.1zM113.7 140.2l.1-.1 1.1 .1 .1 .2-.1 .8-.1 .1-1.1-.1-.1-.2zM114.2 142.1l.8-.1 .2 .1v1.1v.2h-.9h-.1l-.1-1.1zM116.2 142.1l.8-.1 .2 .1 .1 1.1-.1 .2h-.8h-.2l-.1-1.1zM116.6 140.2l.2-.1 1 .1 .1 .2v.8l-.2 .1-1.1-.1-.1-.2zM119.3 142.6h.9l.1 .2-.1 .6-.1 .1-.8-.1-.1-.2zM121.1 142.6h.9l.1 .2-.1 .6-.2 .1-.7-.1-.1-.2zM123.1 142.6h.9l.1 .2v.6l-.2 .1-.8-.1v-.2zM124.9 142.6h.9l.1 .2-.1 .6-.2 .1-.7-.1-.1-.2z"/>
<path d="M135.5 141.3h1.2v1.2h-1.2zM142.9 140.8h1.5v1.9h-1.5zM142.9 144.9h1.5v1.9h-1.5zM141.9 144.1h6.7l.1 .1v3.3l-.1 .1h-6.7l-.1-.1v-.7h.9l.1 .1h.6v-.9h.4l.1 .9h.5l.2-.1-.1-.8h-1.8v.8h-.9v-1.9h.9v.7h.7v-.9h.4v.9h.8v-.8l-.2-.1h-1.5l-.2 .2h-.9v-.7zM156.6 141.3h1.2v1.2h-1.2zM163 140.8h1.5v1.9h-1.5zM163 144.9h1.5v1.9h-1.5zM161.6 144.2h8.6v.1v3.2v.1h-8.6l-.1-.1v-.7h1.3l.1 .1h.6v-.9h.4v.9h.6l.1-.1v-.8h-1.8v.8h-1.3v-1.9h1.3v.7h.7v-.9h.4v.9h.7v-.8l-.1-.1h-1.5l-.2 .2h-1.3v-.6zM213.9 142.9h1.7v2.2h-1.7zM211.7 140.8h4.7l.1 .1v6.6l-.1 .1h-4.7l-.1-.1v-2.4h2.1l.1 .2h.3l.1-.7h1.1l.1 .7h.3l.1-.2v-.5h-2.1v.5h-2.1v-2.2h2.1v.5h.5v-.6h1.1v.6h.5v-.5l-.1-.2h-1.8l-.2 .2h-2.1v-2zM217.9 142.9h1.8v2.2h-1.8z"/>
<circle cx="72.1" cy="55" r=".25"/>
<circle cx="73.3" cy="53.8" r=".25"/>
<circle cx="75.4" cy="56.6" r=".25"/>
<circle cx="79.1" cy="59.4" r=".25"/>
<circle cx="79.1" cy="53.8" r=".25"/>
<circle cx="82" cy="56" r=".25"/>
<circle cx="84.1" cy="59.7" r=".25"/>
<circle cx="84.2" cy="57.1" r=".25"/>
<circle cx="85.1" cy="53.8" r=".25"/>
<circle cx="87.4" cy="57.1" r=".25"/>
<circle cx="89" cy="57.1" r=".25"/>
<circle cx="91.1" cy="59.7" r=".25"/>
<circle cx="91.1" cy="53.8" r=".25"/>
<circle cx="91.6" cy="57.9" r=".25"/>
<circle cx="97.1" cy="53.8" r=".25"/>
<circle cx="100.8" cy="57" r=".25"/>
<circle cx="103.1" cy="53.8" r=".25"/>
<circle cx="103.1" cy="57.8" r=".25"/>
<circle cx="106.7" cy="59" r=".25"/>
<circle cx="109.1" cy="53.8" r=".25"/>
<circle cx="110" cy="57.8" r=".25"/>
<circle cx="111.8" cy="57.8" r=".25"/>
<circle cx="113.8" cy="59" r=".25"/>
<circle cx="114.9" cy="53.8" r=".25"/>
<circle cx="116" cy="55" r=".25"/>
<circle cx="121.7" cy="55" r=".5"/>
<circle cx="157.7" cy="57" r=".5"/>
<circle cx="162.8" cy="56.9" r=".5"/>
<circle cx="178.8" cy="53.8" r=".5"/>
<circle cx="181.9" cy="59.4" r=".75"/>
<circle cx="196.3" cy="59.4" r=".75"/>
<circle cx="205" cy="56.3" r="1"/>
<circle cx="210.1" cy="56.3" r="1"/>
<circle cx="215.1" cy="56.3" r="1"/>
<circle cx="227.1" cy="55.8" r="2.05"/>
<circle cx="72" cy="66.8" r=".25"/>
<circle cx="72" cy="78.8" r=".25"/>
<circle cx="72" cy="72.8" r=".25"/>
<circle cx="72.1" cy="60.8" r=".25"/>
<circle cx="74.7" cy="61.3" r=".6"/>
<circle cx="75.9" cy="60.2" r=".25"/>
<circle cx="76.3" cy="69.7" r=".25"/>
<circle cx="76.5" cy="64.6" r=".25"/>
<circle cx="76.6" cy="79.8" r=".25"/>
<circle cx="76.6" cy="79.2" r=".25"/>
<circle cx="77.2" cy="71.9" r=".25"/>
<circle cx="77.3" cy="61.3" r=".6"/>
<circle cx="78.4" cy="69.3" r=".25"/>
<circle cx="79" cy="74.3" r=".25"/>
<circle cx="79.1" cy="71.9" r=".25"/>
<circle cx="79.8" cy="65" r=".25"/>
<circle cx="79.8" cy="61.3" r=".6"/>
<circle cx="80.1" cy="69.3" r=".25"/>
<circle cx="80.8" cy="79.1" r=".25"/>
<circle cx="81.3" cy="77.1" r=".25"/>
<circle cx="84.2" cy="69.6" r=".25"/>
<circle cx="84.6" cy="65.1" r=".25"/>
<circle cx="84.7" cy="77.6" r=".25"/>
<circle cx="85.6" cy="76.2" r=".25"/>
<circle cx="85.7" cy="72.9" r=".25"/>
<circle cx="86" cy="74.3" r=".25"/>
<circle cx="86.1" cy="61" r=".25"/>
<circle cx="86.1" cy="70.9" r=".25"/>
<circle cx="86.2" cy="68.3" r=".25"/>
<circle cx="86.4" cy="73.3" r=".25"/>
<circle cx="87" cy="77" r=".25"/>
<circle cx="87.4" cy="63" r=".25"/>
<circle cx="88.5" cy="70.2" r=".25"/>
<circle cx="89" cy="74.5" r=".25"/>
<circle cx="89" cy="67.1" r=".25"/>
<circle cx="89.2" cy="61" r=".25"/>
<circle cx="89.5" cy="72.8" r=".25"/>
<circle cx="89.8" cy="65.5" r=".25"/>
<circle cx="89.8" cy="73.7" r=".25"/>
<circle cx="90.8" cy="63.7" r=".25"/>
<circle cx="91.1" cy="70.9" r=".25"/>
<circle cx="91.8" cy="67.4" r=".25"/>
<circle cx="93.3" cy="77.3" r=".25"/>
<circle cx="93.9" cy="61" r=".25"/>
<circle cx="95.3" cy="69.1" r=".25"/>
<circle cx="95.8" cy="61.1" r=".25"/>
<circle cx="95.9" cy="66" r=".25"/>
<circle cx="97.5" cy="67.2" r=".25"/>
<circle cx="97.9" cy="75.8" r=".25"/>
<circle cx="98.3" cy="63.5" r=".25"/>
<circle cx="98.3" cy="73.3" r=".25"/>
<circle cx="99.3" cy="78.6" r=".25"/>
<circle cx="100.2" cy="60.3" r=".25"/>
<circle cx="100.2" cy="66" r=".25"/>
<circle cx="100.3" cy="74.5" r=".25"/>
<circle cx="100.8" cy="79.7" r=".25"/>
<circle cx="101.5" cy="63.5" r=".25"/>
<circle cx="101.5" cy="73.3" r=".25"/>
<circle cx="101.7" cy="70.6" r=".25"/>
<circle cx="101.9" cy="68.6" r=".25"/>
<circle cx="102" cy="60.3" r=".25"/>
<circle cx="102" cy="65.8" r=".25"/>
<circle cx="102.2" cy="76.1" r=".25"/>
<circle cx="103.1" cy="73.3" r=".25"/>
<circle cx="103.3" cy="79" r=".25"/>
<circle cx="103.3" cy="63.5" r=".25"/>
<circle cx="105.9" cy="69.1" r=".25"/>
<circle cx="107.8" cy="66.3" r=".7"/>
<circle cx="108.4" cy="67.8" r=".7"/>
<circle cx="108.7" cy="60.3" r=".25"/>
<circle cx="109.9" cy="68.4" r=".7"/>
<circle cx="109.9" cy="64.2" r=".7"/>
<circle cx="110.6" cy="60.3" r=".25"/>
<circle cx="111.3" cy="64.8" r=".7"/>
<circle cx="112" cy="66.3" r=".7"/>
<circle cx="112.6" cy="60.8" r=".25"/>
<circle cx="116" cy="66.8" r=".25"/>
<circle cx="116" cy="72.8" r=".25"/>
<circle cx="116" cy="78.8" r=".25"/>
<circle cx="116.1" cy="60.8" r=".25"/>
<circle cx="118" cy="65.8" r=".25"/>
<circle cx="118" cy="68.3" r=".25"/>
<circle cx="118.1" cy="74.3" r=".25"/>
<circle cx="118.1" cy="76.6" r=".25"/>
<circle cx="120.3" cy="74.3" r=".25"/>
<circle cx="120.8" cy="64.6" r=".25"/>
<circle cx="121.9" cy="65.8" r=".25"/>
<circle cx="121.9" cy="74.2" r=".25"/>
<circle cx="123.2" cy="74.3" r=".25"/>
<circle cx="123.3" cy="65.8" r=".25"/>
<circle cx="123.8" cy="77.6" r=".25"/>
<circle cx="125.2" cy="65.8" r=".25"/>
<circle cx="125.3" cy="74.3" r=".25"/>
<circle cx="126.2" cy="77.6" r=".25"/>
<circle cx="127" cy="65.8" r=".25"/>
<circle cx="127" cy="74.2" r=".25"/>
<circle cx="128.9" cy="74.3" r=".25"/>
<circle cx="129.4" cy="69" r=".25"/>
<circle cx="130.2" cy="76.7" r=".25"/>
<circle cx="130.9" cy="74.3" r=".25"/>
<circle cx="132.6" cy="74.2" r=".25"/>
<circle cx="132.8" cy="78.9" r=".25"/>
<circle cx="133.9" cy="74.3" r=".25"/>
<circle cx="134.1" cy="61.8" r=".5"/>
<circle cx="135.4" cy="68.3" r=".5"/>
<circle cx="136.1" cy="74.3" r=".25"/>
<circle cx="137.8" cy="74.3" r=".25"/>
<circle cx="140.6" cy="68.3" r=".5"/>
<circle cx="145.7" cy="76.6" r=".5"/>
<circle cx="145.7" cy="67.7" r=".5"/>
<circle cx="150.7" cy="71.7" r=".5"/>
<circle cx="153.3" cy="71.6" r=".25"/>
<circle cx="153.3" cy="77.3" r=".25"/>
<circle cx="157" cy="72.3" r=".5"/>
<circle cx="159.1" cy="76.8" r=".5"/>
<circle cx="165.4" cy="62.1" r=".5"/>
<circle cx="165.4" cy="60" r=".5"/>
<circle cx="167.3" cy="76.4" r=".5"/>
<circle cx="172.3" cy="75.7" r=".5"/>
<circle cx="172.8" cy="62" r=".5"/>
<circle cx="174.9" cy="71.5" r=".5"/>
<circle cx="174.9" cy="76.8" r=".5"/>
<circle cx="178.8" cy="61.1" r=".5"/>
<circle cx="179.2" cy="75.4" r=".25"/>
<circle cx="181.5" cy="69.8" r=".5"/>
<circle cx="181.7" cy="75.3" r=".5"/>
<circle cx="183.3" cy="78.4" r=".25"/>
<circle cx="184" cy="75.9" r=".25"/>
<circle cx="186.2" cy="61" r=".5"/>
<circle cx="189.2" cy="66.5" r=".5"/>
<circle cx="190.4" cy="75.3" r=".5"/>
<circle cx="193.3" cy="75.4" r=".5"/>
<circle cx="205" cy="66.7" r="1"/>
<circle cx="205" cy="61.5" r="1"/>
<circle cx="205" cy="77.1" r="1"/>
<circle cx="205" cy="71.9" r="1"/>
<circle cx="210.1" cy="66.7" r="1"/>
<circle cx="210.1" cy="61.5" r="1"/>
<circle cx="210.1" cy="77.1" r="1"/>
<circle cx="210.1" cy="71.9" r="1"/>
<circle cx="215.1" cy="71.9" r="1"/>
<circle cx="215.1" cy="77.1" r="1"/>
<circle cx="215.1" cy="66.7" r="1"/>
<circle cx="215.1" cy="61.5" r="1"/>
<circle cx="219.5" cy="78.7" r=".75"/>
<circle cx="219.5" cy="68.5" r=".75"/>
<circle cx="219.5" cy="66" r=".75"/>
<circle cx="219.5" cy="71" r=".75"/>
<circle cx="219.5" cy="60.9" r=".75"/>
<circle cx="219.5" cy="63.4" r=".75"/>
<circle cx="219.5" cy="73.6" r=".75"/>
<circle cx="219.5" cy="76.1" r=".75"/>
<circle cx="224.5" cy="68.5" r=".75"/>
<circle cx="224.5" cy="66" r=".75"/>
<circle cx="224.5" cy="73.6" r=".75"/>
<circle cx="224.5" cy="71" r=".75"/>
<circle cx="224.5" cy="78.7" r=".75"/>
<circle cx="224.5" cy="63.4" r=".75"/>
<circle cx="224.5" cy="76.1" r=".75"/>
<circle cx="224.5" cy="60.9" r=".75"/>
<circle cx="72" cy="84.8" r=".25"/>
<circle cx="72" cy="90.8" r=".25"/>
<circle cx="72.1" cy="96.8" r=".25"/>
<circle cx="73.3" cy="98" r=".25"/>
<circle cx="75.7" cy="87.7" r=".25"/>
<circle cx="75.7" cy="91.6" r=".25"/>
<circle cx="77.2" cy="80.5" r=".25"/>
<circle cx="77.3" cy="90.8" r=".25"/>
<circle cx="77.3" cy="87.1" r=".25"/>
<circle cx="77.3" cy="94.5" r=".25"/>
<circle cx="77.3" cy="93.2" r=".25"/>
<circle cx="77.3" cy="89.5" r=".25"/>
<circle cx="77.3" cy="85.8" r=".25"/>
<circle cx="78.4" cy="90.8" r=".25"/>
<circle cx="78.4" cy="87.1" r=".25"/>
<circle cx="78.4" cy="94.5" r=".25"/>
<circle cx="78.4" cy="89.5" r=".25"/>
<circle cx="78.4" cy="93.2" r=".25"/>
<circle cx="78.4" cy="85.8" r=".25"/>
<circle cx="79.1" cy="98" r=".25"/>
<circle cx="79.1" cy="87.5" r=".25"/>
<circle cx="79.4" cy="80.1" r=".25"/>
<circle cx="80.4" cy="80.3" r=".25"/>
<circle cx="80.9" cy="94.2" r=".25"/>
<circle cx="80.9" cy="86.9" r=".25"/>
<circle cx="84.3" cy="95.1" r=".25"/>
<circle cx="84.3" cy="89.4" r=".25"/>
<circle cx="85.1" cy="98" r=".25"/>
<circle cx="85.6" cy="85.6" r=".25"/>
<circle cx="86.1" cy="81.8" r=".25"/>
<circle cx="86.1" cy="95.1" r=".25"/>
<circle cx="86.1" cy="83.1" r=".25"/>
<circle cx="87.2" cy="92.6" r=".25"/>
<circle cx="87.4" cy="89.4" r=".25"/>
<circle cx="87.4" cy="85.6" r=".25"/>
<circle cx="87.4" cy="80.3" r=".25"/>
<circle cx="87.9" cy="83.1" r=".25"/>
<circle cx="89.2" cy="80.3" r=".25"/>
<circle cx="91.1" cy="81.8" r=".25"/>
<circle cx="91.1" cy="98" r=".25"/>
<circle cx="91.6" cy="90.2" r=".25"/>
<circle cx="91.6" cy="82.6" r=".25"/>
<circle cx="92.7" cy="88.4" r=".25"/>
<circle cx="92.7" cy="85.3" r=".25"/>
<circle cx="92.8" cy="89.5" r=".25"/>
<circle cx="93" cy="93.8" r=".25"/>
<circle cx="93" cy="86.6" r=".25"/>
<circle cx="93" cy="95.1" r=".25"/>
<circle cx="93.9" cy="87.6" r=".25"/>
<circle cx="94.7" cy="95.1" r=".25"/>
<circle cx="95.5" cy="89.5" r=".25"/>
<circle cx="95.6" cy="88.1" r=".25"/>
<circle cx="95.8" cy="85.7" r=".25"/>
<circle cx="95.9" cy="93.8" r=".25"/>
<circle cx="96" cy="92.6" r=".25"/>
<circle cx="96.1" cy="87.1" r=".25"/>
<circle cx="96.6" cy="82.9" r=".25"/>
<circle cx="97.1" cy="98" r=".25"/>
<circle cx="97.5" cy="90.2" r=".25"/>
<circle cx="98" cy="95.1" r=".25"/>
<circle cx="98.3" cy="85.7" r=".25"/>
<circle cx="98.6" cy="92.5" r=".25"/>
<circle cx="99.1" cy="82.8" r=".25"/>
<circle cx="100.2" cy="81.5" r=".25"/>
<circle cx="100.2" cy="93" r=".25"/>
<circle cx="100.6" cy="87.6" r=".25"/>
<circle cx="101" cy="89.9" r=".25"/>
<circle cx="101.2" cy="95" r=".25"/>
<circle cx="101.5" cy="82.9" r=".25"/>
<circle cx="102" cy="81.5" r=".25"/>
<circle cx="102.2" cy="92.2" r=".25"/>
<circle cx="102.9" cy="85.5" r=".25"/>
<circle cx="103.1" cy="98" r=".25"/>
<circle cx="103.3" cy="80.3" r=".25"/>
<circle cx="103.5" cy="90.8" r=".25"/>
<circle cx="104" cy="86.4" r=".25"/>
<circle cx="105.3" cy="91.9" r=".25"/>
<circle cx="105.3" cy="90.7" r=".25"/>
<circle cx="106.2" cy="87.4" r=".25"/>
<circle cx="107.7" cy="96.1" r=".25"/>
<circle cx="107.7" cy="92.2" r=".25"/>
<circle cx="107.8" cy="86.2" r=".25"/>
<circle cx="109.1" cy="98" r=".25"/>
<circle cx="109.3" cy="95.9" r=".25"/>
<circle cx="109.7" cy="92.1" r=".25"/>
<circle cx="111" cy="88.6" r=".25"/>
<circle cx="111.6" cy="90.2" r=".25"/>
<circle cx="114.8" cy="98" r=".25"/>
<circle cx="116" cy="90.8" r=".25"/>
<circle cx="116.1" cy="86" r=".25"/>
<circle cx="116.1" cy="96.8" r=".25"/>
<circle cx="117.9" cy="86.5" r=".25"/>
<circle cx="118" cy="98.7" r=".25"/>
<circle cx="118.1" cy="82.7" r=".25"/>
<circle cx="118.9" cy="96.1" r=".25"/>
<circle cx="119.6" cy="91.9" r=".25"/>
<circle cx="119.8" cy="97.8" r=".25"/>
<circle cx="120.4" cy="82.2" r=".25"/>
<circle cx="121.2" cy="86.5" r=".25"/>
<circle cx="121.5" cy="91.9" r=".25"/>
<circle cx="121.7" cy="81.3" r=".25"/>
<circle cx="122.7" cy="95.2" r=".25"/>
<circle cx="122.8" cy="86.5" r=".25"/>
<circle cx="123.2" cy="82.7" r=".25"/>
<circle cx="124.2" cy="91.1" r=".25"/>
<circle cx="127" cy="82.5" r=".25"/>
<circle cx="127.1" cy="92.2" r=".25"/>
<circle cx="127.1" cy="85.8" r=".25"/>
<circle cx="127.1" cy="96.3" r=".25"/>
<circle cx="128.8" cy="82.6" r=".25"/>
<circle cx="128.9" cy="92" r=".25"/>
<circle cx="129.4" cy="98.5" r=".25"/>
<circle cx="129.5" cy="90.7" r=".25"/>
<circle cx="130" cy="93" r=".25"/>
<circle cx="130" cy="97.1" r=".25"/>
<circle cx="130.6" cy="98.5" r=".25"/>
<circle cx="130.8" cy="82.5" r=".25"/>
<circle cx="131" cy="93" r=".25"/>
<circle cx="131.3" cy="91.2" r=".25"/>
<circle cx="131.4" cy="98.6" r=".25"/>
<circle cx="132.3" cy="86.5" r=".25"/>
<circle cx="132.6" cy="82.6" r=".25"/>
<circle cx="132.6" cy="95.6" r=".25"/>
<circle cx="133.7" cy="85.3" r=".25"/>
<circle cx="133.9" cy="82.7" r=".25"/>
<circle cx="135.3" cy="91.3" r=".25"/>
<circle cx="137.5" cy="82.7" r=".25"/>
<circle cx="139.1" cy="87.6" r=".25"/>
<circle cx="139.7" cy="91.6" r=".25"/>
<circle cx="140.1" cy="98.2" r=".25"/>
<circle cx="140.1" cy="99.4" r=".25"/>
<circle cx="140.5" cy="96" r=".25"/>
<circle cx="144.5" cy="87.4" r=".25"/>
<circle cx="144.5" cy="93" r=".25"/>
<circle cx="144.7" cy="99" r=".25"/>
<circle cx="145.9" cy="97" r=".25"/>
<circle cx="148.8" cy="97.6" r=".25"/>
<circle cx="148.8" cy="96.9" r=".25"/>
<circle cx="148.8" cy="96.3" r=".25"/>
<circle cx="150.2" cy="92" r=".25"/>
<circle cx="150.6" cy="91.1" r=".25"/>
<circle cx="150.6" cy="98.2" r=".25"/>
<circle cx="150.7" cy="94.4" r=".25"/>
<circle cx="154.2" cy="94.7" r=".25"/>
<circle cx="154.6" cy="98.2" r=".25"/>
<circle cx="154.7" cy="91.1" r=".25"/>
<circle cx="154.8" cy="97.5" r=".25"/>
<circle cx="154.8" cy="96.9" r=".25"/>
<circle cx="154.8" cy="96.3" r=".25"/>
<circle cx="155.6" cy="90.9" r=".25"/>
<circle cx="155.6" cy="92.6" r=".25"/>
<circle cx="160.7" cy="95.9" r=".25"/>
<circle cx="160.7" cy="90.7" r=".25"/>
<circle cx="160.7" cy="98.5" r=".25"/>
<circle cx="160.8" cy="97.1" r=".25"/>
<circle cx="161" cy="91.9" r=".25"/>
<circle cx="161.1" cy="99.2" r=".25"/>
<circle cx="161.1" cy="93.1" r=".25"/>
<circle cx="161.2" cy="96.4" r=".25"/>
<circle cx="161.4" cy="91.3" r=".25"/>
<circle cx="161.5" cy="90" r=".25"/>
<circle cx="161.7" cy="98.6" r=".25"/>
<circle cx="162.2" cy="89.4" r=".25"/>
<circle cx="163.8" cy="98.4" r=".25"/>
<circle cx="167.7" cy="93.7" r=".25"/>
<circle cx="168.3" cy="91.3" r=".25"/>
<circle cx="168.3" cy="89.3" r=".25"/>
<circle cx="168.3" cy="90" r=".25"/>
<circle cx="168.4" cy="95.9" r=".25"/>
<circle cx="168.4" cy="97.8" r=".25"/>
<circle cx="174" cy="96.9" r=".25"/>
<circle cx="174" cy="92.8" r=".25"/>
<circle cx="175.9" cy="81.8" r=".5"/>
<circle cx="178" cy="92.6" r=".25"/>
<circle cx="178.7" cy="82.8" r=".5"/>
<circle cx="182.5" cy="90.4" r=".25"/>
<circle cx="182.5" cy="89.1" r=".25"/>
<circle cx="182.6" cy="98" r=".25"/>
<circle cx="188.8" cy="90.4" r=".25"/>
<circle cx="189" cy="89.1" r=".25"/>
<circle cx="189.2" cy="96.8" r=".25"/>
<circle cx="189.2" cy="98" r=".25"/>
<circle cx="194.9" cy="90.9" r=".25"/>
<circle cx="195.3" cy="97.1" r=".25"/>
<circle cx="198.9" cy="90.3" r=".25"/>
<circle cx="198.9" cy="92.2" r=".25"/>
<circle cx="198.9" cy="94.1" r=".25"/>
<circle cx="202.6" cy="97.8" r=".25"/>
<circle cx="204.9" cy="91.7" r=".25"/>
<circle cx="205.6" cy="85.2" r=".25"/>
<circle cx="205.7" cy="83.9" r=".25"/>
<circle cx="205.7" cy="83.3" r=".25"/>
<circle cx="205.7" cy="81.9" r=".25"/>
<circle cx="205.7" cy="81.3" r=".25"/>
<circle cx="205.7" cy="82.6" r=".25"/>
<circle cx="206.1" cy="91.7" r=".25"/>
<circle cx="209.4" cy="85.2" r=".25"/>
<circle cx="210.8" cy="90.2" r=".25"/>
<circle cx="219.5" cy="93.9" r=".75"/>
<circle cx="219.5" cy="81.2" r=".75"/>
<circle cx="219.5" cy="83.7" r=".75"/>
<circle cx="219.5" cy="91.4" r=".75"/>
<circle cx="219.5" cy="88.8" r=".75"/>
<circle cx="219.5" cy="99" r=".75"/>
<circle cx="219.5" cy="96.4" r=".75"/>
<circle cx="219.5" cy="86.3" r=".75"/>
<circle cx="224.5" cy="88.8" r=".75"/>
<circle cx="224.5" cy="93.9" r=".75"/>
<circle cx="224.5" cy="99" r=".75"/>
<circle cx="224.5" cy="86.3" r=".75"/>
<circle cx="224.5" cy="96.4" r=".75"/>
<circle cx="224.5" cy="81.2" r=".75"/>
<circle cx="224.5" cy="83.7" r=".75"/>
<circle cx="224.5" cy="91.4" r=".75"/>
<circle cx="78.1" cy="115.8" r=".5"/>
<circle cx="78.1" cy="118.4" r=".5"/>
<circle cx="80.5" cy="118.4" r=".5"/>
<circle cx="80.5" cy="115.8" r=".5"/>
<circle cx="83.1" cy="118.4" r=".5"/>
<circle cx="83.1" cy="115.8" r=".5"/>
<circle cx="83.4" cy="102.4" r=".25"/>
<circle cx="98.4" cy="118.4" r=".5"/>
<circle cx="98.4" cy="115.8" r=".5"/>
<circle cx="101" cy="118.4" r=".5"/>
<circle cx="101" cy="115.7" r=".5"/>
<circle cx="103.5" cy="118.4" r=".5"/>
<circle cx="103.5" cy="115.7" r=".5"/>
<circle cx="112.5" cy="109.2" r=".25"/>
<circle cx="113.8" cy="114.8" r=".25"/>
<circle cx="114" cy="111.1" r=".25"/>
<circle cx="114" cy="109.7" r=".25"/>
<circle cx="114" cy="110.5" r=".25"/>
<circle cx="114" cy="109" r=".25"/>
<circle cx="114" cy="111.8" r=".25"/>
<circle cx="114.9" cy="113.7" r=".25"/>
<circle cx="115.5" cy="105.5" r=".25"/>
<circle cx="115.6" cy="107.4" r=".25"/>
<circle cx="116" cy="106.7" r=".25"/>
<circle cx="116.8" cy="104.6" r=".25"/>
<circle cx="117.1" cy="113.7" r=".25"/>
<circle cx="117.5" cy="107.8" r=".25"/>
<circle cx="117.6" cy="104.8" r=".25"/>
<circle cx="117.7" cy="100.5" r=".25"/>
<circle cx="118" cy="103.8" r=".25"/>
<circle cx="118.1" cy="114.8" r=".25"/>
<circle cx="119.5" cy="106.5" r=".25"/>
<circle cx="120.2" cy="111.2" r=".25"/>
<circle cx="120.3" cy="109.2" r=".25"/>
<circle cx="120.3" cy="110.2" r=".25"/>
<circle cx="120.3" cy="112.2" r=".25"/>
<circle cx="120.5" cy="100.5" r=".25"/>
<circle cx="120.9" cy="107.8" r=".25"/>
<circle cx="121.4" cy="106.4" r=".25"/>
<circle cx="121.5" cy="105.4" r=".25"/>
<circle cx="122.6" cy="112" r=".25"/>
<circle cx="124.5" cy="117.1" r=".25"/>
<circle cx="128.1" cy="118.4" r=".25"/>
<circle cx="128.3" cy="115.6" r=".25"/>
<circle cx="129" cy="118.4" r=".25"/>
<circle cx="129.5" cy="108.6" r=".25"/>
<circle cx="130.7" cy="108.5" r=".25"/>
<circle cx="131.6" cy="104.8" r=".25"/>
<circle cx="131.8" cy="112.4" r=".25"/>
<circle cx="131.8" cy="101.5" r=".25"/>
<circle cx="132.3" cy="104.8" r=".25"/>
<circle cx="133.7" cy="108.6" r=".25"/>
<circle cx="134.2" cy="118.7" r=".25"/>
<circle cx="137" cy="119.9" r=".25"/>
<circle cx="137" cy="118.1" r=".25"/>
<circle cx="139.7" cy="108.3" r=".25"/>
<circle cx="140.2" cy="116.9" r=".25"/>
<circle cx="141.5" cy="119.2" r=".25"/>
<circle cx="141.5" cy="113.2" r=".25"/>
<circle cx="142.5" cy="108.6" r=".25"/>
<circle cx="144.5" cy="108.6" r=".25"/>
<circle cx="145.4" cy="102.9" r=".25"/>
<circle cx="146.2" cy="109.2" r=".25"/>
<circle cx="146.3" cy="110.9" r=".25"/>
<circle cx="146.4" cy="115.2" r=".25"/>
<circle cx="146.4" cy="110.2" r=".25"/>
<circle cx="148.7" cy="117.7" r=".25"/>
<circle cx="148.7" cy="118.7" r=".25"/>
<circle cx="148.9" cy="102.2" r=".25"/>
<circle cx="148.9" cy="103.6" r=".25"/>
<circle cx="149" cy="114.7" r=".25"/>
<circle cx="149.1" cy="119.2" r=".25"/>
<circle cx="149.5" cy="108.5" r=".25"/>
<circle cx="150.4" cy="113.5" r=".25"/>
<circle cx="150.5" cy="102.9" r=".25"/>
<circle cx="150.5" cy="111" r=".25"/>
<circle cx="150.5" cy="110.2" r=".25"/>
<circle cx="150.7" cy="104.1" r=".25"/>
<circle cx="150.7" cy="108.5" r=".25"/>
<circle cx="150.7" cy="100.2" r=".25"/>
<circle cx="151" cy="106.3" r=".25"/>
<circle cx="151.1" cy="113.5" r=".25"/>
<circle cx="151.4" cy="114.5" r=".25"/>
<circle cx="151.5" cy="101.7" r=".25"/>
<circle cx="152" cy="114.4" r=".25"/>
<circle cx="152.5" cy="115.1" r=".25"/>
<circle cx="152.9" cy="114.4" r=".25"/>
<circle cx="153" cy="105.8" r=".25"/>
<circle cx="153.4" cy="113" r=".25"/>
<circle cx="153.5" cy="106.2" r=".25"/>
<circle cx="153.8" cy="101.7" r=".25"/>
<circle cx="153.9" cy="105.8" r=".25"/>
<circle cx="153.9" cy="114.4" r=".25"/>
<circle cx="154.2" cy="113.3" r=".25"/>
<circle cx="154.3" cy="119.1" r=".25"/>
<circle cx="154.4" cy="106.3" r=".25"/>
<circle cx="154.6" cy="108.6" r=".25"/>
<circle cx="154.6" cy="104.1" r=".25"/>
<circle cx="155" cy="106" r=".25"/>
<circle cx="155.1" cy="114.4" r=".25"/>
<circle cx="155.1" cy="113" r=".25"/>
<circle cx="155.6" cy="106.3" r=".25"/>
<circle cx="155.8" cy="113" r=".25"/>
<circle cx="156" cy="108.5" r=".25"/>
<circle cx="156.6" cy="111.8" r=".25"/>
<circle cx="156.6" cy="113.8" r=".25"/>
<circle cx="157.1" cy="108.3" r=".25"/>
<circle cx="157.2" cy="105.7" r=".25"/>
<circle cx="157.2" cy="113.8" r=".25"/>
<circle cx="157.4" cy="118.2" r=".25"/>
<circle cx="157.5" cy="113.1" r=".25"/>
<circle cx="157.9" cy="105.7" r=".25"/>
<circle cx="158.2" cy="113.3" r=".25"/>
<circle cx="158.4" cy="119.4" r=".25"/>
<circle cx="158.5" cy="106.3" r=".25"/>
<circle cx="158.5" cy="108.6" r=".25"/>
<circle cx="158.5" cy="118.8" r=".25"/>
<circle cx="158.7" cy="116.1" r=".25"/>
<circle cx="159" cy="108.2" r=".25"/>
<circle cx="159.1" cy="119.5" r=".25"/>
<circle cx="159.3" cy="105.7" r=".25"/>
<circle cx="159.9" cy="105.7" r=".25"/>
<circle cx="160.4" cy="109.6" r=".25"/>
<circle cx="160.4" cy="108.8" r=".25"/>
<circle cx="160.4" cy="115.4" r=".25"/>
<circle cx="160.4" cy="117.8" r=".25"/>
<circle cx="160.8" cy="105.3" r=".25"/>
<circle cx="161.2" cy="117.2" r=".25"/>
<circle cx="161.5" cy="102.4" r=".25"/>
<circle cx="161.7" cy="108.5" r=".25"/>
<circle cx="161.9" cy="102.9" r=".25"/>
<circle cx="162" cy="104.3" r=".25"/>
<circle cx="163.6" cy="105.9" r=".25"/>
<circle cx="165.1" cy="103" r=".25"/>
<circle cx="165.2" cy="106" r=".25"/>
<circle cx="165.7" cy="117.3" r=".25"/>
<circle cx="166.4" cy="119.9" r=".25"/>
<circle cx="167.6" cy="114.5" r=".25"/>
<circle cx="167.8" cy="113.3" r=".25"/>
<circle cx="167.9" cy="119.2" r=".25"/>
<circle cx="167.9" cy="109.2" r=".25"/>
<circle cx="170.2" cy="115.4" r=".25"/>
<circle cx="170.3" cy="114.2" r=".25"/>
<circle cx="173.1" cy="109.7" r=".25"/>
<circle cx="173.1" cy="114" r=".25"/>
<circle cx="173.4" cy="113.4" r=".25"/>
<circle cx="173.5" cy="108.1" r=".25"/>
<circle cx="174.6" cy="102.4" r=".25"/>
<circle cx="175.3" cy="107.3" r=".25"/>
<circle cx="175.3" cy="108.8" r=".25"/>
<circle cx="175.3" cy="105.8" r=".25"/>
<circle cx="175.3" cy="111.9" r=".25"/>
<circle cx="176.1" cy="102.4" r=".25"/>
<circle cx="177.7" cy="108.3" r=".25"/>
<circle cx="177.9" cy="114.9" r=".25"/>
<circle cx="178.6" cy="111.5" r=".25"/>
<circle cx="178.8" cy="116.1" r=".25"/>
<circle cx="178.8" cy="112.5" r=".25"/>
<circle cx="179.3" cy="108.6" r=".25"/>
<circle cx="179.3" cy="109.6" r=".25"/>
<circle cx="179.3" cy="107.5" r=".25"/>
<circle cx="180.1" cy="112" r=".25"/>
<circle cx="180.3" cy="108.6" r=".25"/>
<circle cx="180.3" cy="109.6" r=".25"/>
<circle cx="180.3" cy="107.5" r=".25"/>
<circle cx="180.3" cy="108.6" r=".23"/>
<circle cx="180.5" cy="103.9" r=".25"/>
<circle cx="180.5" cy="101.8" r=".25"/>
<circle cx="180.6" cy="111.2" r=".25"/>
<circle cx="181" cy="111.8" r=".25"/>
<circle cx="181.4" cy="108.6" r=".25"/>
<circle cx="181.4" cy="109.6" r=".25"/>
<circle cx="181.4" cy="107.5" r=".25"/>
<circle cx="181.5" cy="104.8" r=".25"/>
<circle cx="181.6" cy="111.4" r=".25"/>
<circle cx="181.9" cy="113.2" r=".25"/>
<circle cx="182.1" cy="106.9" r=".25"/>
<circle cx="183" cy="101.8" r=".25"/>
<circle cx="183.3" cy="106.3" r=".25"/>
<circle cx="183.3" cy="110.4" r=".25"/>
<circle cx="183.5" cy="113.2" r=".25"/>
<circle cx="183.8" cy="107" r=".25"/>
<circle cx="184.3" cy="107.6" r=".25"/>
<circle cx="186.1" cy="115.1" r=".5"/>
<circle cx="187.7" cy="106.5" r=".25"/>
<circle cx="187.7" cy="110.4" r=".25"/>
<circle cx="187.7" cy="112.9" r=".25"/>
<circle cx="187.7" cy="104" r=".25"/>
<circle cx="189.9" cy="111.6" r=".25"/>
<circle cx="189.9" cy="105.3" r=".25"/>
<circle cx="196.5" cy="111.6" r=".25"/>
<circle cx="196.5" cy="105.3" r=".25"/>
<circle cx="207" cy="119.2" r=".5"/>
<circle cx="219.5" cy="104.1" r=".75"/>
<circle cx="219.5" cy="106.6" r=".75"/>
<circle cx="219.5" cy="114.2" r=".75"/>
<circle cx="219.5" cy="116.8" r=".75"/>
<circle cx="219.5" cy="101.5" r=".75"/>
<circle cx="219.5" cy="111.7" r=".75"/>
<circle cx="219.5" cy="119.3" r=".75"/>
<circle cx="219.5" cy="109.1" r=".75"/>
<circle cx="224.5" cy="109.1" r=".75"/>
<circle cx="224.5" cy="119.3" r=".75"/>
<circle cx="224.5" cy="101.5" r=".75"/>
<circle cx="224.5" cy="111.7" r=".75"/>
<circle cx="224.5" cy="106.6" r=".75"/>
<circle cx="224.5" cy="116.8" r=".75"/>
<circle cx="224.5" cy="104.1" r=".75"/>
<circle cx="224.5" cy="114.2" r=".75"/>
<circle cx="73.7" cy="134.1" r=".25"/>
<circle cx="75.3" cy="129.5" r=".25"/>
<circle cx="75.3" cy="130.4" r=".25"/>
<circle cx="75.3" cy="128.6" r=".25"/>
<circle cx="76.2" cy="130.4" r=".25"/>
<circle cx="76.2" cy="129.5" r=".25"/>
<circle cx="76.2" cy="128.6" r=".25"/>
<circle cx="77" cy="134.1" r=".25"/>
<circle cx="77.9" cy="139.7" r=".25"/>
<circle cx="77.9" cy="137.9" r=".25"/>
<circle cx="77.9" cy="137" r=".25"/>
<circle cx="77.9" cy="136.1" r=".25"/>
<circle cx="77.9" cy="138.8" r=".25"/>
<circle cx="78.1" cy="120.9" r=".5"/>
<circle cx="78.7" cy="134.4" r=".5"/>
<circle cx="78.7" cy="133.1" r=".5"/>
<circle cx="80" cy="133.1" r=".5"/>
<circle cx="80" cy="134.4" r=".5"/>
<circle cx="80" cy="136.1" r=".25"/>
<circle cx="80" cy="139.7" r=".25"/>
<circle cx="80" cy="137" r=".25"/>
<circle cx="80" cy="138.8" r=".25"/>
<circle cx="80" cy="137.9" r=".25"/>
<circle cx="80.5" cy="120.9" r=".5"/>
<circle cx="80.9" cy="136.1" r=".25"/>
<circle cx="80.9" cy="139.7" r=".25"/>
<circle cx="81.8" cy="139.7" r=".25"/>
<circle cx="83.1" cy="120.9" r=".5"/>
<circle cx="85.5" cy="136.6" r=".25"/>
<circle cx="85.5" cy="137.9" r=".25"/>
<circle cx="85.5" cy="139.2" r=".25"/>
<circle cx="85.7" cy="133.1" r=".5"/>
<circle cx="85.7" cy="134.4" r=".5"/>
<circle cx="87.1" cy="126.1" r=".5"/>
<circle cx="87.1" cy="127.4" r=".5"/>
<circle cx="87.1" cy="131.2" r=".5"/>
<circle cx="87.1" cy="128.6" r=".5"/>
<circle cx="87.1" cy="133.1" r=".5"/>
<circle cx="87.1" cy="134.4" r=".5"/>
<circle cx="87.1" cy="129.9" r=".5"/>
<circle cx="88.4" cy="126.1" r=".5"/>
<circle cx="88.4" cy="127.4" r=".5"/>
<circle cx="88.4" cy="128.6" r=".5"/>
<circle cx="88.4" cy="136.5" r=".5"/>
<circle cx="88.4" cy="133.1" r=".5"/>
<circle cx="88.4" cy="131.2" r=".5"/>
<circle cx="88.4" cy="137.8" r=".5"/>
<circle cx="88.4" cy="134.4" r=".5"/>
<circle cx="88.4" cy="129.9" r=".5"/>
<circle cx="89.7" cy="126.1" r=".5"/>
<circle cx="89.7" cy="127.4" r=".5"/>
<circle cx="89.7" cy="128.6" r=".5"/>
<circle cx="89.7" cy="131.2" r=".5"/>
<circle cx="89.7" cy="129.9" r=".5"/>
<circle cx="89.7" cy="134.4" r=".5"/>
<circle cx="89.7" cy="133.1" r=".5"/>
<circle cx="89.7" cy="137.8" r=".5"/>
<circle cx="89.7" cy="136.5" r=".5"/>
<circle cx="91.7" cy="137.8" r=".5"/>
<circle cx="91.7" cy="139.1" r=".5"/>
<circle cx="91.7" cy="136.5" r=".5"/>
<circle cx="91.8" cy="126.1" r=".5"/>
<circle cx="91.8" cy="127.4" r=".5"/>
<circle cx="91.8" cy="128.6" r=".5"/>
<circle cx="91.8" cy="131.2" r=".5"/>
<circle cx="91.8" cy="129.9" r=".5"/>
<circle cx="93" cy="139.1" r=".5"/>
<circle cx="93" cy="137.8" r=".5"/>
<circle cx="93" cy="136.5" r=".5"/>
<circle cx="93.1" cy="126.1" r=".5"/>
<circle cx="93.1" cy="127.4" r=".5"/>
<circle cx="93.1" cy="128.6" r=".5"/>
<circle cx="93.1" cy="131.2" r=".5"/>
<circle cx="93.1" cy="129.9" r=".5"/>
<circle cx="94.4" cy="126.1" r=".5"/>
<circle cx="94.4" cy="127.4" r=".5"/>
<circle cx="94.4" cy="128.6" r=".5"/>
<circle cx="94.4" cy="131.2" r=".5"/>
<circle cx="94.4" cy="129.9" r=".5"/>
<circle cx="97.2" cy="136.3" r=".25"/>
<circle cx="97.2" cy="135.2" r=".25"/>
<circle cx="97.2" cy="139.7" r=".25"/>
<circle cx="98.2" cy="135.2" r=".25"/>
<circle cx="98.4" cy="120.9" r=".5"/>
<circle cx="99.2" cy="135.2" r=".25"/>
<circle cx="100.2" cy="135.2" r=".25"/>
<circle cx="101" cy="120.9" r=".5"/>
<circle cx="101.2" cy="139.7" r=".25"/>
<circle cx="101.2" cy="135.2" r=".25"/>
<circle cx="101.2" cy="136.3" r=".25"/>
<circle cx="103.5" cy="120.9" r=".5"/>
<circle cx="104.6" cy="136.9" r=".25"/>
<circle cx="104.6" cy="137.9" r=".25"/>
<circle cx="104.6" cy="138.9" r=".25"/>
<circle cx="106.3" cy="137.9" r=".25"/>
<circle cx="107.4" cy="126.1" r=".5"/>
<circle cx="107.4" cy="127.4" r=".5"/>
<circle cx="107.4" cy="131.2" r=".5"/>
<circle cx="107.4" cy="128.6" r=".5"/>
<circle cx="107.4" cy="129.9" r=".5"/>
<circle cx="107.9" cy="138.9" r=".25"/>
<circle cx="107.9" cy="137.9" r=".25"/>
<circle cx="107.9" cy="136.9" r=".25"/>
<circle cx="108.7" cy="126.1" r=".5"/>
<circle cx="108.7" cy="127.4" r=".5"/>
<circle cx="108.7" cy="128.6" r=".5"/>
<circle cx="108.7" cy="129.9" r=".5"/>
<circle cx="108.7" cy="131.2" r=".5"/>
<circle cx="110" cy="126.1" r=".5"/>
<circle cx="110" cy="127.4" r=".5"/>
<circle cx="110" cy="131.2" r=".5"/>
<circle cx="110" cy="128.6" r=".5"/>
<circle cx="110" cy="129.9" r=".5"/>
<circle cx="111.8" cy="134.9" r=".25"/>
<circle cx="111.8" cy="133.9" r=".25"/>
<circle cx="111.8" cy="135.9" r=".25"/>
<circle cx="112.8" cy="133.9" r=".25"/>
<circle cx="112.8" cy="135.9" r=".25"/>
<circle cx="112.8" cy="134.9" r=".25"/>
<circle cx="112.9" cy="126.5" r=".25"/>
<circle cx="119.5" cy="135.4" r=".25"/>
<circle cx="120.3" cy="135.4" r=".25"/>
<circle cx="120.4" cy="132.1" r=".25"/>
<circle cx="121.5" cy="137.4" r=".25"/>
<circle cx="122.6" cy="137.4" r=".25"/>
<circle cx="122.8" cy="120.3" r=".25"/>
<circle cx="122.8" cy="124.6" r=".25"/>
<circle cx="122.8" cy="123.5" r=".25"/>
<circle cx="123.6" cy="133.4" r=".25"/>
<circle cx="123.6" cy="137.4" r=".25"/>
<circle cx="124" cy="121" r=".25"/>
<circle cx="124.3" cy="125.1" r=".25"/>
<circle cx="124.7" cy="127.5" r=".25"/>
<circle cx="125.2" cy="124.2" r=".25"/>
<circle cx="125.5" cy="135.9" r=".25"/>
<circle cx="127.8" cy="127.5" r=".25"/>
<circle cx="130.7" cy="127.5" r=".25"/>
<circle cx="131.6" cy="124.5" r=".25"/>
<circle cx="131.8" cy="127.5" r=".25"/>
<circle cx="132.8" cy="120.3" r=".25"/>
<circle cx="133.2" cy="124.3" r=".25"/>
<circle cx="133.2" cy="127.5" r=".25"/>
<circle cx="133.3" cy="122.2" r=".25"/>
<circle cx="134.5" cy="127.4" r=".25"/>
<circle cx="135.6" cy="124.3" r=".25"/>
<circle cx="136.8" cy="124.2" r=".25"/>
<circle cx="137" cy="123.4" r=".25"/>
<circle cx="137.3" cy="129.9" r=".25"/>
<circle cx="137.7" cy="127.5" r=".25"/>
<circle cx="138.7" cy="135.6" r=".25"/>
<circle cx="138.7" cy="136.6" r=".25"/>
<circle cx="138.7" cy="138.7" r=".25"/>
<circle cx="138.7" cy="137.7" r=".25"/>
<circle cx="138.7" cy="133.6" r=".25"/>
<circle cx="138.7" cy="134.6" r=".25"/>
<circle cx="138.7" cy="132.6" r=".25"/>
<circle cx="139.7" cy="133.6" r=".25"/>
<circle cx="139.7" cy="138.7" r=".25"/>
<circle cx="139.7" cy="134.6" r=".25"/>
<circle cx="139.7" cy="132.6" r=".25"/>
<circle cx="139.7" cy="137.7" r=".25"/>
<circle cx="139.7" cy="136.6" r=".25"/>
<circle cx="139.7" cy="135.6" r=".25"/>
<circle cx="140.2" cy="123.6" r=".25"/>
<circle cx="140.7" cy="127.6" r=".25"/>
<circle cx="141.6" cy="126.7" r=".25"/>
<circle cx="142.1" cy="132.3" r=".25"/>
<circle cx="142.1" cy="129" r=".25"/>
<circle cx="142.2" cy="133.6" r=".25"/>
<circle cx="144.7" cy="129" r=".25"/>
<circle cx="145.6" cy="122.3" r=".25"/>
<circle cx="146.4" cy="126.5" r=".25"/>
<circle cx="146.4" cy="120.2" r=".25"/>
<circle cx="147.3" cy="129" r=".25"/>
<circle cx="149" cy="120.1" r=".25"/>
<circle cx="149.1" cy="125.7" r=".25"/>
<circle cx="149.2" cy="129.8" r=".25"/>
<circle cx="149.4" cy="124.6" r=".25"/>
<circle cx="149.7" cy="122.2" r=".25"/>
<circle cx="149.9" cy="129.8" r=".25"/>
<circle cx="150.5" cy="129.8" r=".25"/>
<circle cx="151.1" cy="129.8" r=".25"/>
<circle cx="151.8" cy="129.8" r=".25"/>
<circle cx="151.9" cy="122.2" r=".25"/>
<circle cx="152.5" cy="129.7" r=".25"/>
<circle cx="152.9" cy="127.4" r=".25"/>
<circle cx="153" cy="130.1" r=".25"/>
<circle cx="153.5" cy="129.7" r=".25"/>
<circle cx="154.3" cy="120.1" r=".25"/>
<circle cx="154.5" cy="130" r=".25"/>
<circle cx="154.8" cy="130.6" r=".25"/>
<circle cx="155.4" cy="130.1" r=".25"/>
<circle cx="155.4" cy="131" r=".25"/>
<circle cx="156.6" cy="126.5" r=".25"/>
<circle cx="156.9" cy="122.8" r=".25"/>
<circle cx="157" cy="129.7" r=".25"/>
<circle cx="158.1" cy="127.5" r=".25"/>
<circle cx="158.5" cy="125.1" r=".25"/>
<circle cx="158.8" cy="120.2" r=".25"/>
<circle cx="159.5" cy="121.8" r=".25"/>
<circle cx="159.5" cy="121.2" r=".25"/>
<circle cx="160.3" cy="127.5" r=".25"/>
<circle cx="160.7" cy="122.7" r=".25"/>
<circle cx="160.7" cy="124.5" r=".25"/>
<circle cx="160.9" cy="127.5" r=".25"/>
<circle cx="161.4" cy="136.6" r=".25"/>
<circle cx="161.4" cy="135.6" r=".25"/>
<circle cx="161.4" cy="134.6" r=".25"/>
<circle cx="161.4" cy="137.7" r=".25"/>
<circle cx="161.4" cy="138.7" r=".25"/>
<circle cx="161.4" cy="133.6" r=".25"/>
<circle cx="161.5" cy="127.5" r=".25"/>
<circle cx="162.2" cy="120.5" r=".25"/>
<circle cx="162.4" cy="126" r=".25"/>
<circle cx="162.4" cy="138.7" r=".25"/>
<circle cx="162.4" cy="135.6" r=".25"/>
<circle cx="162.4" cy="134.6" r=".25"/>
<circle cx="162.4" cy="137.7" r=".25"/>
<circle cx="162.4" cy="136.6" r=".25"/>
<circle cx="162.4" cy="133.6" r=".25"/>
<circle cx="162.4" cy="127.5" r=".25"/>
<circle cx="163.1" cy="122.9" r=".25"/>
<circle cx="163.8" cy="122.9" r=".25"/>
<circle cx="164.1" cy="127.6" r=".25"/>
<circle cx="164.6" cy="122.9" r=".25"/>
<circle cx="165.2" cy="129.8" r=".25"/>
<circle cx="165.4" cy="123" r=".25"/>
<circle cx="166.2" cy="122.9" r=".25"/>
<circle cx="166.5" cy="127.6" r=".25"/>
<circle cx="166.5" cy="132.8" r=".25"/>
<circle cx="167" cy="127.2" r=".25"/>
<circle cx="167.7" cy="120.8" r=".25"/>
<circle cx="168.4" cy="137.2" r=".25"/>
<circle cx="170.1" cy="125.1" r=".25"/>
<circle cx="176.1" cy="131.8" r="1.1"/>
<circle cx="176.1" cy="121.7" r="1.1"/>
<circle cx="196.5" cy="129.3" r="1.1"/>
<circle cx="196.5" cy="134.4" r="1.1"/>
<circle cx="205" cy="134.9" r="1.15"/>
<circle cx="207" cy="120.5" r=".5"/>
<circle cx="207" cy="121.8" r=".5"/>
<circle cx="209.5" cy="134.9" r="1.15"/>
<circle cx="213.4" cy="120.1" r=".5"/>
<circle cx="219.5" cy="126.9" r=".75"/>
<circle cx="219.5" cy="129.5" r=".75"/>
<circle cx="219.5" cy="139.6" r=".75"/>
<circle cx="219.5" cy="137.1" r=".75"/>
<circle cx="219.5" cy="132" r=".75"/>
<circle cx="219.5" cy="134.5" r=".75"/>
<circle cx="219.5" cy="124.4" r=".75"/>
<circle cx="219.5" cy="121.8" r=".75"/>
<circle cx="224.5" cy="126.9" r=".75"/>
<circle cx="224.5" cy="132" r=".75"/>
<circle cx="224.5" cy="129.5" r=".75"/>
<circle cx="224.5" cy="137.1" r=".75"/>
<circle cx="224.5" cy="139.6" r=".75"/>
<circle cx="224.5" cy="134.5" r=".75"/>
<circle cx="224.5" cy="121.8" r=".75"/>
<circle cx="224.5" cy="124.4" r=".75"/>
<circle cx="75.3" cy="141.9" r=".25"/>
<circle cx="77.6" cy="143.5" r=".5"/>
<circle cx="81.4" cy="147.1" r=".5"/>
<circle cx="82.8" cy="143.5" r=".5"/>
<circle cx="82.8" cy="147.1" r=".5"/>
<circle cx="84.1" cy="147.1" r=".5"/>
<circle cx="84.1" cy="143.5" r=".5"/>
<circle cx="95.1" cy="146.9" r=".25"/>
<circle cx="95.1" cy="143.6" r=".25"/>
<circle cx="97.2" cy="140.7" r=".25"/>
<circle cx="98.2" cy="140.7" r=".25"/>
<circle cx="99.2" cy="140.7" r=".25"/>
<circle cx="100.2" cy="140.7" r=".25"/>
<circle cx="101.2" cy="140.7" r=".25"/>
<circle cx="103.1" cy="145.3" r=".25"/>
<circle cx="104.5" cy="143.1" r=".5"/>
<circle cx="111.8" cy="140.7" r=".25"/>
<circle cx="111.8" cy="141.7" r=".25"/>
<circle cx="111.8" cy="142.7" r=".25"/>
<circle cx="112.8" cy="141.7" r=".25"/>
<circle cx="112.8" cy="142.7" r=".25"/>
<circle cx="112.8" cy="140.7" r=".25"/>
<circle cx="119.8" cy="143.8" r=".25"/>
<circle cx="120.3" cy="141.2" r=".25"/>
<circle cx="123.6" cy="141.2" r=".25"/>
<circle cx="123.6" cy="142.2" r=".25"/>
<circle cx="124.8" cy="141.2" r=".25"/>
<circle cx="131.1" cy="141.9" r=".6"/>
<circle cx="133.6" cy="141.9" r=".6"/>
<circle cx="145.2" cy="145.4" r=".5"/>
<circle cx="145.2" cy="146.9" r=".5"/>
<circle cx="146.4" cy="146.9" r=".5"/>
<circle cx="147.7" cy="146.9" r=".5"/>
<circle cx="152.1" cy="141.9" r=".6"/>
<circle cx="154.7" cy="141.9" r=".6"/>
<circle cx="167" cy="146.8" r=".5"/>
<circle cx="168.3" cy="146.8" r=".5"/>
<circle cx="169.5" cy="146.8" r=".5"/>
<circle cx="176.1" cy="142" r="1.1"/>
<circle cx="196.5" cy="142" r="1.1"/>
<circle cx="205" cy="144.9" r="1.15"/>
<circle cx="209.5" cy="144.9" r="1.15"/>
<circle cx="212" cy="145.3" r=".25"/>
<circle cx="212" cy="141.5" r=".25"/>
<circle cx="212" cy="144" r=".25"/>
<circle cx="212" cy="146.6" r=".25"/>
<circle cx="212" cy="142.7" r=".25"/>
<circle cx="216.2" cy="145.3" r=".25"/>
<circle cx="216.2" cy="141.5" r=".25"/>
<circle cx="216.2" cy="144" r=".25"/>
<circle cx="216.2" cy="146.6" r=".25"/>
<circle cx="216.2" cy="142.7" r=".25"/>
<circle cx="217.7" cy="144" r=".5"/>
<circle cx="227.1" cy="144.7" r="2.05"/>
</g>
<g fill="#000">
<circle cx="184.3" cy="75.9" r=".32"/>
<circle cx="155.6" cy="90.9" r=".19"/>
<circle cx="90.4" cy="105.9" r=".6"/>
<circle cx="90.4" cy="103.4" r=".6"/>
<circle cx="91.7" cy="104.6" r=".6"/>
<circle cx="114.7" cy="118.5" r=".85"/>
<circle cx="117.2" cy="118.5" r=".85"/>
<circle cx="114.7" cy="121" r=".85"/>
<circle cx="114.7" cy="123.6" r=".85"/>
<circle cx="114.7" cy="126.1" r=".85"/>
<circle cx="114.7" cy="128.6" r=".85"/>
<circle cx="117.2" cy="121" r=".85"/>
<circle cx="117.2" cy="126.1" r=".85"/>
<circle cx="117.2" cy="123.6" r=".85"/>
<circle cx="141.9" cy="136" r=".5"/>
<circle cx="143.1" cy="136" r=".5"/>
<circle cx="143.1" cy="137.3" r=".5"/>
<circle cx="144.4" cy="136" r=".5"/>
<circle cx="144.4" cy="137.3" r=".5"/>
<circle cx="145.7" cy="137.3" r=".5"/>
<circle cx="145.7" cy="136" r=".5"/>
<circle cx="146.9" cy="136" r=".5"/>
<circle cx="146.9" cy="137.3" r=".5"/>
<circle cx="165.5" cy="137" r=".85"/>
</g>
<path d="M89 104.6h.4" fill="none" stroke="#000" stroke-width="1.2"/>
<g fill="none" stroke="#000" stroke-width=".14">
<path d="M76.6 79.8h-.8M76.6 79.2h-.8M116.1 60.8h.1M95.9 93.8h1.1M101.3 91.9h.7l.2 .3M111 88.6v.6M116.1 84.8v1.2M132.6 82.6h-.6M137 82.6l.5 .1M150.2 91.9h-.5l.1 .1h1.5M150.2 91.9v.1M150.2 92h.1"/>
<path d="M154.1 92h1.4l.1-.1v.7M154.8 96.9h.8M154.8 96.3h.8M154.8 97.5l.8 .1M159.7 95.9h1M168.4 97.8h1M169.4 97.8h.1M169.4 95.9h-1M174.7 97.8v1l-.5 .6h-3l-5.2 5.2v2.7M175.4 97.8v1l-.8 .8h-3.3l-4.8 4.8v2.9M175.4 91.9v1.2l.6 .6h2.6l.7-.7h2M176 97.8v1l-1.1 1.1h-3.5l-4.4 4.4v3"/>
<path d="M176 91.9v1.1l.5 .5h1.8l1.2-1.2h3.1l.3 .4v1.3l-.2 .2h-1.4M178 91.9v.7M181.3 91.7h-1.8l-1.1-1h-3.3l-.4 .4v.8M204.6 83.9h1.1M204.6 83.3h1.1M204.6 82.6h.1M204.6 82.6h1.1M205.7 81.3h-1.1M205.7 81.9l-1.1 .1M227.6 93.3h1.7M227.6 95h1.7M227.6 96.6h1.7"/>
<path d="M227.6 98.3h1.7M227.6 99.9h1.7M227.6 91.7h1.7v9.9h-1.7zM114 111.8v.2l.4 .4h.7M114.9 105.5h.6M114.9 107.4h.7M115.1 109.3h-.8l-.3 .4M115.1 110.9h-.9l-.2 .2M115.5 105.5h.1M116.8 109.3h.6l.3 .4h3.6M116.8 112.4h1.6l.4 .3h2.5M117.1 113.7h4.2"/>
<path d="M117.3 113.2h.1M118.5 107.4v.5l-.5 .6h-4.1l-.9 .8h-.4l-.1-.1M120.3 109.2h1M120.3 110.2h1M120.3 112.2h1M121.3 109.2h.1M121.3 110.2h.1M121.3 110.7h-4.3l-.2 .2M121.3 113.2h-5.9l-.5 .5M128.3 115.6l1.5 1.5v2.8l5.4 5.4v3.3M130.7 108.4v.1M130.7 107.3v1.1"/>
<path d="M134.2 118.7l4 4v5.9M137 118.1l2.7 2.7v7.8M142.6 114.7h1.9l1 1h2.1M142.6 113.7h2.4l.5 .5h2.1M142.6 115.2h1.5l1 1h2.5M142.6 112.7h2.1l1 1h1.9M142.6 115.7h1.3l1 1h2.7M142.6 112.2h2.3l1 1h1.7M144.5 108.6v.4l.8 .7h2.3M146.2 109.2h1.4M146.4 110.2h1.2M146.4 110.2h.1"/>
<path d="M147.6 119.7h1.1l.3 .4M147.6 117.2h-2.7l-.5 .5h-1.8M147.6 119.2h1.5M147.6 118.7h1.1M147.6 112.2h1.6l.5 .6v1.2l.5 .5h1.2M147.6 111.7h2.9l.6 .7v1.1M148.7 117.7h-1.1M149 114.7h-1.4M151 107.3h.1M151 106.3v1M153 105.8h.1M153 105.8v1.5"/>
<path d="M153.4 113v1.5l.5 .5 12.8-.1 1.3 1.3h.9M153.5 106.2v1.1M153.9 105.8l.1 1.5M154.4 106.3l.1 1M154.7 112.9h.1M155 106v1.3M155 106h.1M155.1 113v.4l1.3 1.3h10.4l1 1h1.1M155.6 106.3l-.1 .1v.9M155.6 102.9h-2.3l-1.3 1.3v3.1M155.6 102.2h-2.4l-1.6 1.5v3.5l-.1 .1M155.6 103.5h-2.1l-1 1.1v2.7"/>
<path d="M155.8 113v.7l.8 .7h10.3l.8 .8h1.2M157 107.3v.9l.1 .1M157.2 105.7l.3 .3v1.3M157.4 118.2l-4.5 4.5h-5.3M157.5 113.1l.2 .2v.6l.3 .3h9.1l.4-.5h1.4M157.9 105.7l.1 .2v1.4M158.4 119.4l-3.9 3.9v5.3M158.5 106.3h.1M158.5 106.3v1M158.5 118.8h-.3l-4.2 4.1v5.7M158.7 116.1v1.5l-7.6 7.6h-3.5M159 107.3v.9"/>
<path d="M159.1 119.5l-.3 .3h-.2l-3.6 3.6v5.2M159.3 105.7l.2 .3v1.3M159.9 105.7l.1 .1v1.5M160.4 115.4h-4.1l-5.4 5.3h-3.3M160.4 117.8v3.4l1.6 1.5v5.9M160.5 107.3v.8l-1.7 1.6h-5.5l-1.5 1.6v2.2l-.5 .5h-.5l-.4-.5M161 107.3v.9l-.6 .6M161.2 117.2l1 1.1v2.2M161.9 102.9h1M162.9 103.6h1.7l.5 .5v.5l-.4 .4h-1l-.7 .7v1.6M162.9 104.2l-.9 .1h.5v3M163.6 105.9l-.1 .1v1.3"/>
<path d="M164 107.3v2.1l-.7 .7h-10l-1.3 1.3v3M164.5 107.3v2.1l-1.1 1.1h-9.7l-1.2 1.2v3.4M165 107.3v2.4l-1 1h-10.2l-.9 .9v2.8M165.1 104.1h.1M165.2 106l.3 .3v1M168.9 112.7h-1.7l-.1-.1h-9.9l-.2 .3v.6l.2 .3M168.9 114.7h.7l.6 .7M168.9 117.7h-3.3l-1.8 1.8v3.4M168.9 113.2l-1.1 .1M168.9 111.7l-11.5 .1-.7 .6h-1.6l-.4 .4v1.2l.4 .4M168.9 116.7h-3.3l-2.5 2.5v3.7M168.9 112.2h-11.6l-.7 .7v.9"/>
<path d="M168.9 111.2h-13.7l-1.4 1.4v1.3l.1 .2v.3M168.9 118.2h-3l-1.3 1.3v3.4M168.9 118.7h-2.5l-1 1v3.3M168.9 117.2l-3.2 .1M171.2 117h-1l-.2 .2 .2 .2h1v.3M171.2 117.7l-.1 .1h-.9l-.2 .2 .1 .2h.7l.1 .2v3.4l-.9 .9h-1.1M171.2 116.9v.1M171.2 117.7h.1M171.2 115.9h.1M171.3 115.9l.9 .1 .1 .1-.1 .2h-.6l-.1 .2 .1 .2h.6l.1 .3h-.7l-.2 .2 .2 .2h.7l-.1 .3h-.6l-.1 .2 .1 .2h.6l.1 .2-.1 .1h-.9l-.1 .2 .2 .2h.8l.1 .2-.1 .1h-.9l-.1 .2 .2 .2h.8l.1 .2-.1 .1h-.9l-.1 .2 .2 .2h.8l.1 .2-.1 .1h-.9l-.1 .2 .2 .2h.8l.1 .2-.1 .1-.4 .1v.6l-1.4 1.3h-1.5M171.5 112.2l.1 .2M171.5 112.2h.1"/>
<path d="M171.6 112.2h-.1M171.6 112.4v.1M171.6 112.5h.1M171.6 112.2h.1M171.6 112.9v.2M171.6 113.1v.1M171.6 112.9h.1M171.6 113.2h.1M171.6 112.1v.1M171.6 112.8v.1M171.6 112.1h.1M171.6 112.5h1l.2 .2-.2 .1h-.9"/>
<path d="M171.7 113.2h.5l.1 .2-.1 .1h-.9v.3l.9 .1 .1 .2-.1 .1h-.9l-.1 .3 .2 .1h.8l.1 .2-.1 .1h-.8l-.2 .2 .2 .2h.8l.1 .2-.1 .1h-.9l-.1 .3M171.7 112.8h-.1M173.1 109.7h.9l.1 .2v.5M173.3 102.4v1.4l.9 .9h4.4l1 1v.9M174.1 111.9l-1.5 1.5v1.2l.2 .2h2.2l.2 .1v.3l-.3 .1h-2.1l-.2 .1v.2l.2 .2h2.2l.2 .1v.2l-.3 .2h-2.1l-.2 .1v.2l.2 .2h2.2l.2 .1v.2l-.3 .2h-2.1l-.2 .1v.2l.2 .2h2.2l.2 .1v.2l-.3 .2h-2.1l-.2 .1v.2l.2 .2h2.2l.2 .1v.2l-.3 .2h-2.1l-.2 .1v2.9l-.4 .4a.41 .41 0 0 1-.6-.2l-.2 .1v.3l1 1v.2l-.1 .2h-.2l-.7-.6h-2.5M174.1 108.8h-1l-1.3 1.4v1.5l.1 .1h.7l.2 .2-.2 .1h-1M174.1 107.3l-1.8 .1-.6-.5h-.2l-.1 .2 1.2 1.2v.2l-.1 .1h-.2l-1.1-1.1-.2-.1-.1 .3 .5 .6-.5 .6a.24 .24 0 0 0-.3 .2 .24 .24 0 0 0 .2 .3h.5l.1 .3-.2 .1h-.9l-.1 .1v.2l.1 .1h.9l.1 .3-.2 .1h-1l-.2 .3 .2 .1h1.1l.1 .1v.2l-.2 .1h-1l-.2 .3 .2 .1h1.1l.1 .3-.1 .1h-1.1l-.2 .3 .2 .1h1.1l.1 .2-.1 .2h-1.1l-.1 .1 .1 .3h.7l.1 .2v2.5l-.1 .1h-.7l-.1 .2 .2 .2h1v.3M174.8 113.8h.1M175.9 113.4h-.6l-.7 .7-1.5-.1M177.3 102.4v1.6l.4 .4h1.1l1.3 1.3v.9M177.9 114.9h.9M178.8 114.9h.1"/>
<path d="M76.2 129.5h-.9v.9M77.9 137.9h2.1v.9M77.9 136.1v.9M77.9 138.8v.9M78 128.5h-1.6l-.2 .1M78.7 133.1h1.3M80 134.4l.3-.3h5.8l1-1h-1.4v1.3M80 136.1v.9M80 139.7h.9M88.4 136.5v.5l-1 .9h-1.9v1.3M88.4 133.1h1.3M88.4 134.4h1.3"/>
<path d="M89.7 136.5v1.3M91.7 139.1h1.3M91.8 126.1l2.4 2.4h4.2M91.8 129.9h1.3M91.8 128.6v2.6M91.8 127.4h2.6M93 137.8l.1 .1h2.3M93 136.5h-1.3v1.3M94.4 128.6v-2.5h-1.3v5.1M94.4 129.9v1.3M97.2 135.2h4M97.2 139.7v1"/>
<path d="M101.2 139.7v1M103 137.9h1.6v1M106.3 137.9h1.6M107.9 136.9v2M108.7 129.9v1.3M111.8 133.9v1M111.8 135.9h2.9M112.8 133.9v1M121.3 125.2h-2.2l-.4-.4h-2.7l-1.3 1.3M121.3 125.7h-2.2l-.4 .4h-1.5M132.8 120.3v-1.6l.5-.4h1.4l4 4v6.3M134.5 127.4l-.3 .3v.9"/>
<path d="M135.1 135.6h4.6v1M136.8 124.2l.4 .4v5.2l.1 .1M137.7 127.5v1.1M138.7 133.6v1M138.7 137.7v1M138.7 132.6h1M139.7 133.6v1M139.7 137.7v1M140.2 123.6v5M140.2 123.6h.1M141.6 126.7h1M142.6 126.7h.1"/>
<path d="M145.6 122.3v.7l.7 .7h1.3M149.1 125.7h-1.5M149.5 128.6v.9l-.3 .3M149.7 122.2h-2.1M150 128.6v1.1l-.1 .1M150.5 129.8h.1M150.5 128.6v1.2M151 128.6v1.1l.1 .1M151.5 128.6v.9l.3 .3M152.5 128.6v1.1M153 128.6v1.5M153.5 128.7v1"/>
<path d="M153.5 128.6v.1M155.2 130.5v.1M156.5 135.6h5.9M157 128.6v1M157 129.6v.1M158 128.6v1.3l-.4 .4h-1.3l-.6-.6h-.9l-.3 .3M158.5 128.6v1.2l-.8 .8h-1.5l-.4-.5h-.4M158.8 120.2l-3.3 3.4v5M159 128.6v1.2l-1 1h-1.9l-.3-.3-1 .1M159.5 128.6v1.2l-1.3 1.3-2.8-.1M159.5 121.8l-2.3 2.3v2.4l-.7 .7v1.4M159.5 121.2l-3.5 3.5v3.9"/>
<path d="M161.4 133.6v1h1M161.4 136.6h1M162 128.6h.1M162.4 137.7h-1v1M162.4 127.5l.1 1.1M166.5 127.6v1M166.5 127.6h.1M167 127.3v1.3M167 127.2v.1M168.9 124.7h-5.2l-1.3 1.3M168.9 120.2h-2l-.7 .7v2M168.9 120.7l-1.2 .1"/>
<path d="M205.1 120.5h1.9M207 120.5h.1M207 120.5v1.3M81.6 145.5v1.3l-.2 .3M82.8 141.7v1.8M82.8 147.1h1.3M98.2 140.7h2M99.2 140.7v1M111.8 140.7v1M111.8 142.7h2.9M112.8 140.7v1M143.6 145.8l.1 1.1h1.5"/>
<path d="M146.4 146.9h1.3M167 146.8h1.3M212 144h4.2v2.6M212 141.5v1.2M212 145.3v1.3"/>
</g>
<g fill="none" stroke="#000" stroke-width=".51">
<path d="M74.7 56.6h.7M84.1 59.7h1.1M103.1 57.8h1.1M106.7 59h1.1M111.8 57.8h.9M121.3 59.7v1.4M126.4 59.7v1.1l-.3 .3h-5.8l-.4 .4v6.3l-.4 .4-1.5 .1M76.3 71.9h.9M76.5 64.6h.6M79.8 64.4v.6M80.1 69.3h1.1M81.3 77.1h.6"/>
<path d="M85.2 61h.9M85.2 70.9h.9M89.2 61h.9M97.9 75.8h1.4M99.3 60.3h.9M99.3 66h.9M99.3 74.5h1.4l.4 .4v1.3l.6 .6h4.6l2.5 2.6v14.9l-1.1 1.1v.7M100.8 79.7v.4l-.2 .2h-1.3M103.3 63.5h.9M107.8 60.3h.9M112.7 60.3l-.1 .5M118.1 76.6h.6v2l1.8 1.7h14.8l1.7-1.7v-2"/>
<path d="M118.1 76.6h.1M118.7 74.2l-.6 .1M118.7 65.7l-.7 .1M121.3 65.7l.6 .1M121.3 76.6v1.4l.8 .8h8.6l1.3-1.2v-1M121.9 74.2h-.6M123.8 74.2l-.6 .1M123.8 65.7l-.5 .1M123.8 76.6v1M126.4 76.6l-.2 .2v.8M127 74.2h-.6M129.4 74.2l-.5 .1"/>
<path d="M132.6 74.2h-.6M134.5 76.6v1.6l-.7 .7h-1M134.5 74.2l-.6 .1M180 74.3l.2 .2v3.6l-.2 .2 3.3 .1M83.4 89.4h.9M83.4 95.1h.9M85.2 81.8h.9M85.2 83.1h.9M87.2 92.6h1.1M87.4 89.4h.9M87.4 85.6h.9M89.2 80.3l.1 .2h.8"/>
<path d="M91.6 82.6v.3l-.2 .2h-1.3M92 93.8h1M92 95.1h1M95.9 82.9h.7M96 92.6h1M97 95.1h1M99.1 82.8v.6l.8 .8h1.4M99.3 81.5h.9M101.3 94.5l-.1 .5M101.3 86.7h1.2l.5 .5h1.6l.6-.5h1v1.3M103.3 80.3h.9M105.3 91.9h.9"/>
<path d="M105.3 90.7h.9M118.6 91.9h1M118.7 82.6l-.6 .1M118.8 97.8h1M122.7 95.2h1.1M122.8 86.5h1.1M123.8 82.6l-.6 .1M124.2 91.1v.8M127 82.5l-.6 .1M127.1 85.2v.6M127.1 92.2v3.3M128.8 82.6h.1"/>
<path d="M128.8 82.6h.6M129.5 89.8v.9M129.5 90.7h.1M134.5 82.6l-.6 .1M143.6 93.1h1.9M143.6 99.7h.1v2M144.5 93l.1 .1M144.5 97.7v1.2l.2 .1M148.1 95.1h-.1M148.2 99.6l-.1 .1M149.7 90.2v.2l.7 .7h.2M150.6 98.2h-.9"/>
<path d="M154.6 98.2h1M181.3 98h1.3M181.3 90.4h1.2M181.3 89.1h1.2M188.8 90.4h1.8M189 89.1h1.6M189.2 98h1.4M189.2 96.8h1.4M206.1 91.7h1.5M212.6 96.3h1.9l2.7 2.7h2.3M82.7 102.4h.7M113.2 114.8h.6"/>
<path d="M114.9 105.5h.5M115.4 105.5h.1M116.9 106.4h-.7l-.2 .3M116.9 107.4l.6 .4M117.6 104.8v.3l-.3 .4h-.2M118 103.8l.5 .5v1.2M118.1 114.8h.6M120.7 106.4h.7M121.5 105.4l-.8 .1M133 104.9h2M133 104.8h2M145.4 101.7v1.2"/>
<path d="M161.5 102.4l.1-.1h3.4l.1 .1v.6M173.3 102.4h1.3M176.1 102.4h1.2M188.7 111.6h1.2M188.7 105.3h1.2M196.5 111.6h1.1M197.6 105.3h-1.1M209.7 119.8h1.2l1.6 1.5v2.3l.5 .5h.9M73.7 134.1h.7v.1v2.9M75.3 137.1v1.6M76.2 134.1h.8M147.3 131.3h-5.2v1"/>
<path d="M213.9 123.2h1.1l.3 .2v1.3l-.4 .4h-3.4l-.1 2.1h-4M214.4 120.1v.8l-.5 .5v.8M216.1 120.1v.8l.5 .5v.8M217 126.2h1.8l.7 .7M74.4 140.5v5.4M75.3 140.5v1.4M76.3 140.5v2.9l-.1 .1M96.6 145.3h3.1M98.2 143.4v.9M120.3 141.2v.7l-.5 .4v.7M123.6 142.2v.8"/>
</g>
<g fill="none" stroke="#000" stroke-width=".25">
<path d="M80.7 56.6h-2.7v2.7l-.7 .7v1.3M82.7 56h-.7M82.7 57.3h-.9l-2.2 2.1h-.5M84.2 57.1h1M89 57.1h1.1M90.1 59.7h1M90.1 58.4h-1.8l-1.3 1.3v1.5l-1.5 1.5v1.8M91.6 57.9h-3.8l-.6 .5h-3.3l-.6 .6v18.8l.6 .7h2.3l.4 .4v1.5l-.1 .1h-1.3M94.9 56.1h1.4l1.6 1.7h3.7l1.3 1.2h1.3M94.9 59.7h1.7M95.8 58.1h1.2l.3 .4h3.9l1.3 1.3h2.7l1 1v6.2l.8 .8h1.4M107.8 56.5h1.8l1.7 1.7v3.3l2.9 2.9v4.3l1 1h10.8l.4-.4v-1.1"/>
<path d="M107.8 57.8h1.2l.9 .9v5.5M112.7 56.5l-1.7 .1-1.6-1.6h-25.1l-.7 .7v2l-1.2 1.2v5.3l-.2 .2M112.7 59h1.1M210.1 56.3l-3 2.9v22.6l2.2 2.1h1.2M74.7 61.3v1.7l.4 .3-.1 1.3M75.1 63.5h-.1M75.7 74.3v2.6l-.1 .2v1l.3 .4h1.4l.7 .6v1.3l.7 .7h3M76.3 69.7v-.4h-1.6l-.8 .8v11.7l.7 .6h1.2M77.6 77.1h2.3v1l.4 .4h2.2l.4 .4v2.5l-.4 .4h-.8M80.8 79.1l.1 .1h.8M81.2 70.6h-1.3l-.3 .3v2.2l.4 .4v.8h-2.5M81.8 74.3v.7l1.1 1.1v2.3l.4 .3v4.2l-.8 .8h-3.9l-1.9-1.9h-.9v-.7"/>
<path d="M82.2 66.1h-3.1l-.2 .3v3.7l-.5 .5h-2.1M84.7 77.6h1.7l1.6 1.6h2.1M84.8 74.9v.7h1.8l1.9 1.9h4.3l.2-.2h1M85.2 68.3h1M85.2 67.1h1.5l.8 .7v2.8l1.3 1.3h2.5l.9 .9v1.2l.9 .9h.8M85.2 79.2h-1.3l-.2 .3v3.7l-1 1h-6.6l-.4 .4v.9M85.5 65.1h-.9M85.6 76.2h-.8M85.7 72.9l-.1 .1h-.8M86.4 73.3l-.4 .3h-1.2M89.5 72.8l.2 .2h1M89.7 64.5h1.8l1.1 1v2.3h2.9l.3 .3v.7l-.2 .3h-.4"/>
<path d="M89.7 63.2h-1.3l-.4-.5h-.4l-.2 .3v2.4l-.5 .5h-2.7l-.5 .5v2.7l.5 .5h1M89.7 65.1l.1 .4M90.1 70.9h1M90.7 75.6h1.3l.6 .6h1.8l.5 .5v1.3l-1.1 1v3.9M90.7 74.9h1.5l.9 .9h2l.6 .6v.9l.2 .2v2.5M90.8 63.7l-2.5 .1-.3 .3v4.9l.6 .6h1.5M91.8 67.4v.4l-.5 .5h-1.2M93.9 61v.7M93.9 68.8l.1 4.7 1.4 1.4h.4M94.9 63.3h.7l1-1.1v-2.8l.4-.4h3.5l.3 .4v7.4l.7 .6h1.8l.5 .5v1.3l.7 .8h6l1.5-1.5v-2.2M95.7 68.9v2.2M95.8 61.1v.6h-.7l-1.2 1.2v2.4"/>
<path d="M95.8 65.3l.1 .7M97.5 67.2h.7l.6 .6v.8M98.3 73.3h1M99.3 64.8h1.5M99.3 63.5h-3l-1.4 1.4v1.9h1l1 1v4.3l-.8 .8h-1.2M99.3 78.6v.4h-1.4l-.5 .5v4.1l-.6 .6h-.7l-1.1 1.1v3.6M100.6 68.6h2.3M101.7 70.6l.5 .5v2.8l.7 .6h1.3M103.1 73.3h1.1M104.2 64.8h1.1l.2 .2v2.2l-.9 .9v.5h1.1l.2 .2v.3M121.3 68.2v1.5M123.8 68.2v-.6l.7-.7h12.1l.4 .5v.8"/>
<path d="M129.4 68.2v.8M132 66.9v1.3M210.1 61.5l-2.6 2.5v17.5l1.7 1.8h1.3M210.1 66.7l-2.2 2.1v12.5l1.3 1.3h1.3M210.1 71.9l-1.8 1.8v7.3l.9 1h1.3M210.1 77.1l-1.4 1.4v2.3l.5 .5h1.3M75.7 92.9h.8l.2 .2v1.5l-.2 .2h-.8M75.7 86.8h-1l-.3 .3v1.7l.4 .4h1.9l.5-.6h3.6l1-1h4l.7-.7h1.8M75.7 89.2v.6M75.7 90.5v1.1M75.7 93.5v.7M75.7 91.6h.1"/>
<path d="M80 94.2h.9M80 86.8l.9 .1M80 87.5h-.9M80 85.5h-.8l-.5-.4h-1.7l-.3 .2v.7l-.2 .2h-.8M83.4 88.1h2.8l.6-.6h2.7l.7 .6v2.4l.7 .8h1.1M83.4 93.8h6.3l.3 .4v1.3l1.4 1.4h19.9l.8 .9v3l.9 .9h5M83.4 92.6h-1.2l-.4 .4v5.9l.9 .9v.9M83.4 85.6v1.3h-1.4l-1.3 1.2h-4.6l-.4-.4v-.2M88.3 88.1h-1.3l-.6 .7h-4.6l-.4 .3h-1.3l-.1 2M90.1 81.8h1M91.5 89.5h1.3M91.5 85h1l.2 .3"/>
<path d="M91.5 85.6h-1.2l-1-1h-6.6l-1.5 1.6h-1.2M91.5 88.9h5.9M92 92.6h-1.8l-.7-.7h-7.6l-1 1h-.9v.6M95 86h-2.2l-.3 .3h-1M95 86.3h2.4M95.6 88.1l.1 .1h1.7M97 91.3h-2.5l-.6 .6h-3.2l-1.5-1.5h-7l-1.8 1.8h-1l-.4 .4v1.9l.3 .3h1.6l.5 .6v3.7l-.5 .4v2.9M97.4 85h-1.2l-.4 .4v.3M97.4 89.5h-1.9M100.2 93l.3 .2h.8M100.6 87.6l.4 .4h.3M101 89.9v.5l.3 .3"/>
<path d="M101.3 85.5h-1.5l-.2 .2-2.2-.1M106.2 85.5h1.4l.2 .2v.5M107.7 92.2v.5l-.5 .5h-1M109.3 95.9h.8M109.7 92.1l.4 .4v1M110.3 91.2v.6l.5 .4h.8l.3 .2v3.5M111.6 90.2v1M117.9 86.5h1M118 99.7v.5l-.3 .3M118.8 95.2h1.3l1.6 1.6v4.3l-.5 .5h-.7v.9l.4 .4h3.6l.4-.4v-.8M118.9 96.1l-.1 .4M118.9 89h1.4l.3 .4v2.5h1.8"/>
<path d="M118.9 87.8h2.1l.7-.7h5.7l.9 .9v5l.7 .7h7.7l.5-.5v-1.8l-.3-.2h-.8l-.2 .2v.6M120.4 99.7l.1 .1v.7M121.7 81.3l-.4 .4v.9M123.8 96.5h-1.4l-.2 .3v2.3l.6 .6h1.2M123.9 87.8h1.3l.8 .7h1.1v1.8M127.1 95.5v.8M128.9 92h.1M128.9 92h.5M129.4 97.7v.8M129.4 87.1h.5l1.7 1.7v1.7l.4 .4v1.1M129.4 85.4v-.8l.8-.8h5.7l.8 .8v.8M130 92v1"/>
<path d="M130.7 92v.6l.3 .4M130.7 97.7v.8h-.1M131.3 91.2v.8M132 97.7v1.3l.1 .1M132.3 85.1v.1l1 1h1.8l.5 .5v4M132.3 86.5v.6M132.6 97.7v-.9l-.3-.3h-3.8l-1.4 1.3 .1 3M132.6 92v.9l.2 .2h3.5l.2-.3v-.8M133.3 97.7v.8l-.5 .6h-1.3l-.5 .5h-1.5l-.5 .4v1.7l-.5 .5h-2.5l-.3-.2v-.9l-.2-.3h-2.3l-.2 .2v.7M133.7 85.3l.5 .1M133.9 92v1v.1M134.1 99.9h-.1l-1.5 1.6h-.7"/>
<path d="M134.2 87.1v1.4l.3 .3v1l-1.2 1.2v1M134.6 97.7h-.7v.9l-1.3 1.3h-.3l-.3 .4h-1.3l-.6 .5M135.1 90.7h1.9l.5 .6v2.3l-1 1v3.1M135.1 90.7h.1M135.1 90.7l-.5 .5v.8M135.2 91.3l.1 1.8M135.2 97.7v3.3l-.5 .5h-.6M135.3 91.3h-.1M135.9 93.7h.1M135.9 93.7v4M136 90.7h.1M136.7 87.1l-.2 .1v2.6"/>
<path d="M139.1 95.9v2.3h1.9M139.1 87.1v.5M139.1 91.5l.6 .1M140.8 93.8l-.7 .1M141 95.9h-.4l-.1 .1M148.8 96.3h.9M148.8 96.9h.9M149.7 97.6h-.9M159.7 97.8h2l.6 .6h1.5M159.7 99.1h1.3l.1 .1M160.8 97.1l-1.1 .1M160.8 97.1h.1"/>
<path d="M161.2 96.4l-.1 .1h-1.4M169.4 92.6h-1.3l-.4 .4v.7M189.1 94.2h1.5M190.6 91.7h1.3l.5 .5h6M193.9 93.5h4.1l.6 .6h1.2v3h1l.9-.8h2.9M193.9 91.5h-1.1l-.5-.4h-2.8l-.4 .3v4.5l.3 .2h2.6l1 1h1.2M193.9 90.9h1M195.3 97.1h2.7M198.9 92.2h.9M199.8 91.5h.8l.2 .2v1.6l-.2 .2h-1.8l-.6-.7h-5.8l-.1 .2h-1.7M199.8 90.9h-1.1l-.3 .3v1.3l.4 .3h1M202.6 97.2v.6"/>
<path d="M114.7 107.4h.9M115.6 107.4h.1M118.5 106.4h.9l.1 .1M120.2 111.2h1.1M120.2 111.2h.1M120.7 107.4v.2l.2 .2M121.3 111.7h1l.3 .3M129.7 107.3v1.1l-.2 .2M130.9 104.8h.1M130.9 104.8h.7M130.9 104.8v.7l.8 .8v1M132.3 104.8h.7"/>
<path d="M132.9 104.8l.1 .1v.7l-.8 .8v.9M133.7 107.3v1.3M136.8 104.8h2l.9 .9v2.6M139.7 108.3h.1M140.2 116.9l.3 .3h2.1M141.5 113.2h.1h1M142.5 108.6l.1 .1v.5M142.6 118.7h-.9l-.2 .3v.2M146.4 115.2h1.2M148.9 102.2h.8M149.5 107.3v1.1M149.5 108.4v.1"/>
<path d="M149.7 103.5l-.8 .1M149.7 102.9h.8M149.7 102.9h.1M150.5 107.3v.9l.2 .3M156 107.3v1.2M161.5 107.3v1l.2 .2M167.9 119.2h1M167.9 109.2h.1M167.9 109.2h1M168.9 119.7h-1.5l-.2 .2h-.8M168.9 106.7h1l.3 .4v2.3l-.3 .3h-1M170.3 114.2h-2.3l-.4 .3"/>
<path d="M170.3 114.2h.1M173.4 113.4h.7M175.3 105.8h3.5l.3 .3v.5M175.3 107.3h3.1M175.9 110.4h.1M177.7 108.3h.7M178 107.8h.1M178.4 109.8h-.7l-.3 .3v2.8l-.5 .5h-1M178.4 108.8h-1l-1.5 1.6M178.4 107.8h-1l-1 1h-1.1M178.4 109.3h-.8l-.7 .7v1.6l-.2 .3h-1.4M179.1 110.5v.5l-.5 .5"/>
<path d="M179.6 110.5v1.2l-.8 .8v.7M180.1 110.5v1.5M180.1 112h.1M180.5 101.2v.6M180.5 103v.9M180.6 111.2h.1M180.6 110.5v.7M181.1 110.5v1.1l-.1 .2M181.1 110.9h.1M181.5 104.8l-.4 .4v1.4M181.6 110.5v.9M181.6 111.4h.1"/>
<path d="M182.1 106.9l.2 .2v.2M182.3 109.8h.4l.6 .6M183 103h-.7l-1.7 1.6v2M183 101.2v.6M183.3 106.3l-.3-.3h-1.3l-.1 .2v.4M187.7 104h1M187.7 106.5h1M187.7 110.4h1M187.7 112.9h1M197.6 106.5h2.3l.6 .7h1.8M197.6 112.9h2.4l.7 .6h1.6M202.3 109.7h-1.6l-.6 .6h-2.5"/>
<path d="M202.3 103.4h-1.8l-.6 .6h-2.3M121.3 123.7h.8l.7 .8v.1M122.8 120.3v1.6l-.1 .3h-1.4M124.7 127.5v1.1M127.8 127.5l-.1 1.1M130.7 127.5h.1l.4 .4v2l-.5 .5M131.8 127.5l-.1 .1v2.1l.7 .7M133.2 127.5v1.1M140.7 127.6v1M142.1 129v.5M144.7 129v.5M146.4 126.5l.3-.3h.9v.5h-.9z"/>
<path d="M146.4 120.2h1.2M147.3 129v.5M152.9 127.4h-.6l-.3 .3v.9M158.1 127.5h-.4l-.2 .2v.9M160.3 127.5v.2l.2 .2v.7M160.9 127.5l.1 1.1M161.5 127.5v1.1M164.1 127.6l-.1 .1v.9M165 128.6h.5v.9l-.3 .3-.2-.2zM166 128.6v2.3l-.5 .5v3.1M170.1 125.1v.2l-.5 .4h-.7"/>
</g>
<g fill="none" stroke="#000" stroke-width=".38">
<path d="M90.1 57.1h2l1 1h.8M81.7 79.8h-.1h-1.8l-.4 .3M84.8 74.3h1.2M89 67.1h1.1M90.7 73.6l-.9 .1M90.7 74.3h-1.4l-.3 .2M103.3 79h.9M126.4 65.7l.6 .1M137 74.2l.8 .1M75.8 80.5h1.4M80.4 80.3l.2 .2h1.1M91.5 87.6h2.4"/>
<path d="M91.5 88.2l.1 .1 1.1 .1M93 86.6l-.3 .3h-1.2M93 86.6h.1M97.4 86.9h-1.1l-.2 .2M130 97.7h.1M130 97.1v.6M131.3 97.7l.1 .9M149.7 94.3l1 .1M150.6 91.1h.7M154.1 91.1h.6M155.6 90.2v.7M159.7 90.7h.1"/>
<path d="M159.7 92.6h1l.4 .4v.1M159.7 91.3h1.7M159.7 89.4h2.5M159.7 90h1.8M159.7 98.5h1M159.7 90.7h1M161 91.9l-1.3 .1M161.4 91.3h.1M161.7 98.6l.5 .5h7.2M168.3 91.3h1.1M168.3 89.3l.1 .1h1M169.4 91.3h.1"/>
<path d="M169.4 90h-1.1M174 96.9l.1 .1v.8M174.1 91.9v.8l-.1 .1M199.8 90.2l-.9 .1M204.6 85.2h1M210.5 85.2h-1.1M150.7 104.1l-1 .1M150.7 100.2v.1h-1M154.6 104.1l1 .1M114.3 138.7h2.9M117.2 131.8h1.2l.2 .3h1.8M119.6 134.5v.8l-.1 .1"/>
<path d="M120.3 134.5v.9M120.3 134.5h.1M120.9 134.5h.7M121.5 132.1h2.1l-.1 2.4h.7M122.2 138.5l.4-.4 .3 .4v1.9h-.7zM122.2 134.5h.7v1.9l-.3 .3-.4-.3zM125.3 132.1v.6l-.5 .5v1.3M125.5 134.5v1.4M125.5 135.9h.1M119.6 140.4v-.9l.2-.2h1l.1 .2v.9h.7M119.8 143v.8M120.3 140.4v.8"/>
<path d="M120.3 141.2h.1M124.2 140.4h-.7l.1 .8M124.8 140.4v.8M124.8 141.2h.1"/>
</g>
<path d="M134.5 68.2h.8l.1 .1M178.8 61.1v1M82.7 100.7h3.8l2.1 2.2v1.2l.6 .5M181.9 113.2h2.5M213.4 120.1h1M213.6 126.2h.9l1.8 1.8h.7v2.8M213.6 128v1.8" fill="none" stroke="#000" stroke-width=".89"/>
<g fill="none" stroke="#000" stroke-width=".63">
<path d="M127.8 55h-2l-2 2h-3.5l-1.6 1.6v1.1M130.8 55h2M131.3 59h-2.2l-.9-.8h-3l-1.4 1.4v.1M135.7 55h2M140.7 55h2M145.6 55h2M160.3 54.9v3.9l-1.4 1.4h-5l-1.4-1.4v-3.2l-.6-.6h-1.3M129.4 76.6l.1 .1h.7M157 68.1h4.9l.8-.8h4.2l.4 .4v1.9M157 71.4v.9M160.1 70.1v2.9l-1 1M179.5 69.3h2.7l.3 .3v3.7l1 1h2.5"/>
<path d="M182 69.3l-.5 .5M184 75.9h.7l1.3 1.4v1M139.1 95.9v2.3h1.9M140.1 99.4v.8M141 91.5v2.2l-.2 .2h-.7M141 87.1v2l-.4 .4h-.5M144.5 85.9v1.5M203.3 91.7h1.6M210.8 92.6h.9l.4 .3h.8v3.1l-.3 .3M210.8 90.2v.6M216.6 124.1v1l.4 .4v.7M95.1 143.6v.8"/>
<path d="M98.2 146.2h-3h-.1v.7M101.7 145.3h1.4M104.5 143.1v1.3l-.1-.1h-2.7M106.9 146.2h-5.2"/>
</g>
<g fill="none" stroke="#000" stroke-width="1">
<path d="M157.7 54.9v2.1M162.8 54.9v2M178.8 53.8v1M178.8 57.2v1.9M135.2 61.8v3.1M145.7 67.7v4.6l5 5v2M145.7 76.6v2.7M150.7 69.8v1.9M165.4 62.1v2.4M167.3 76.4v2.8M169.8 79.2v3.3l-.8 .8h-23.7l-.8 .8v1.8M172.8 64.2l.4 .3"/>
<path d="M76.2 143.5h1.4M217.7 144h1.1"/>
</g>
<path d="M172.8 62v2.2M193.3 75.4v2" fill="none" stroke="#000" stroke-width="1.4"/>
<path d="M172.8 55.3v2.6l.8 .8h7.5l.8 .7M134.1 61.8h1.1" fill="none" stroke="#000" stroke-width="1.1"/>
<path d="M121.7 55h1.1M159.1 76.8v3.1" fill="none" stroke="#000" stroke-width="1.3"/>
<g fill="none" stroke="#000" stroke-width=".76">
<path d="M133.4 59h1.8M137.3 59v2.8M137.3 59h2.9M137.3 59h.1M144.3 58.9v2M146.3 58.9h1.8M150.1 58.9v2M165.4 54.9v5.1M137.3 64.9h.1M137.3 64.9h4.8l.1 .1M140.2 61.1v1.8M144.3 63v2"/>
<path d="M148.1 65l.1 .2v4.6M150.1 63v2M153.3 69.8v1.8M153.3 77.3v2M172.3 69.6v2.4l-2 2h-11.2M172.3 75.7v3.5M174.9 69.6v1.9M174.9 76.8v2.4M179.5 69.3h-1.1l-2.5-2.5h-5.1l-1 1v1.8M199.9 66.7h-2.3l-1.5 1.5-5.1-.1-1.3 1.2h-3.2M140.1 85.1h.1M140.1 85.1h1.4l.8 .8h2.2"/>
<path d="M143.6 93.1h1.9M144.5 95.1h3.5M144.5 89.9v3.1M148.2 99.6l-.1 .1h-2.6M204.6 96.3h1.8M208.1 96.3h2.2"/>
</g>
<path d="M182.3 109.3h.1M183.8 107v.3l-.6 .6-.9-.1M184.3 107.6h-.2l-.8 .7h-1M187.7 104l-1 1.1h-.5l-.5 .5v3.6l-.4 .4h-.8l-.8-.7-1.4-.1M187.7 106.5l-1-1h-.3l-.2 .3v3.6l-.7 .7h-1.2l-.8-.8h-1.2M207.6 103.4h1.1l1.7 1.7h.8l2.5 2.5h6.6l2.6 2.6h.6l1-1.1M207.6 107.2h1.1l1.7-1.7h.6l2.5 2.5h6.6l2.6 2.6h.8l1 1.1M219.5 109.1l-1.1 1.1h-1.5l-.1-.2v-.6a.65 .65 0 0 0-.7-.6 .65 .65 0 0 0-.6 .6v1.9l-.2 .2-.2-.2v-1.9a.65 .65 0 0 0-.7-.6 .65 .65 0 0 0-.6 .6l-.1 .7-1.2 .1-1.3 1.2h-.8l-1.7-1.7h-1.1M219.5 111.7l-1.1-1.1h-1.4l-.4-.1-.2-.3-.1-.8-.2-.1-.2 .2v1.9a.65 .65 0 0 1-.6 .6 .65 .65 0 0 1-.7-.6v-1.9l-.2-.2-.1 .1-.1 .9-.3 .3h-1.3l-1.2 1.3h-1l-1.7 1.6h-1.1" fill="none" stroke="#000" stroke-width=".2"/>
<use href="#words"/>
</svg>
